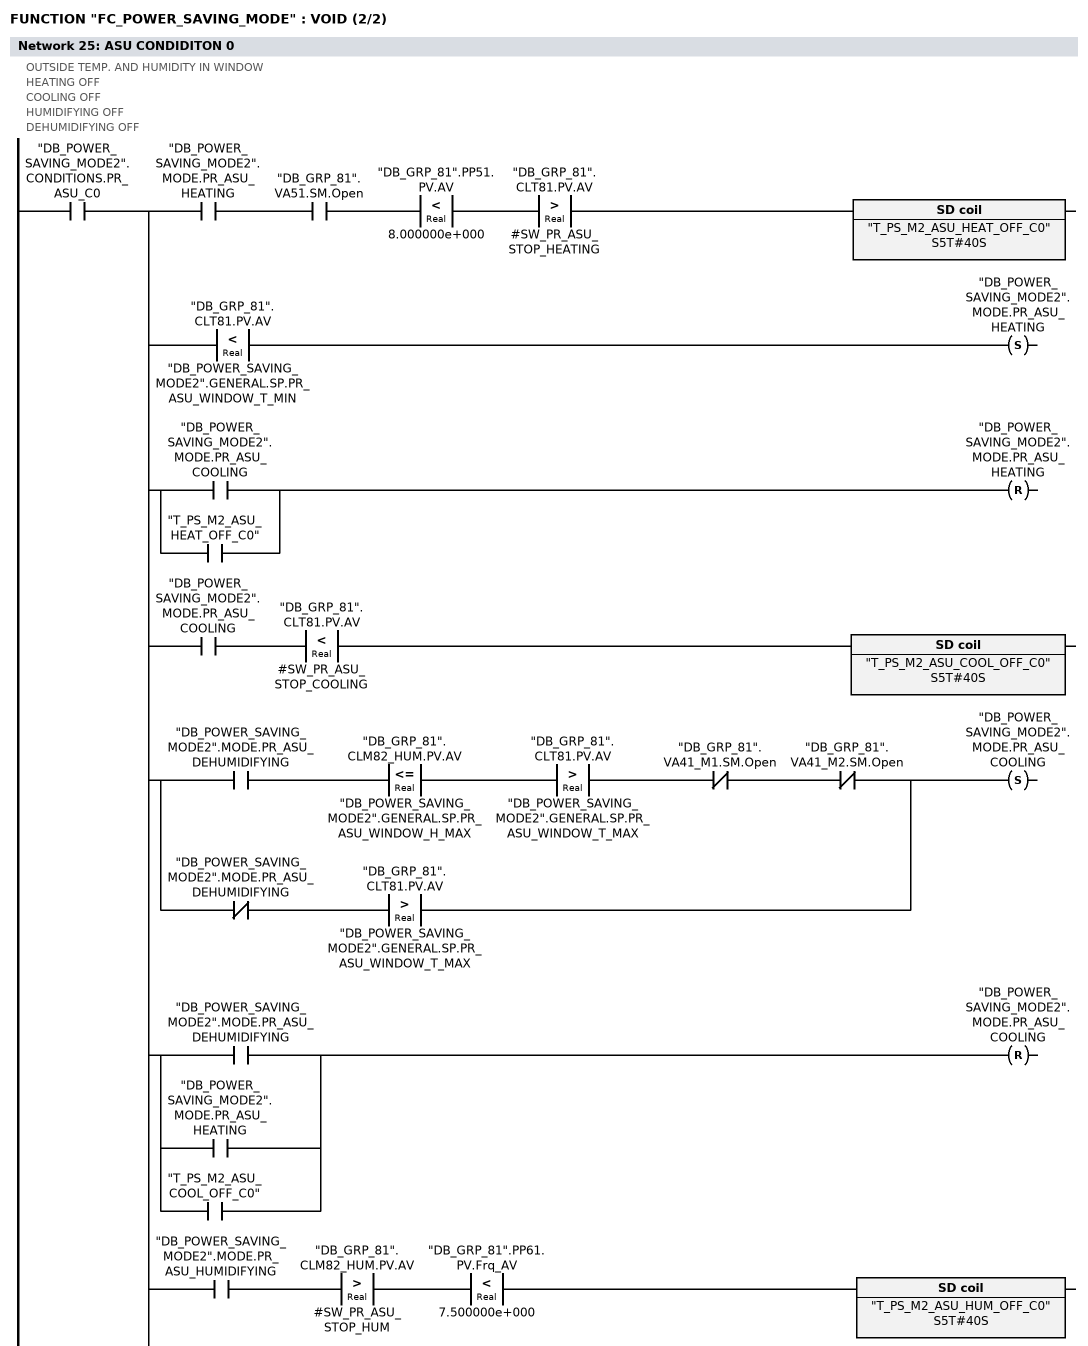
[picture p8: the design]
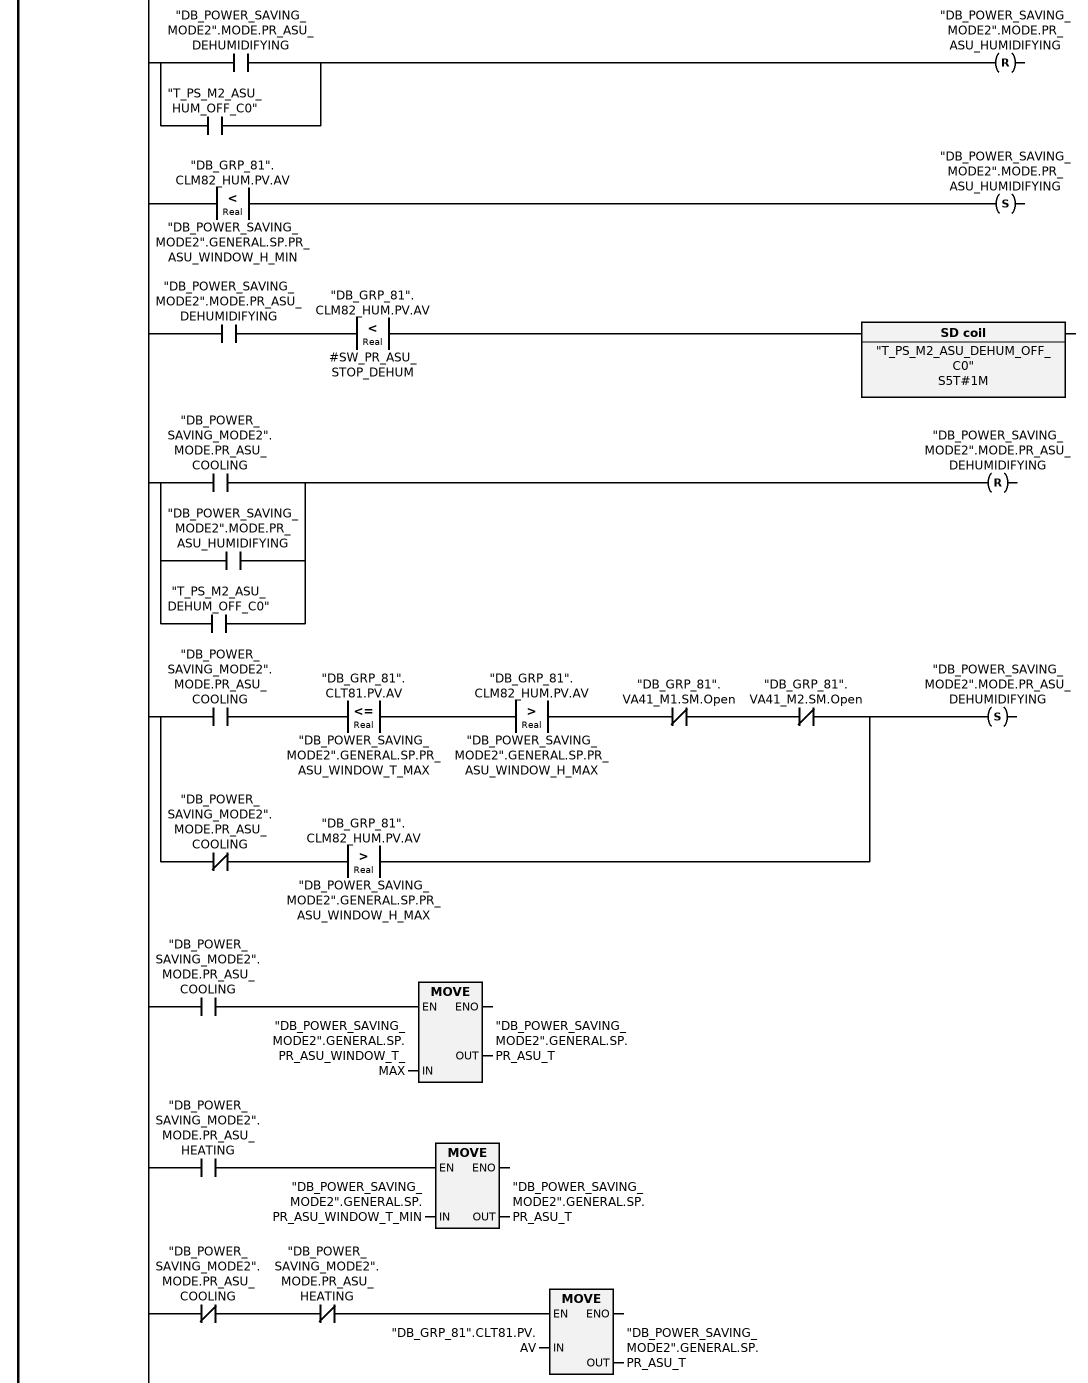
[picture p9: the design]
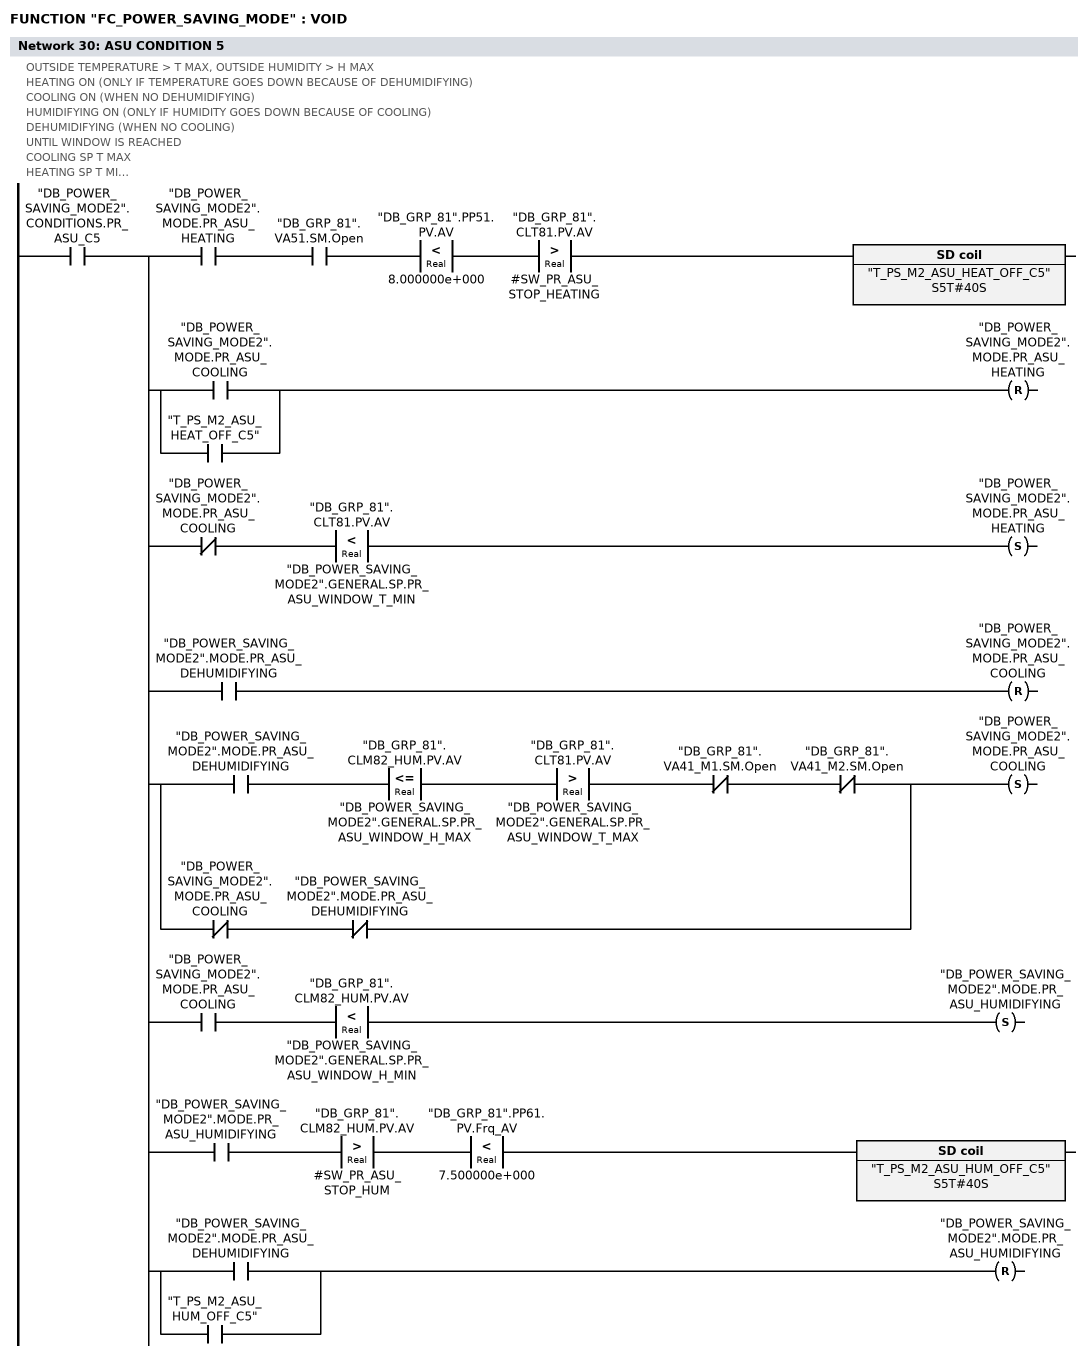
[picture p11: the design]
FUNCTION "FC_POWER_SAVING_MODE" : VOID
TITLE =POWER SAVING MODE
{ S7_language := '9(1) Angielski (Stany Zjednoczone)  11.01.2022  09:45:15' }
VERSION : 0.1


VAR_TEMP
  CDT : DATE_AND_TIME ;
  READ_CLOCK_RET_VAL : INT ;
  ACT_TIME : TIME_OF_DAY ;
  ACT_TIME_H : INT ;
  ACT_TIME_M : INT ;
  ACT_TIME_S : INT ;
  SW_PR_ASU_STOP_HEATING : REAL ;
  SW_PR_ASU_START_HEATING : REAL ;
  SW_PR_ASU_STOP_COOLING : REAL ;
  SW_PR_ASU_STOP_HUM : REAL ;
  SW_PR_ASU_STOP_DEHUM : REAL ;
  SW_PR_ASU_START_COOLING : REAL ;
  SW_PR_ARU_STOP_COOLING : REAL ;
  SW_PR_ARU_STOP_DEHUM : REAL ;
  SW_PR_ARU_START_COOLING : REAL ;
  SW_PR_F_STOP_HEATING : REAL ;
  SW_CR_ASU_STOP_HEATING : REAL ;
  SW_CR_ASU_STOP_COOLING : REAL ;
  SW_CR_ASU_STOP_HUM : REAL ;
  SW_CR_ASU_STOP_DEHUM : REAL ;
  SW_CR_ASU_START_COOLING : REAL ;
  SW_CR_ASU_START_HEATING : REAL ;
END_VAR
BEGIN
NETWORK
TITLE =READING ACTUAL TIME FROM PLC
//********************************************************************************
//
//                         AUTOMATIC SETPOINTS UPDATE
//
//********************************************************************************
//
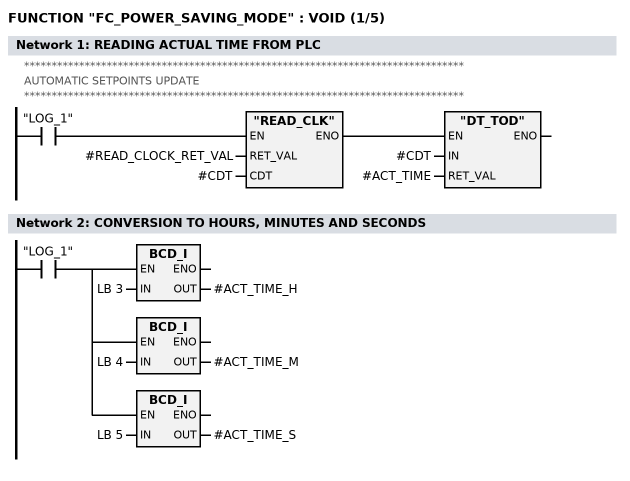
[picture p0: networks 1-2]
      U(    ;
      U     "LOG_1";
      SPBNB _001;
      CALL "READ_CLK" (
           RET_VAL                  := #READ_CLOCK_RET_VAL,
           CDT                      := #CDT);
_001: U     BIE;
      )     ;
      SPBNB _002;
      CALL "DT_TOD" (
           IN                       := #CDT,
           RET_VAL                  := #ACT_TIME);
_002: NOP   0;
NETWORK
TITLE =CONVERSION TO HOURS, MINUTES AND SECONDS

      U     "LOG_1";
      =     L     60.0;
      U     L     60.0;
      SPBNB _J1;
      L     LB     3;
      BTI   ;
      T     #ACT_TIME_H;
_J1:  NOP   0;
      U     L     60.0;
      SPBNB _J2;
      L     LB     4;
      BTI   ;
      T     #ACT_TIME_M;
_J2:  NOP   0;
      U     L     60.0;
      SPBNB _J3;
      L     LB     5;
      BTI   ;
      T     #ACT_TIME_S;
_J3:  NOP   0;
NETWORK
TITLE =LIMIT TIME SET BY OPERATOR

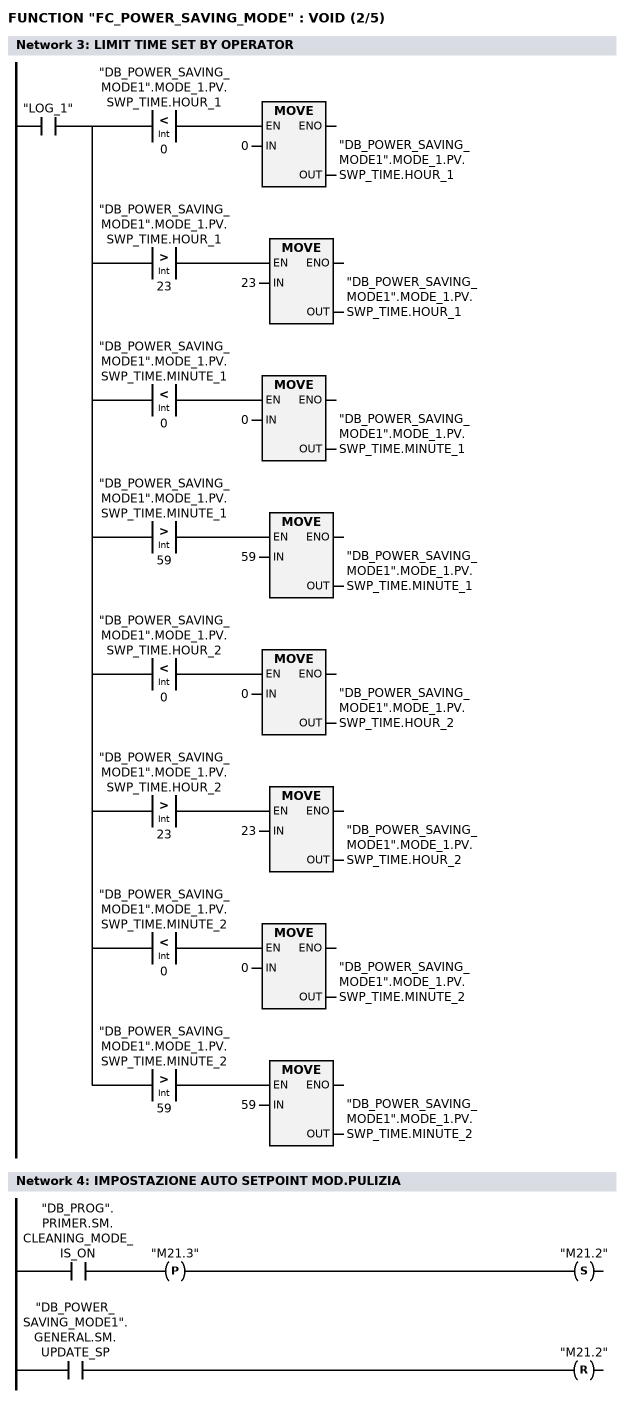
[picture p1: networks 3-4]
      U     "LOG_1";
      =     L     84.0;
      U     L     84.0;
      U(    ;
      L     "DB_POWER_SAVING_MODE1".MODE_1.PV.SWP_TIME.HOUR_1;
      L     0;
      <I    ;
      )     ;
      SPBNB _003;
      L     0;
      T     "DB_POWER_SAVING_MODE1".MODE_1.PV.SWP_TIME.HOUR_1;
_003: NOP   0;
      U     L     84.0;
      U(    ;
      L     "DB_POWER_SAVING_MODE1".MODE_1.PV.SWP_TIME.HOUR_1;
      L     23;
      >I    ;
      )     ;
      SPBNB _004;
      L     23;
      T     "DB_POWER_SAVING_MODE1".MODE_1.PV.SWP_TIME.HOUR_1;
_004: NOP   0;
      U     L     84.0;
      U(    ;
      L     "DB_POWER_SAVING_MODE1".MODE_1.PV.SWP_TIME.MINUTE_1;
      L     0;
      <I    ;
      )     ;
      SPBNB _005;
      L     0;
      T     "DB_POWER_SAVING_MODE1".MODE_1.PV.SWP_TIME.MINUTE_1;
_005: NOP   0;
      U     L     84.0;
      U(    ;
      L     "DB_POWER_SAVING_MODE1".MODE_1.PV.SWP_TIME.MINUTE_1;
      L     59;
      >I    ;
      )     ;
      SPBNB _006;
      L     59;
      T     "DB_POWER_SAVING_MODE1".MODE_1.PV.SWP_TIME.MINUTE_1;
_006: NOP   0;
      U     L     84.0;
      U(    ;
      L     "DB_POWER_SAVING_MODE1".MODE_1.PV.SWP_TIME.HOUR_2;
      L     0;
      <I    ;
      )     ;
      SPBNB _007;
      L     0;
      T     "DB_POWER_SAVING_MODE1".MODE_1.PV.SWP_TIME.HOUR_2;
_007: NOP   0;
      U     L     84.0;
      U(    ;
      L     "DB_POWER_SAVING_MODE1".MODE_1.PV.SWP_TIME.HOUR_2;
      L     23;
      >I    ;
      )     ;
      SPBNB _008;
      L     23;
      T     "DB_POWER_SAVING_MODE1".MODE_1.PV.SWP_TIME.HOUR_2;
_008: NOP   0;
      U     L     84.0;
      U(    ;
      L     "DB_POWER_SAVING_MODE1".MODE_1.PV.SWP_TIME.MINUTE_2;
      L     0;
      <I    ;
      )     ;
      SPBNB _009;
      L     0;
      T     "DB_POWER_SAVING_MODE1".MODE_1.PV.SWP_TIME.MINUTE_2;
_009: NOP   0;
      U     L     84.0;
      U(    ;
      L     "DB_POWER_SAVING_MODE1".MODE_1.PV.SWP_TIME.MINUTE_2;
      L     59;
      >I    ;
      )     ;
      SPBNB _00a;
      L     59;
      T     "DB_POWER_SAVING_MODE1".MODE_1.PV.SWP_TIME.MINUTE_2;
_00a: NOP   0;
NETWORK
TITLE =IMPOSTAZIONE AUTO SETPOINT MOD.PULIZIA

      U     "DB_PROG".PRIMER.SM.CLEANING_MODE_IS_ON;
      FP    "M21.3";
      S     "M21.2";
      U     "DB_POWER_SAVING_MODE1".GENERAL.SM.UPDATE_SP;
      R     "M21.2";
      NOP   0;
NETWORK
TITLE =CHANGE SETPOINTS TWO TIMES PER DAY ACCORDING TO TIME SET

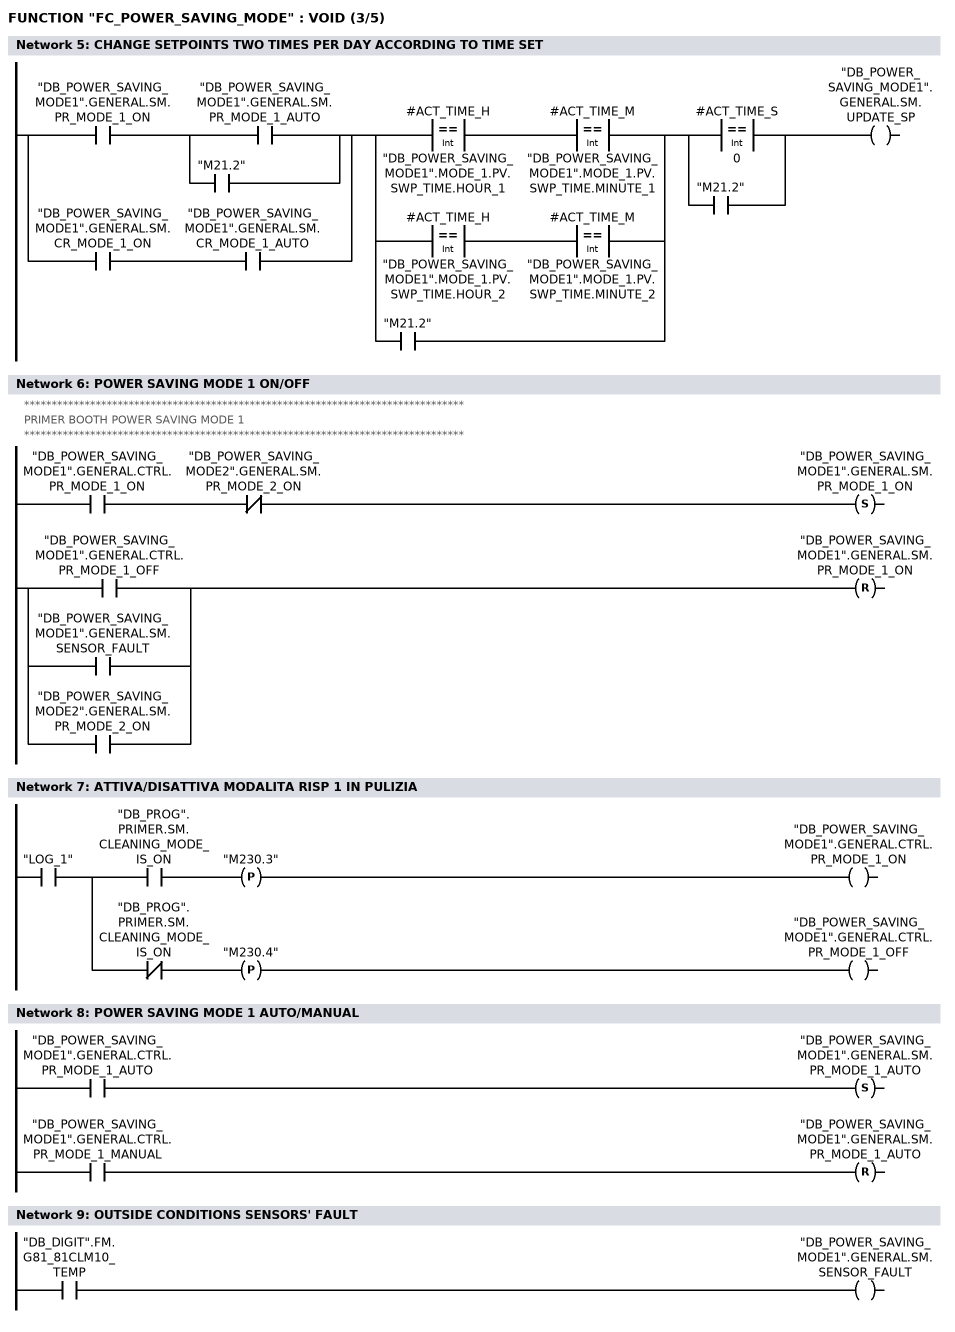
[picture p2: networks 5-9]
      U(    ;
      U     "DB_POWER_SAVING_MODE1".GENERAL.SM.PR_MODE_1_ON;
      U(    ;
      O     "DB_POWER_SAVING_MODE1".GENERAL.SM.PR_MODE_1_AUTO;
      O     "M21.2";
      )     ;
      O     ;
      U     "DB_POWER_SAVING_MODE1".GENERAL.SM.CR_MODE_1_ON;
      U     "DB_POWER_SAVING_MODE1".GENERAL.SM.CR_MODE_1_AUTO;
      )     ;
      U(    ;
      U(    ;
      L     #ACT_TIME_H;
      L     "DB_POWER_SAVING_MODE1".MODE_1.PV.SWP_TIME.HOUR_1;
      ==I   ;
      )     ;
      U(    ;
      L     #ACT_TIME_M;
      L     "DB_POWER_SAVING_MODE1".MODE_1.PV.SWP_TIME.MINUTE_1;
      ==I   ;
      )     ;
      O     ;
      U(    ;
      L     #ACT_TIME_H;
      L     "DB_POWER_SAVING_MODE1".MODE_1.PV.SWP_TIME.HOUR_2;
      ==I   ;
      )     ;
      U(    ;
      L     #ACT_TIME_M;
      L     "DB_POWER_SAVING_MODE1".MODE_1.PV.SWP_TIME.MINUTE_2;
      ==I   ;
      )     ;
      O     "M21.2";
      )     ;
      U(    ;
      O(    ;
      L     #ACT_TIME_S;
      L     0;
      ==I   ;
      )     ;
      O     "M21.2";
      )     ;
      =     "DB_POWER_SAVING_MODE1".GENERAL.SM.UPDATE_SP;
NETWORK
TITLE =POWER SAVING MODE 1 ON/OFF
//********************************************************************************
//
//                     PRIMER BOOTH POWER SAVING MODE 1
//
//********************************************************************************
//
      U     "DB_POWER_SAVING_MODE1".GENERAL.CTRL.PR_MODE_1_ON;
      UN    "DB_POWER_SAVING_MODE2".GENERAL.SM.PR_MODE_2_ON;
      S     "DB_POWER_SAVING_MODE1".GENERAL.SM.PR_MODE_1_ON;
      U(    ;
      O     "DB_POWER_SAVING_MODE1".GENERAL.CTRL.PR_MODE_1_OFF;
      O     "DB_POWER_SAVING_MODE1".GENERAL.SM.SENSOR_FAULT;
      O     "DB_POWER_SAVING_MODE2".GENERAL.SM.PR_MODE_2_ON;
      )     ;
      R     "DB_POWER_SAVING_MODE1".GENERAL.SM.PR_MODE_1_ON;
      NOP   0;
NETWORK
TITLE =ATTIVA/DISATTIVA MODALITA RISP 1 IN PULIZIA

      U     "LOG_1";
      =     L     84.0;
      U     L     84.0;
      U     "DB_PROG".PRIMER.SM.CLEANING_MODE_IS_ON;
      FP    "M230.3";
      =     "DB_POWER_SAVING_MODE1".GENERAL.CTRL.PR_MODE_1_ON;
      U     L     84.0;
      UN    "DB_PROG".PRIMER.SM.CLEANING_MODE_IS_ON;
      FP    "M230.4";
      =     "DB_POWER_SAVING_MODE1".GENERAL.CTRL.PR_MODE_1_OFF;
NETWORK
TITLE =POWER SAVING MODE 1 AUTO/MANUAL

      U     "DB_POWER_SAVING_MODE1".GENERAL.CTRL.PR_MODE_1_AUTO;
      S     "DB_POWER_SAVING_MODE1".GENERAL.SM.PR_MODE_1_AUTO;
      U     "DB_POWER_SAVING_MODE1".GENERAL.CTRL.PR_MODE_1_MANUAL;
      R     "DB_POWER_SAVING_MODE1".GENERAL.SM.PR_MODE_1_AUTO;
      NOP   0;
NETWORK
TITLE =OUTSIDE CONDITIONS SENSORS' FAULT

      U     "DB_DIGIT".FM.G81_81CLM10_TEMP;
      =     "DB_POWER_SAVING_MODE1".GENERAL.SM.SENSOR_FAULT;
NETWORK
TITLE =EXTREME SUMMER MODE

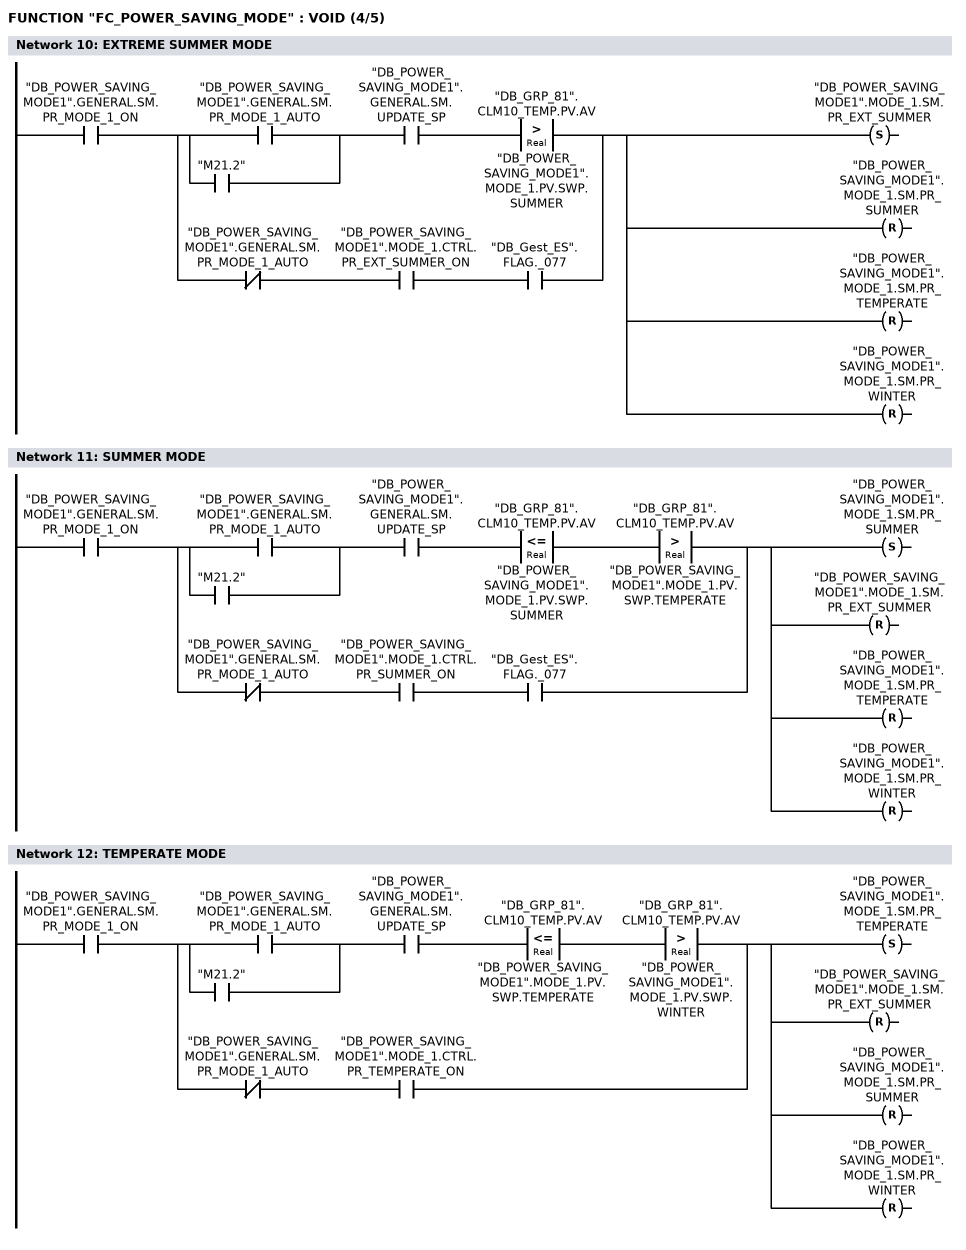
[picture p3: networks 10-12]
      U     "DB_POWER_SAVING_MODE1".GENERAL.SM.PR_MODE_1_ON;
      U(    ;
      U(    ;
      O     "DB_POWER_SAVING_MODE1".GENERAL.SM.PR_MODE_1_AUTO;
      O     "M21.2";
      )     ;
      U     "DB_POWER_SAVING_MODE1".GENERAL.SM.UPDATE_SP;
      U(    ;
      L     "DB_GRP_81".CLM10_TEMP.PV.AV;
      L     "DB_POWER_SAVING_MODE1".MODE_1.PV.SWP.SUMMER;
      >R    ;
      )     ;
      O     ;
      UN    "DB_POWER_SAVING_MODE1".GENERAL.SM.PR_MODE_1_AUTO;
      U     "DB_POWER_SAVING_MODE1".MODE_1.CTRL.PR_EXT_SUMMER_ON;
      U     "DB_Gest_ES".FLAG._077;
      )     ;
      S     "DB_POWER_SAVING_MODE1".MODE_1.SM.PR_EXT_SUMMER;
      R     "DB_POWER_SAVING_MODE1".MODE_1.SM.PR_SUMMER;
      R     "DB_POWER_SAVING_MODE1".MODE_1.SM.PR_TEMPERATE;
      R     "DB_POWER_SAVING_MODE1".MODE_1.SM.PR_WINTER;
NETWORK
TITLE =SUMMER MODE

      U     "DB_POWER_SAVING_MODE1".GENERAL.SM.PR_MODE_1_ON;
      U(    ;
      U(    ;
      O     "DB_POWER_SAVING_MODE1".GENERAL.SM.PR_MODE_1_AUTO;
      O     "M21.2";
      )     ;
      U     "DB_POWER_SAVING_MODE1".GENERAL.SM.UPDATE_SP;
      U(    ;
      L     "DB_GRP_81".CLM10_TEMP.PV.AV;
      L     "DB_POWER_SAVING_MODE1".MODE_1.PV.SWP.SUMMER;
      <=R   ;
      )     ;
      U(    ;
      L     "DB_GRP_81".CLM10_TEMP.PV.AV;
      L     "DB_POWER_SAVING_MODE1".MODE_1.PV.SWP.TEMPERATE;
      >R    ;
      )     ;
      O     ;
      UN    "DB_POWER_SAVING_MODE1".GENERAL.SM.PR_MODE_1_AUTO;
      U     "DB_POWER_SAVING_MODE1".MODE_1.CTRL.PR_SUMMER_ON;
      U     "DB_Gest_ES".FLAG._077;
      )     ;
      S     "DB_POWER_SAVING_MODE1".MODE_1.SM.PR_SUMMER;
      R     "DB_POWER_SAVING_MODE1".MODE_1.SM.PR_EXT_SUMMER;
      R     "DB_POWER_SAVING_MODE1".MODE_1.SM.PR_TEMPERATE;
      R     "DB_POWER_SAVING_MODE1".MODE_1.SM.PR_WINTER;
NETWORK
TITLE =TEMPERATE MODE

      U     "DB_POWER_SAVING_MODE1".GENERAL.SM.PR_MODE_1_ON;
      U(    ;
      U(    ;
      O     "DB_POWER_SAVING_MODE1".GENERAL.SM.PR_MODE_1_AUTO;
      O     "M21.2";
      )     ;
      U     "DB_POWER_SAVING_MODE1".GENERAL.SM.UPDATE_SP;
      U(    ;
      L     "DB_GRP_81".CLM10_TEMP.PV.AV;
      L     "DB_POWER_SAVING_MODE1".MODE_1.PV.SWP.TEMPERATE;
      <=R   ;
      )     ;
      U(    ;
      L     "DB_GRP_81".CLM10_TEMP.PV.AV;
      L     "DB_POWER_SAVING_MODE1".MODE_1.PV.SWP.WINTER;
      >R    ;
      )     ;
      O     ;
      UN    "DB_POWER_SAVING_MODE1".GENERAL.SM.PR_MODE_1_AUTO;
      U     "DB_POWER_SAVING_MODE1".MODE_1.CTRL.PR_TEMPERATE_ON;
      )     ;
      S     "DB_POWER_SAVING_MODE1".MODE_1.SM.PR_TEMPERATE;
      R     "DB_POWER_SAVING_MODE1".MODE_1.SM.PR_EXT_SUMMER;
      R     "DB_POWER_SAVING_MODE1".MODE_1.SM.PR_SUMMER;
      R     "DB_POWER_SAVING_MODE1".MODE_1.SM.PR_WINTER;
NETWORK
TITLE =WINTER MODE

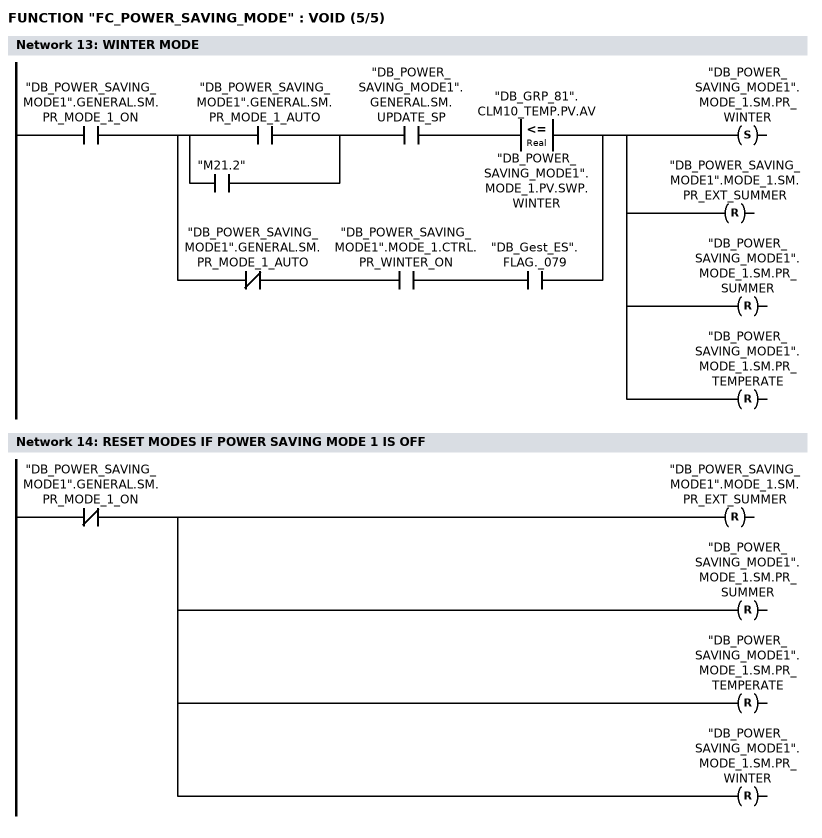
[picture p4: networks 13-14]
      U     "DB_POWER_SAVING_MODE1".GENERAL.SM.PR_MODE_1_ON;
      U(    ;
      U(    ;
      O     "DB_POWER_SAVING_MODE1".GENERAL.SM.PR_MODE_1_AUTO;
      O     "M21.2";
      )     ;
      U     "DB_POWER_SAVING_MODE1".GENERAL.SM.UPDATE_SP;
      U(    ;
      L     "DB_GRP_81".CLM10_TEMP.PV.AV;
      L     "DB_POWER_SAVING_MODE1".MODE_1.PV.SWP.WINTER;
      <=R   ;
      )     ;
      O     ;
      UN    "DB_POWER_SAVING_MODE1".GENERAL.SM.PR_MODE_1_AUTO;
      U     "DB_POWER_SAVING_MODE1".MODE_1.CTRL.PR_WINTER_ON;
      U     "DB_Gest_ES".FLAG._079;
      )     ;
      S     "DB_POWER_SAVING_MODE1".MODE_1.SM.PR_WINTER;
      R     "DB_POWER_SAVING_MODE1".MODE_1.SM.PR_EXT_SUMMER;
      R     "DB_POWER_SAVING_MODE1".MODE_1.SM.PR_SUMMER;
      R     "DB_POWER_SAVING_MODE1".MODE_1.SM.PR_TEMPERATE;
NETWORK
TITLE =RESET MODES IF POWER SAVING MODE 1 IS OFF

      UN    "DB_POWER_SAVING_MODE1".GENERAL.SM.PR_MODE_1_ON;
      R     "DB_POWER_SAVING_MODE1".MODE_1.SM.PR_EXT_SUMMER;
      R     "DB_POWER_SAVING_MODE1".MODE_1.SM.PR_SUMMER;
      R     "DB_POWER_SAVING_MODE1".MODE_1.SM.PR_TEMPERATE;
      R     "DB_POWER_SAVING_MODE1".MODE_1.SM.PR_WINTER;
NETWORK
TITLE =SETPOINT SELECTION

      U     "LOG_1";
      =     L     84.0;
      U     L     84.0;
      U     "DB_POWER_SAVING_MODE1".MODE_1.SM.PR_EXT_SUMMER;
      =     L     84.1;
      U     L     84.1;
      SPBNB _00b;
      L     "DB_POWER_SAVING_MODE1".MODE_1.PV.SP.PR_ASU_EXT_SUMMER_T;
      T     "DB_POWER_SAVING_MODE1".MODE_1.PV.SP.PR_ASU_T;
_00b: NOP   0;
      U     L     84.1;
      SPBNB _00c;
      L     "DB_POWER_SAVING_MODE1".MODE_1.PV.SP.PR_ASU_EXT_SUMMER_H;
      T     "DB_POWER_SAVING_MODE1".MODE_1.PV.SP.PR_ASU_H;
_00c: NOP   0;
      U     L     84.1;
      SPBNB _00d;
      L     "DB_POWER_SAVING_MODE1".MODE_1.PV.SP.PR_ARU_EXT_SUMMER_T;
      T     "DB_POWER_SAVING_MODE1".MODE_1.PV.SP.PR_ARU_T;
_00d: NOP   0;
      U     L     84.1;
      SPBNB _00e;
      L     "DB_POWER_SAVING_MODE1".MODE_1.PV.SP.PR_ARU_EXT_SUMMER_H;
      T     "DB_POWER_SAVING_MODE1".MODE_1.PV.SP.PR_ARU_H;
_00e: NOP   0;
      U     L     84.1;
      SPBNB _00f;
      L     "DB_POWER_SAVING_MODE1".MODE_1.PV.SP.PR_FLASHOFF_EXT_SUMMER_T;
      T     "DB_POWER_SAVING_MODE1".MODE_1.PV.SP.PR_FLASHOFF_T;
_00f: NOP   0;
      U     L     84.0;
      U     "DB_POWER_SAVING_MODE1".MODE_1.SM.PR_SUMMER;
      =     L     84.1;
      U     L     84.1;
      SPBNB _010;
      L     "DB_POWER_SAVING_MODE1".MODE_1.PV.SP.PR_ASU_SUMMER_T;
      T     "DB_POWER_SAVING_MODE1".MODE_1.PV.SP.PR_ASU_T;
_010: NOP   0;
      U     L     84.1;
      SPBNB _011;
      L     "DB_POWER_SAVING_MODE1".MODE_1.PV.SP.PR_ASU_SUMMER_H;
      T     "DB_POWER_SAVING_MODE1".MODE_1.PV.SP.PR_ASU_H;
_011: NOP   0;
      U     L     84.1;
      SPBNB _012;
      L     "DB_POWER_SAVING_MODE1".MODE_1.PV.SP.PR_ARU_SUMMER_T;
      T     "DB_POWER_SAVING_MODE1".MODE_1.PV.SP.PR_ARU_T;
_012: NOP   0;
      U     L     84.1;
      SPBNB _013;
      L     "DB_POWER_SAVING_MODE1".MODE_1.PV.SP.PR_ARU_SUMMER_H;
      T     "DB_POWER_SAVING_MODE1".MODE_1.PV.SP.PR_ARU_H;
_013: NOP   0;
      U     L     84.1;
      SPBNB _014;
      L     "DB_POWER_SAVING_MODE1".MODE_1.PV.SP.PR_FLASHOFF_SUMMER_T;
      T     "DB_POWER_SAVING_MODE1".MODE_1.PV.SP.PR_FLASHOFF_T;
_014: NOP   0;
      U     L     84.0;
      U     "DB_POWER_SAVING_MODE1".MODE_1.SM.PR_TEMPERATE;
      =     L     84.1;
      U     L     84.1;
      SPBNB _015;
      L     "DB_POWER_SAVING_MODE1".MODE_1.PV.SP.PR_ASU_TEMPERATE_T;
      T     "DB_POWER_SAVING_MODE1".MODE_1.PV.SP.PR_ASU_T;
_015: NOP   0;
      U     L     84.1;
      SPBNB _016;
      L     "DB_POWER_SAVING_MODE1".MODE_1.PV.SP.PR_ASU_TEMPERATE_H;
      T     "DB_POWER_SAVING_MODE1".MODE_1.PV.SP.PR_ASU_H;
_016: NOP   0;
      U     L     84.1;
      SPBNB _017;
      L     "DB_POWER_SAVING_MODE1".MODE_1.PV.SP.PR_ARU_TEMPERATE_T;
      T     "DB_POWER_SAVING_MODE1".MODE_1.PV.SP.PR_ARU_T;
_017: NOP   0;
      U     L     84.1;
      SPBNB _018;
      L     "DB_POWER_SAVING_MODE1".MODE_1.PV.SP.PR_ARU_TEMPERATE_H;
      T     "DB_POWER_SAVING_MODE1".MODE_1.PV.SP.PR_ARU_H;
_018: NOP   0;
      U     L     84.1;
      SPBNB _019;
      L     "DB_POWER_SAVING_MODE1".MODE_1.PV.SP.PR_FLASHOFF_TEMPERATE_T;
      T     "DB_POWER_SAVING_MODE1".MODE_1.PV.SP.PR_FLASHOFF_T;
_019: NOP   0;
      U     L     84.0;
      U     "DB_POWER_SAVING_MODE1".MODE_1.SM.PR_WINTER;
      =     L     84.1;
      U     L     84.1;
      SPBNB _01a;
      L     "DB_POWER_SAVING_MODE1".MODE_1.PV.SP.PR_ASU_WINTER_T;
      T     "DB_POWER_SAVING_MODE1".MODE_1.PV.SP.PR_ASU_T;
_01a: NOP   0;
      U     L     84.1;
      SPBNB _01b;
      L     "DB_POWER_SAVING_MODE1".MODE_1.PV.SP.PR_ASU_WINTER_H;
      T     "DB_POWER_SAVING_MODE1".MODE_1.PV.SP.PR_ASU_H;
_01b: NOP   0;
      U     L     84.1;
      SPBNB _01c;
      L     "DB_POWER_SAVING_MODE1".MODE_1.PV.SP.PR_ARU_WINTER_T;
      T     "DB_POWER_SAVING_MODE1".MODE_1.PV.SP.PR_ARU_T;
_01c: NOP   0;
      U     L     84.1;
      SPBNB _01d;
      L     "DB_POWER_SAVING_MODE1".MODE_1.PV.SP.PR_ARU_WINTER_H;
      T     "DB_POWER_SAVING_MODE1".MODE_1.PV.SP.PR_ARU_H;
_01d: NOP   0;
      U     L     84.1;
      SPBNB _01e;
      L     "DB_POWER_SAVING_MODE1".MODE_1.PV.SP.PR_FLASHOFF_WINTER_T;
      T     "DB_POWER_SAVING_MODE1".MODE_1.PV.SP.PR_FLASHOFF_T;
_01e: NOP   0;
NETWORK
TITLE =DEFAULT MODE

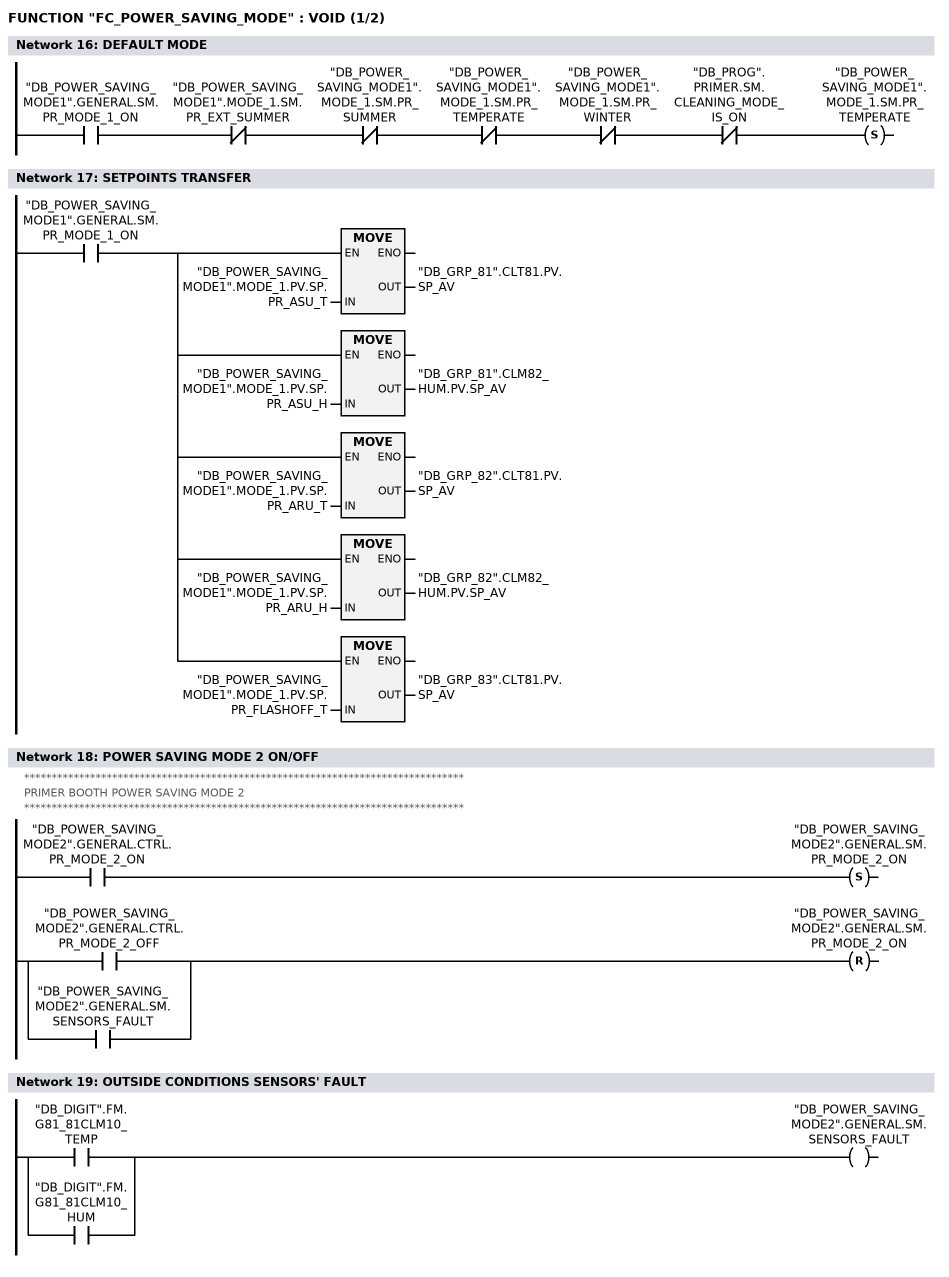
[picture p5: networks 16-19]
      U     "DB_POWER_SAVING_MODE1".GENERAL.SM.PR_MODE_1_ON;
      UN    "DB_POWER_SAVING_MODE1".MODE_1.SM.PR_EXT_SUMMER;
      UN    "DB_POWER_SAVING_MODE1".MODE_1.SM.PR_SUMMER;
      UN    "DB_POWER_SAVING_MODE1".MODE_1.SM.PR_TEMPERATE;
      UN    "DB_POWER_SAVING_MODE1".MODE_1.SM.PR_WINTER;
      UN    "DB_PROG".PRIMER.SM.CLEANING_MODE_IS_ON;
      S     "DB_POWER_SAVING_MODE1".MODE_1.SM.PR_TEMPERATE;
NETWORK
TITLE =SETPOINTS TRANSFER

      U     "DB_POWER_SAVING_MODE1".GENERAL.SM.PR_MODE_1_ON;
      =     L     84.0;
      U     L     84.0;
      SPBNB _01f;
      L     "DB_POWER_SAVING_MODE1".MODE_1.PV.SP.PR_ASU_T;
      T     "DB_GRP_81".CLT81.PV.SP_AV;
_01f: NOP   0;
      U     L     84.0;
      SPBNB _020;
      L     "DB_POWER_SAVING_MODE1".MODE_1.PV.SP.PR_ASU_H;
      T     "DB_GRP_81".CLM82_HUM.PV.SP_AV;
_020: NOP   0;
      U     L     84.0;
      SPBNB _021;
      L     "DB_POWER_SAVING_MODE1".MODE_1.PV.SP.PR_ARU_T;
      T     "DB_GRP_82".CLT81.PV.SP_AV;
_021: NOP   0;
      U     L     84.0;
      SPBNB _022;
      L     "DB_POWER_SAVING_MODE1".MODE_1.PV.SP.PR_ARU_H;
      T     "DB_GRP_82".CLM82_HUM.PV.SP_AV;
_022: NOP   0;
      U     L     84.0;
      SPBNB _023;
      L     "DB_POWER_SAVING_MODE1".MODE_1.PV.SP.PR_FLASHOFF_T;
      T     "DB_GRP_83".CLT81.PV.SP_AV;
_023: NOP   0;
NETWORK
TITLE =POWER SAVING MODE 2 ON/OFF
//********************************************************************************
//
//                     PRIMER BOOTH POWER SAVING MODE 2
//
//********************************************************************************
//
      U     "DB_POWER_SAVING_MODE2".GENERAL.CTRL.PR_MODE_2_ON;
      S     "DB_POWER_SAVING_MODE2".GENERAL.SM.PR_MODE_2_ON;
      U(    ;
      O     "DB_POWER_SAVING_MODE2".GENERAL.CTRL.PR_MODE_2_OFF;
      O     "DB_POWER_SAVING_MODE2".GENERAL.SM.SENSORS_FAULT;
      )     ;
      R     "DB_POWER_SAVING_MODE2".GENERAL.SM.PR_MODE_2_ON;
      NOP   0;
NETWORK
TITLE =OUTSIDE CONDITIONS SENSORS' FAULT

      O     "DB_DIGIT".FM.G81_81CLM10_TEMP;
      O     "DB_DIGIT".FM.G81_81CLM10_HUM;
      =     "DB_POWER_SAVING_MODE2".GENERAL.SM.SENSORS_FAULT;
NETWORK
TITLE =TIME BASE FOR AVERANGING (PULSE EVERY 30 S)

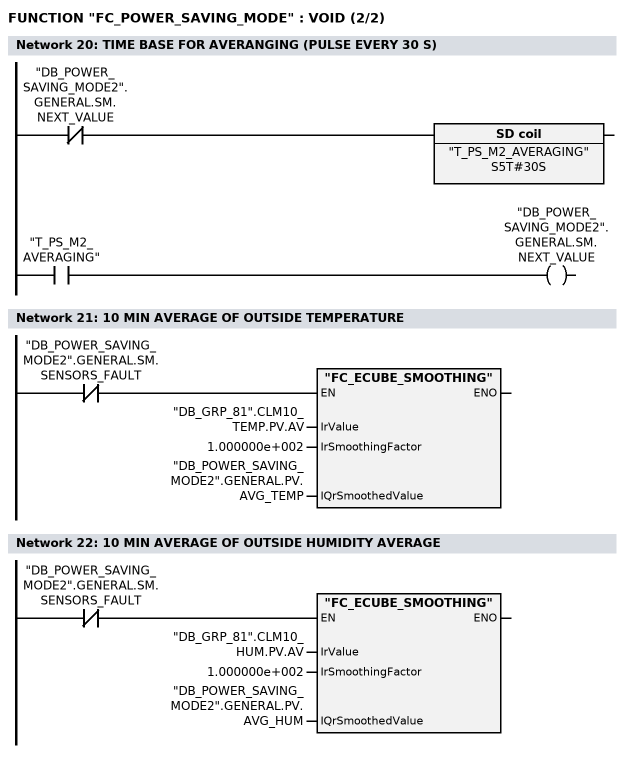
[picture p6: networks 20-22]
      UN    "DB_POWER_SAVING_MODE2".GENERAL.SM.NEXT_VALUE;
      L     S5T#30S;
      SE    "T_PS_M2_AVERAGING";

      U     "T_PS_M2_AVERAGING";
      =     "DB_POWER_SAVING_MODE2".GENERAL.SM.NEXT_VALUE;

NETWORK
TITLE =10 MIN AVERAGE OF OUTSIDE TEMPERATURE

      UN    "DB_POWER_SAVING_MODE2".GENERAL.SM.SENSORS_FAULT;
      SPBNB _024;
      CALL "FC_ECUBE_SMOOTHING" (
           IrValue                  := "DB_GRP_81".CLM10_TEMP.PV.AV,
           IrSmoothingFactor        := 1.000000e+002,
           IQrSmoothedValue         := "DB_POWER_SAVING_MODE2".GENERAL.PV.AVG_TEMP);
_024: NOP   0;
NETWORK
TITLE =10 MIN AVERAGE OF OUTSIDE HUMIDITY AVERAGE

      UN    "DB_POWER_SAVING_MODE2".GENERAL.SM.SENSORS_FAULT;
      SPBNB _025;
      CALL "FC_ECUBE_SMOOTHING" (
           IrValue                  := "DB_GRP_81".CLM10_HUM.PV.AV,
           IrSmoothingFactor        := 1.000000e+002,
           IQrSmoothedValue         := "DB_POWER_SAVING_MODE2".GENERAL.PV.AVG_HUM);
_025: NOP   0;
NETWORK
TITLE =ASU OUTSIDE CONDITIONS

      U     "DB_POWER_SAVING_MODE2".GENERAL.SM.PR_MODE_2_ON;
      U(    ;
      U     "DB_PROG".PRIMER.SM.ON;
      UN    "DB_PROG".PRIMER.SM.START;
      O     ;
      UN    "DB_PROG".PRIMER.SM.ON;
      U     "DB_PROG".PRIMER.SM.STOP;
      UN    "PR_STOP_PROD_FANS";
      )     ;
      =     L     84.0;
      U     L     84.0;
      U(    ;
      L     "DB_POWER_SAVING_MODE2".GENERAL.PV.AVG_TEMP;
      L     "DB_POWER_SAVING_MODE2".GENERAL.SP.PR_ASU_WINDOW_T_MIN;
      >=R   ;
      )     ;
      U(    ;
      L     "DB_POWER_SAVING_MODE2".GENERAL.PV.AVG_TEMP;
      L     "DB_POWER_SAVING_MODE2".GENERAL.SP.PR_ASU_WINDOW_T_MAX;
      <=R   ;
      )     ;
      =     L     84.1;
      U     L     84.1;
      U(    ;
      L     "DB_POWER_SAVING_MODE2".GENERAL.PV.AVG_HUM;
      L     "DB_POWER_SAVING_MODE2".GENERAL.SP.PR_ASU_WINDOW_H_MIN;
      >=R   ;
      )     ;
      U(    ;
      L     "DB_POWER_SAVING_MODE2".GENERAL.PV.AVG_HUM;
      L     "DB_POWER_SAVING_MODE2".GENERAL.SP.PR_ASU_WINDOW_H_MAX;
      <=R   ;
      )     ;
      =     "DB_POWER_SAVING_MODE2".CONDITIONS.PR_ASU_C0;
      U     L     84.1;
      U(    ;
      L     "DB_POWER_SAVING_MODE2".GENERAL.PV.AVG_HUM;
      L     "DB_POWER_SAVING_MODE2".GENERAL.SP.PR_ASU_WINDOW_H_MIN;
      <R    ;
      )     ;
      =     "DB_POWER_SAVING_MODE2".CONDITIONS.PR_ASU_C2;
      U     L     84.1;
      U(    ;
      L     "DB_POWER_SAVING_MODE2".GENERAL.PV.AVG_HUM;
      L     "DB_POWER_SAVING_MODE2".GENERAL.SP.PR_ASU_WINDOW_H_MAX;
      >R    ;
      )     ;
      =     "DB_POWER_SAVING_MODE2".CONDITIONS.PR_ASU_C6;
      U     L     84.0;
      U(    ;
      L     "DB_POWER_SAVING_MODE2".GENERAL.PV.AVG_HUM;
      L     "DB_POWER_SAVING_MODE2".GENERAL.SP.PR_ASU_WINDOW_H_MIN;
      >=R   ;
      )     ;
      U(    ;
      L     "DB_POWER_SAVING_MODE2".GENERAL.PV.AVG_HUM;
      L     "DB_POWER_SAVING_MODE2".GENERAL.SP.PR_ASU_WINDOW_H_MAX;
      <=R   ;
      )     ;
      =     L     84.1;
      U     L     84.1;
      U(    ;
      L     "DB_POWER_SAVING_MODE2".GENERAL.PV.AVG_TEMP;
      L     "DB_POWER_SAVING_MODE2".GENERAL.SP.PR_ASU_WINDOW_T_MIN;
      <R    ;
      )     ;
      =     "DB_POWER_SAVING_MODE2".CONDITIONS.PR_ASU_C8;
      U     L     84.1;
      U(    ;
      L     "DB_POWER_SAVING_MODE2".GENERAL.PV.AVG_TEMP;
      L     "DB_POWER_SAVING_MODE2".GENERAL.SP.PR_ASU_WINDOW_T_MAX;
      >R    ;
      )     ;
      =     "DB_POWER_SAVING_MODE2".CONDITIONS.PR_ASU_C4;
      U     L     84.0;
      U(    ;
      L     "DB_POWER_SAVING_MODE2".GENERAL.PV.AVG_TEMP;
      L     "DB_POWER_SAVING_MODE2".GENERAL.SP.PR_ASU_WINDOW_T_MIN;
      <R    ;
      )     ;
      =     L     84.1;
      U     L     84.1;
      U(    ;
      L     "DB_POWER_SAVING_MODE2".GENERAL.PV.AVG_HUM;
      L     "DB_POWER_SAVING_MODE2".GENERAL.SP.PR_ASU_WINDOW_H_MIN;
      <R    ;
      )     ;
      =     "DB_POWER_SAVING_MODE2".CONDITIONS.PR_ASU_C1;
      U     L     84.1;
      U(    ;
      L     "DB_POWER_SAVING_MODE2".GENERAL.PV.AVG_HUM;
      L     "DB_POWER_SAVING_MODE2".GENERAL.SP.PR_ASU_WINDOW_H_MAX;
      >R    ;
      )     ;
      =     "DB_POWER_SAVING_MODE2".CONDITIONS.PR_ASU_C7;
      U     L     84.0;
      U(    ;
      L     "DB_POWER_SAVING_MODE2".GENERAL.PV.AVG_TEMP;
      L     "DB_POWER_SAVING_MODE2".GENERAL.SP.PR_ASU_WINDOW_T_MAX;
      >R    ;
      )     ;
      =     L     84.1;
      U     L     84.1;
      U(    ;
      L     "DB_POWER_SAVING_MODE2".GENERAL.PV.AVG_HUM;
      L     "DB_POWER_SAVING_MODE2".GENERAL.SP.PR_ASU_WINDOW_H_MIN;
      <R    ;
      )     ;
      =     "DB_POWER_SAVING_MODE2".CONDITIONS.PR_ASU_C3;
      U     L     84.1;
      U(    ;
      L     "DB_POWER_SAVING_MODE2".GENERAL.PV.AVG_HUM;
      L     "DB_POWER_SAVING_MODE2".GENERAL.SP.PR_ASU_WINDOW_H_MAX;
      >R    ;
      )     ;
      =     "DB_POWER_SAVING_MODE2".CONDITIONS.PR_ASU_C5;
      U     L     84.0;
      NOT   ;
      R     "DB_POWER_SAVING_MODE2".MODE.PR_ASU_HEATING;
      R     "DB_POWER_SAVING_MODE2".MODE.PR_ASU_COOLING;
      R     "DB_POWER_SAVING_MODE2".MODE.PR_ASU_HUMIDIFYING;
      R     "DB_POWER_SAVING_MODE2".MODE.PR_ASU_DEHUMIDIFYING;
NETWORK
TITLE =ASU SWITCHING POINTS

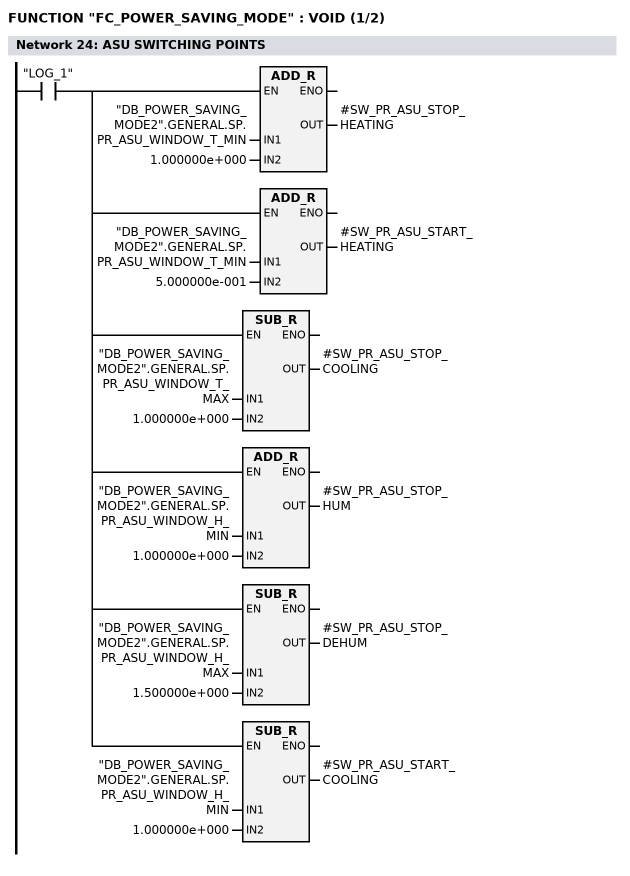
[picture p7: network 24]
      U     "LOG_1";
      =     L     84.0;
      U     L     84.0;
      SPBNB _026;
      L     "DB_POWER_SAVING_MODE2".GENERAL.SP.PR_ASU_WINDOW_T_MIN;
      L     1.000000e+000;
      +R    ;
      T     #SW_PR_ASU_STOP_HEATING;
_026: NOP   0;
      U     L     84.0;
      SPBNB _027;
      L     "DB_POWER_SAVING_MODE2".GENERAL.SP.PR_ASU_WINDOW_T_MIN;
      L     5.000000e-001;
      +R    ;
      T     #SW_PR_ASU_START_HEATING;
_027: NOP   0;
      U     L     84.0;
      SPBNB _028;
      L     "DB_POWER_SAVING_MODE2".GENERAL.SP.PR_ASU_WINDOW_T_MAX;
      L     1.000000e+000;
      -R    ;
      T     #SW_PR_ASU_STOP_COOLING;
_028: NOP   0;
      U     L     84.0;
      SPBNB _029;
      L     "DB_POWER_SAVING_MODE2".GENERAL.SP.PR_ASU_WINDOW_H_MIN;
      L     1.000000e+000;
      +R    ;
      T     #SW_PR_ASU_STOP_HUM;
_029: NOP   0;
      U     L     84.0;
      SPBNB _02a;
      L     "DB_POWER_SAVING_MODE2".GENERAL.SP.PR_ASU_WINDOW_H_MAX;
      L     1.500000e+000;
      -R    ;
      T     #SW_PR_ASU_STOP_DEHUM;
_02a: NOP   0;
      U     L     84.0;
      SPBNB _02b;
      L     "DB_POWER_SAVING_MODE2".GENERAL.SP.PR_ASU_WINDOW_H_MIN;
      L     1.000000e+000;
      -R    ;
      T     #SW_PR_ASU_START_COOLING;
_02b: NOP   0;
NETWORK
TITLE =ASU CONDIDITON 0
//OUTSIDE TEMP. AND HUMIDITY IN WINDOW
//
//HEATING OFF
//COOLING OFF
//HUMIDIFYING OFF
//DEHUMIDIFYING OFF
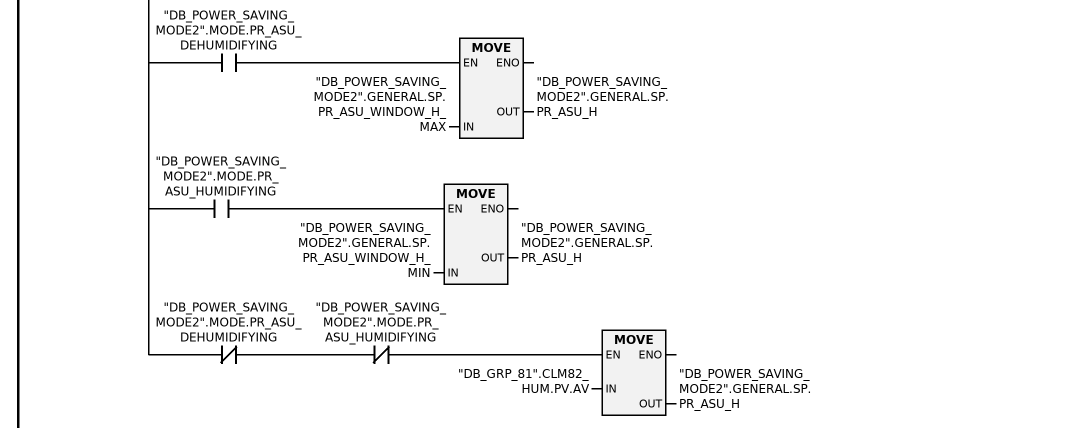
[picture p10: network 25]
      U     "DB_POWER_SAVING_MODE2".CONDITIONS.PR_ASU_C0;
      =     L     84.0;
      U     L     84.0;
      U     "DB_POWER_SAVING_MODE2".MODE.PR_ASU_HEATING;
      U     "DB_GRP_81".VA51.SM.Open;
      U(    ;
      L     "DB_GRP_81".PP51.PV.AV;
      L     8.000000e+000;
      <R    ;
      )     ;
      U(    ;
      L     "DB_GRP_81".CLT81.PV.AV;
      L     #SW_PR_ASU_STOP_HEATING;
      >R    ;
      )     ;
      L     S5T#40S;
      SE    "T_PS_M2_ASU_HEAT_OFF_C0";
      NOP   0;
      NOP   0;
      NOP   0;
      NOP   0;
      U     L     84.0;
      U(    ;
      L     "DB_GRP_81".CLT81.PV.AV;
      L     "DB_POWER_SAVING_MODE2".GENERAL.SP.PR_ASU_WINDOW_T_MIN;
      <R    ;
      )     ;
      S     "DB_POWER_SAVING_MODE2".MODE.PR_ASU_HEATING;
      U     L     84.0;
      U(    ;
      O     "DB_POWER_SAVING_MODE2".MODE.PR_ASU_COOLING;
      O     "T_PS_M2_ASU_HEAT_OFF_C0";
      )     ;
      R     "DB_POWER_SAVING_MODE2".MODE.PR_ASU_HEATING;
      U     L     84.0;
      U     "DB_POWER_SAVING_MODE2".MODE.PR_ASU_COOLING;
      U(    ;
      L     "DB_GRP_81".CLT81.PV.AV;
      L     #SW_PR_ASU_STOP_COOLING;
      <R    ;
      )     ;
      L     S5T#40S;
      SE    "T_PS_M2_ASU_COOL_OFF_C0";
      NOP   0;
      NOP   0;
      NOP   0;
      NOP   0;
      U     L     84.0;
      U(    ;
      U     "DB_POWER_SAVING_MODE2".MODE.PR_ASU_DEHUMIDIFYING;
      U(    ;
      L     "DB_GRP_81".CLM82_HUM.PV.AV;
      L     "DB_POWER_SAVING_MODE2".GENERAL.SP.PR_ASU_WINDOW_H_MAX;
      <=R   ;
      )     ;
      U(    ;
      L     "DB_GRP_81".CLT81.PV.AV;
      L     "DB_POWER_SAVING_MODE2".GENERAL.SP.PR_ASU_WINDOW_T_MAX;
      >R    ;
      )     ;
      UN    "DB_GRP_81".VA41_M1.SM.Open;
      UN    "DB_GRP_81".VA41_M2.SM.Open;
      O     ;
      UN    "DB_POWER_SAVING_MODE2".MODE.PR_ASU_DEHUMIDIFYING;
      U(    ;
      L     "DB_GRP_81".CLT81.PV.AV;
      L     "DB_POWER_SAVING_MODE2".GENERAL.SP.PR_ASU_WINDOW_T_MAX;
      >R    ;
      )     ;
      )     ;
      S     "DB_POWER_SAVING_MODE2".MODE.PR_ASU_COOLING;
      U     L     84.0;
      U(    ;
      O     "DB_POWER_SAVING_MODE2".MODE.PR_ASU_DEHUMIDIFYING;
      O     "DB_POWER_SAVING_MODE2".MODE.PR_ASU_HEATING;
      O     "T_PS_M2_ASU_COOL_OFF_C0";
      )     ;
      R     "DB_POWER_SAVING_MODE2".MODE.PR_ASU_COOLING;
      U     L     84.0;
      U     "DB_POWER_SAVING_MODE2".MODE.PR_ASU_HUMIDIFYING;
      U(    ;
      L     "DB_GRP_81".CLM82_HUM.PV.AV;
      L     #SW_PR_ASU_STOP_HUM;
      >R    ;
      )     ;
      U(    ;
      L     "DB_GRP_81".PP61.PV.Frq_AV;
      L     7.500000e+000;
      <R    ;
      )     ;
      L     S5T#40S;
      SE    "T_PS_M2_ASU_HUM_OFF_C0";
      NOP   0;
      NOP   0;
      NOP   0;
      NOP   0;
      U     L     84.0;
      U(    ;
      O     "DB_POWER_SAVING_MODE2".MODE.PR_ASU_DEHUMIDIFYING;
      O     "T_PS_M2_ASU_HUM_OFF_C0";
      )     ;
      R     "DB_POWER_SAVING_MODE2".MODE.PR_ASU_HUMIDIFYING;
      U     L     84.0;
      U(    ;
      L     "DB_GRP_81".CLM82_HUM.PV.AV;
      L     "DB_POWER_SAVING_MODE2".GENERAL.SP.PR_ASU_WINDOW_H_MIN;
      <R    ;
      )     ;
      S     "DB_POWER_SAVING_MODE2".MODE.PR_ASU_HUMIDIFYING;
      U     L     84.0;
      U     "DB_POWER_SAVING_MODE2".MODE.PR_ASU_DEHUMIDIFYING;
      U(    ;
      L     "DB_GRP_81".CLM82_HUM.PV.AV;
      L     #SW_PR_ASU_STOP_DEHUM;
      <R    ;
      )     ;
      L     S5T#1M;
      SE    "T_PS_M2_ASU_DEHUM_OFF_C0";
      NOP   0;
      NOP   0;
      NOP   0;
      NOP   0;
      U     L     84.0;
      U(    ;
      O     "DB_POWER_SAVING_MODE2".MODE.PR_ASU_COOLING;
      O     "DB_POWER_SAVING_MODE2".MODE.PR_ASU_HUMIDIFYING;
      O     "T_PS_M2_ASU_DEHUM_OFF_C0";
      )     ;
      R     "DB_POWER_SAVING_MODE2".MODE.PR_ASU_DEHUMIDIFYING;
      U     L     84.0;
      U(    ;
      U     "DB_POWER_SAVING_MODE2".MODE.PR_ASU_COOLING;
      U(    ;
      L     "DB_GRP_81".CLT81.PV.AV;
      L     "DB_POWER_SAVING_MODE2".GENERAL.SP.PR_ASU_WINDOW_T_MAX;
      <=R   ;
      )     ;
      U(    ;
      L     "DB_GRP_81".CLM82_HUM.PV.AV;
      L     "DB_POWER_SAVING_MODE2".GENERAL.SP.PR_ASU_WINDOW_H_MAX;
      >R    ;
      )     ;
      UN    "DB_GRP_81".VA41_M1.SM.Open;
      UN    "DB_GRP_81".VA41_M2.SM.Open;
      O     ;
      UN    "DB_POWER_SAVING_MODE2".MODE.PR_ASU_COOLING;
      U(    ;
      L     "DB_GRP_81".CLM82_HUM.PV.AV;
      L     "DB_POWER_SAVING_MODE2".GENERAL.SP.PR_ASU_WINDOW_H_MAX;
      >R    ;
      )     ;
      )     ;
      S     "DB_POWER_SAVING_MODE2".MODE.PR_ASU_DEHUMIDIFYING;
      U     L     84.0;
      U     "DB_POWER_SAVING_MODE2".MODE.PR_ASU_COOLING;
      SPBNB _02c;
      L     "DB_POWER_SAVING_MODE2".GENERAL.SP.PR_ASU_WINDOW_T_MAX;
      T     "DB_POWER_SAVING_MODE2".GENERAL.SP.PR_ASU_T;
_02c: NOP   0;
      U     L     84.0;
      U     "DB_POWER_SAVING_MODE2".MODE.PR_ASU_HEATING;
      SPBNB _02d;
      L     "DB_POWER_SAVING_MODE2".GENERAL.SP.PR_ASU_WINDOW_T_MIN;
      T     "DB_POWER_SAVING_MODE2".GENERAL.SP.PR_ASU_T;
_02d: NOP   0;
      U     L     84.0;
      UN    "DB_POWER_SAVING_MODE2".MODE.PR_ASU_COOLING;
      UN    "DB_POWER_SAVING_MODE2".MODE.PR_ASU_HEATING;
      SPBNB _02e;
      L     "DB_GRP_81".CLT81.PV.AV;
      T     "DB_POWER_SAVING_MODE2".GENERAL.SP.PR_ASU_T;
_02e: NOP   0;
      U     L     84.0;
      U     "DB_POWER_SAVING_MODE2".MODE.PR_ASU_DEHUMIDIFYING;
      SPBNB _02f;
      L     "DB_POWER_SAVING_MODE2".GENERAL.SP.PR_ASU_WINDOW_H_MAX;
      T     "DB_POWER_SAVING_MODE2".GENERAL.SP.PR_ASU_H;
_02f: NOP   0;
      U     L     84.0;
      U     "DB_POWER_SAVING_MODE2".MODE.PR_ASU_HUMIDIFYING;
      SPBNB _030;
      L     "DB_POWER_SAVING_MODE2".GENERAL.SP.PR_ASU_WINDOW_H_MIN;
      T     "DB_POWER_SAVING_MODE2".GENERAL.SP.PR_ASU_H;
_030: NOP   0;
      U     L     84.0;
      UN    "DB_POWER_SAVING_MODE2".MODE.PR_ASU_DEHUMIDIFYING;
      UN    "DB_POWER_SAVING_MODE2".MODE.PR_ASU_HUMIDIFYING;
      SPBNB _031;
      L     "DB_GRP_81".CLM82_HUM.PV.AV;
      T     "DB_POWER_SAVING_MODE2".GENERAL.SP.PR_ASU_H;
_031: NOP   0;
NETWORK
TITLE =ASU CONDIDITON 1
//OUTSIDE TEMPERATURE < T MIN, OUTSIDE HUMIDITY < H MIN
//
//HEATING ON
//COOLING OFF
//HUMIDIFYING ON
//DEHUMIDIFYING OFF
//UNTIL WINDOW IS REACHED
//
//HEATING SP T MIN
//HUMIDIFYING SP H MIN
      U     "DB_POWER_SAVING_MODE2".CONDITIONS.PR_ASU_C1;
      =     L     84.0;
      U     L     84.0;
      U(    ;
      L     "DB_GRP_81".CLT81.PV.AV;
      L     "DB_POWER_SAVING_MODE2".GENERAL.SP.PR_ASU_WINDOW_T_MIN;
      <R    ;
      )     ;
      S     "DB_POWER_SAVING_MODE2".MODE.PR_ASU_HEATING;
      U     L     84.0;
      U     "DB_POWER_SAVING_MODE2".MODE.PR_ASU_HEATING;
      U     "DB_GRP_81".VA51.SM.Open;
      U(    ;
      L     "DB_GRP_81".PP51.PV.AV;
      L     7.500000e+000;
      <=R   ;
      )     ;
      U(    ;
      L     "DB_GRP_81".CLT81.PV.AV;
      L     #SW_PR_ASU_STOP_HEATING;
      >R    ;
      )     ;
      L     S5T#2M;
      SE    "T_PS_M2_ASU_HEAT_OFF_C1";
      NOP   0;
      NOP   0;
      NOP   0;
      U     "T_PS_M2_ASU_HEAT_OFF_C1";
      R     "DB_POWER_SAVING_MODE2".MODE.PR_ASU_HEATING;
      U     L     84.0;
      BLD   102;
      R     "DB_POWER_SAVING_MODE2".MODE.PR_ASU_COOLING;
      U     L     84.0;
      BLD   102;
      S     "DB_POWER_SAVING_MODE2".MODE.PR_ASU_HUMIDIFYING;
      U     L     84.0;
      BLD   102;
      R     "DB_POWER_SAVING_MODE2".MODE.PR_ASU_DEHUMIDIFYING;
      U     L     84.0;
      U     "DB_POWER_SAVING_MODE2".MODE.PR_ASU_HEATING;
      SPBNB _032;
      L     "DB_POWER_SAVING_MODE2".GENERAL.SP.PR_ASU_WINDOW_T_MIN;
      T     "DB_POWER_SAVING_MODE2".GENERAL.SP.PR_ASU_T;
_032: NOP   0;
      U     L     84.0;
      UN    "DB_POWER_SAVING_MODE2".MODE.PR_ASU_HEATING;
      SPBNB _033;
      L     "DB_GRP_81".CLT81.PV.AV;
      T     "DB_POWER_SAVING_MODE2".GENERAL.SP.PR_ASU_T;
_033: NOP   0;
      U     L     84.0;
      SPBNB _034;
      L     "DB_POWER_SAVING_MODE2".GENERAL.SP.PR_ASU_WINDOW_H_MIN;
      T     "DB_POWER_SAVING_MODE2".GENERAL.SP.PR_ASU_H;
_034: NOP   0;
NETWORK
TITLE =ASU CONDITION 2
//OUTSIDE TEMPERATURE IN WINDOW, OUTSIDE HUMIDITY < H MIN
//
//HEATING ON (ONLY IF TEMPERATURE GOES DOWN BECAUSE OF HUMIDIFYING)
//COOLING OFF
//HUMIDIFYING ON
//DEHUMIDIFIYNG OFF
//UNTIL WINDOW IS REACHED
//
//HEATING SP T MIN
//HUMIDIFYING SP H MIN
      U     "DB_POWER_SAVING_MODE2".CONDITIONS.PR_ASU_C2;
      =     L     84.0;
      U     L     84.0;
      U(    ;
      L     "DB_GRP_81".CLT81.PV.AV;
      L     "DB_POWER_SAVING_MODE2".GENERAL.SP.CR_ASU_WINDOW_T_MIN;
      <R    ;
      )     ;
      S     "DB_POWER_SAVING_MODE2".MODE.PR_ASU_HEATING;
      U     L     84.0;
      U     "DB_POWER_SAVING_MODE2".MODE.PR_ASU_HEATING;
      U     "DB_GRP_81".VA51.SM.Open;
      U(    ;
      L     "DB_GRP_81".PP51.PV.AV;
      L     8.000000e+000;
      <R    ;
      )     ;
      U(    ;
      L     "DB_GRP_81".CLT81.PV.AV;
      L     #SW_PR_ASU_STOP_HEATING;
      >R    ;
      )     ;
      L     S5T#40S;
      SE    "T_PS_M2_ASU_HEAT_OFF_C2";
      NOP   0;
      NOP   0;
      NOP   0;
      U     "T_PS_M2_ASU_HEAT_OFF_C2";
      R     "DB_POWER_SAVING_MODE2".MODE.PR_ASU_HEATING;
      U     L     84.0;
      U(    ;
      L     "DB_GRP_81".CLM82_HUM.PV.AV;
      L     "DB_POWER_SAVING_MODE2".GENERAL.SP.PR_ASU_WINDOW_H_MIN;
      <R    ;
      )     ;
      S     "DB_POWER_SAVING_MODE2".MODE.PR_ASU_HUMIDIFYING;
      U     L     84.0;
      U     "DB_POWER_SAVING_MODE2".MODE.PR_ASU_HUMIDIFYING;
      U(    ;
      L     "DB_GRP_81".CLM82_HUM.PV.AV;
      L     #SW_PR_ASU_STOP_HUM;
      >R    ;
      )     ;
      U(    ;
      L     "DB_GRP_81".PP61.PV.Frq_AV;
      L     7.500000e+000;
      <R    ;
      )     ;
      L     S5T#1M;
      SE    "T_PS_M2_ASU_HUM_OFF_C2";
      NOP   0;
      NOP   0;
      NOP   0;
      U     "T_PS_M2_ASU_HUM_OFF_C2";
      R     "DB_POWER_SAVING_MODE2".MODE.PR_ASU_HUMIDIFYING;
      U     L     84.0;
      BLD   102;
      R     "DB_POWER_SAVING_MODE2".MODE.PR_ASU_DEHUMIDIFYING;
      U     L     84.0;
      BLD   102;
      R     "DB_POWER_SAVING_MODE2".MODE.PR_ASU_COOLING;
      U     L     84.0;
      U     "DB_POWER_SAVING_MODE2".MODE.PR_ASU_HEATING;
      SPBNB _035;
      L     "DB_POWER_SAVING_MODE2".GENERAL.SP.PR_ASU_WINDOW_T_MIN;
      T     "DB_POWER_SAVING_MODE2".GENERAL.SP.PR_ASU_T;
_035: NOP   0;
      U     L     84.0;
      UN    "DB_POWER_SAVING_MODE2".MODE.PR_ASU_HEATING;
      SPBNB _036;
      L     "DB_GRP_81".CLT81.PV.AV;
      T     "DB_POWER_SAVING_MODE2".GENERAL.SP.PR_ASU_T;
_036: NOP   0;
      U     L     84.0;
      U     "DB_POWER_SAVING_MODE2".MODE.PR_ASU_HUMIDIFYING;
      SPBNB _037;
      L     "DB_POWER_SAVING_MODE2".GENERAL.SP.PR_ASU_WINDOW_H_MIN;
      T     "DB_POWER_SAVING_MODE2".GENERAL.SP.PR_ASU_H;
_037: NOP   0;
      U     L     84.0;
      UN    "DB_POWER_SAVING_MODE2".MODE.PR_ASU_HUMIDIFYING;
      SPBNB _038;
      L     "DB_GRP_81".CLM82_HUM.PV.AV;
      T     "DB_POWER_SAVING_MODE2".GENERAL.SP.PR_ASU_H;
_038: NOP   0;
NETWORK
TITLE =ASU CONDITION 3
//OUTSIDE TEMPERATURE > T MAX, OUTSIDE HUMIDITY < H MIN
//
//HEATING ON (ONLY IF TEMPERATURE GOES DOWN BECAUSE OF HUMIDIFYING)
//COOLING ON (IF CONDITIONS ARE NOT REACHED USING ONLY HUMIDIFYING)
//HUMIDIFYING ON
//DEHUMIDIFYING OFF
//UNTIL WINDOW IS REACHED
//
//HEATING SP T MIN (HEATING), T MAX (COOLING),
//HUMIDIFYING SP H MIN
      U     "DB_POWER_SAVING_MODE2".CONDITIONS.PR_ASU_C3;
      =     L     84.0;
      U     L     84.0;
      U     "DB_POWER_SAVING_MODE2".MODE.PR_ASU_HEATING;
      U     "DB_GRP_81".VA51.SM.Open;
      U(    ;
      L     "DB_GRP_81".PP51.PV.AV;
      L     8.000000e+000;
      <R    ;
      )     ;
      U(    ;
      L     "DB_GRP_81".CLT81.PV.AV;
      L     #SW_PR_ASU_STOP_HEATING;
      >R    ;
      )     ;
      L     S5T#40S;
      SE    "T_PS_M2_ASU_HEAT_OFF_C3";
      NOP   0;
      NOP   0;
      NOP   0;
      NOP   0;
      U     L     84.0;
      U(    ;
      O     "DB_POWER_SAVING_MODE2".MODE.PR_ASU_COOLING;
      O     "T_PS_M2_ASU_HEAT_OFF_C3";
      )     ;
      R     "DB_POWER_SAVING_MODE2".MODE.PR_ASU_HEATING;
      U     L     84.0;
      U(    ;
      L     "DB_GRP_81".CLT81.PV.AV;
      L     "DB_POWER_SAVING_MODE2".GENERAL.SP.PR_ASU_WINDOW_T_MIN;
      <R    ;
      )     ;
      S     "DB_POWER_SAVING_MODE2".MODE.PR_ASU_HEATING;
      U     L     84.0;
      U(    ;
      L     "DB_GRP_81".CLM82_HUM.PV.AV;
      L     "DB_POWER_SAVING_MODE2".GENERAL.SP.PR_ASU_WINDOW_H_MIN;
      <R    ;
      )     ;
      S     "DB_POWER_SAVING_MODE2".MODE.PR_ASU_HUMIDIFYING;
      U     L     84.0;
      U     "DB_POWER_SAVING_MODE2".MODE.PR_ASU_HUMIDIFYING;
      U(    ;
      L     "DB_GRP_81".CLM82_HUM.PV.AV;
      L     #SW_PR_ASU_STOP_HUM;
      >R    ;
      )     ;
      U(    ;
      L     "DB_GRP_81".PP61.PV.Frq_AV;
      L     7.500000e+000;
      <R    ;
      )     ;
      L     S5T#1M;
      SE    "T_PS_M2_ASU_HUM_OFF_C3";
      NOP   0;
      NOP   0;
      NOP   0;
      U     "T_PS_M2_ASU_HUM_OFF_C3";
      R     "DB_POWER_SAVING_MODE2".MODE.PR_ASU_HUMIDIFYING;
      U     L     84.0;
      BLD   102;
      R     "DB_POWER_SAVING_MODE2".MODE.PR_ASU_DEHUMIDIFYING;
      U     L     84.0;
      U     "DB_POWER_SAVING_MODE2".MODE.PR_ASU_COOLING;
      U(    ;
      L     "DB_GRP_81".CLT81.PV.AV;
      L     #SW_PR_ASU_STOP_COOLING;
      <R    ;
      )     ;
      L     S5T#2M;
      SE    "T_PS_M2_ASU_COOL_OFF_C3";
      NOP   0;
      NOP   0;
      NOP   0;
      NOP   0;
      U     L     84.0;
      U(    ;
      O     "DB_POWER_SAVING_MODE2".MODE.PR_ASU_HEATING;
      O     "T_PS_M2_ASU_COOL_OFF_C3";
      )     ;
      R     "DB_POWER_SAVING_MODE2".MODE.PR_ASU_COOLING;
      U     L     84.0;
      U(    ;
      U(    ;
      L     "DB_GRP_81".CLM82_HUM.PV.AV;
      L     #SW_PR_ASU_START_COOLING;
      >=R   ;
      )     ;
      U(    ;
      L     "DB_GRP_81".CLT81.PV.AV;
      L     "DB_POWER_SAVING_MODE2".GENERAL.SP.PR_ASU_WINDOW_T_MAX;
      >R    ;
      )     ;
      O     "DB_GRP_81".PP61.SM.GeneralError;
      O     "DB_GRP_81".PP61.SM.ManualMode;
      O     "DB_DIGIT".FM.G81_FIL63_B22_1;
      )     ;
      S     "DB_POWER_SAVING_MODE2".MODE.PR_ASU_COOLING;
      U     L     84.0;
      U     "DB_POWER_SAVING_MODE2".MODE.PR_ASU_HEATING;
      SPBNB _039;
      L     "DB_POWER_SAVING_MODE2".GENERAL.SP.PR_ASU_WINDOW_T_MIN;
      T     "DB_POWER_SAVING_MODE2".GENERAL.SP.PR_ASU_T;
_039: NOP   0;
      U     L     84.0;
      U     "DB_POWER_SAVING_MODE2".MODE.PR_ASU_COOLING;
      SPBNB _03a;
      L     "DB_POWER_SAVING_MODE2".GENERAL.SP.PR_ASU_WINDOW_T_MAX;
      T     "DB_POWER_SAVING_MODE2".GENERAL.SP.PR_ASU_T;
_03a: NOP   0;
      U     L     84.0;
      U     "DB_POWER_SAVING_MODE2".MODE.PR_ASU_HUMIDIFYING;
      SPBNB _03b;
      L     "DB_POWER_SAVING_MODE2".GENERAL.SP.PR_ASU_WINDOW_H_MIN;
      T     "DB_POWER_SAVING_MODE2".GENERAL.SP.PR_ASU_H;
_03b: NOP   0;
      U     L     84.0;
      UN    "DB_POWER_SAVING_MODE2".MODE.PR_ASU_HUMIDIFYING;
      SPBNB _03c;
      L     "DB_GRP_81".CLM82_HUM.PV.AV;
      T     "DB_POWER_SAVING_MODE2".GENERAL.SP.PR_ASU_H;
_03c: NOP   0;
      U     L     84.0;
      UN    "DB_POWER_SAVING_MODE2".MODE.PR_ASU_HEATING;
      UN    "DB_POWER_SAVING_MODE2".MODE.PR_ASU_COOLING;
      SPBNB _03d;
      L     "DB_GRP_81".CLT81.PV.AV;
      T     "DB_POWER_SAVING_MODE2".GENERAL.SP.PR_ASU_T;
_03d: NOP   0;
NETWORK
TITLE =ASU CONDITION 4
//OUTSIDE TEMPERATURE > T MAX, OUTSIDE HUMIDITY IN WINDOW
//
//HEATING OFF
//COOLING ON
//HUMIDIFYING ON (ONLY IF HUMIDITY GOES DOWN BECAUSE OF COOLING)
//DEHUMIDIFYING OFF
//UNTIL WINDOW IS REACHED
//
//COOLING SP T MAX
//HUMIDIFYING SP H MIN
      U     "DB_POWER_SAVING_MODE2".CONDITIONS.PR_ASU_C4;
      =     L     84.0;
      U     L     84.0;
      BLD   102;
      R     "DB_POWER_SAVING_MODE2".MODE.PR_ASU_HEATING;
      U     L     84.0;
      U(    ;
      L     "DB_GRP_81".CLT81.PV.AV;
      L     "DB_POWER_SAVING_MODE2".GENERAL.SP.PR_ASU_WINDOW_T_MAX;
      >R    ;
      )     ;
      S     "DB_POWER_SAVING_MODE2".MODE.PR_ASU_COOLING;
      U     L     84.0;
      U     "DB_POWER_SAVING_MODE2".MODE.PR_ASU_COOLING;
      U     "DB_GRP_81".VA41_M1.SM.Close;
      U     "DB_GRP_81".VA41_M2.SM.Close;
      U(    ;
      L     "DB_GRP_81".CLT81.PV.AV;
      L     #SW_PR_ASU_STOP_COOLING;
      <R    ;
      )     ;
      R     "DB_POWER_SAVING_MODE2".MODE.PR_ASU_COOLING;
      U     L     84.0;
      U(    ;
      L     "DB_GRP_81".CLM82_HUM.PV.AV;
      L     "DB_POWER_SAVING_MODE2".GENERAL.SP.PR_ASU_WINDOW_H_MIN;
      <R    ;
      )     ;
      S     "DB_POWER_SAVING_MODE2".MODE.PR_ASU_HUMIDIFYING;
      U     L     84.0;
      U     "DB_POWER_SAVING_MODE2".MODE.PR_ASU_HUMIDIFYING;
      U(    ;
      L     "DB_GRP_81".CLM82_HUM.PV.AV;
      L     #SW_PR_ASU_STOP_HUM;
      >R    ;
      )     ;
      U(    ;
      L     "DB_GRP_81".PP61.PV.Frq_AV;
      L     7.500000e+000;
      <R    ;
      )     ;
      L     S5T#40S;
      SE    "T_PS_M2_ASU_HUM_OFF_C4";
      NOP   0;
      NOP   0;
      NOP   0;
      U     "T_PS_M2_ASU_HUM_OFF_C4";
      R     "DB_POWER_SAVING_MODE2".MODE.PR_ASU_HUMIDIFYING;
      U     L     84.0;
      BLD   102;
      R     "DB_POWER_SAVING_MODE2".MODE.PR_ASU_DEHUMIDIFYING;
      U     L     84.0;
      U     "DB_POWER_SAVING_MODE2".MODE.PR_ASU_COOLING;
      SPBNB _03e;
      L     "DB_POWER_SAVING_MODE2".GENERAL.SP.PR_ASU_WINDOW_T_MAX;
      T     "DB_POWER_SAVING_MODE2".GENERAL.SP.PR_ASU_T;
_03e: NOP   0;
      U     L     84.0;
      UN    "DB_POWER_SAVING_MODE2".MODE.PR_ASU_COOLING;
      SPBNB _03f;
      L     "DB_GRP_81".CLT81.PV.AV;
      T     "DB_POWER_SAVING_MODE2".GENERAL.SP.PR_ASU_T;
_03f: NOP   0;
      U     L     84.0;
      U     "DB_POWER_SAVING_MODE2".MODE.PR_ASU_HUMIDIFYING;
      SPBNB _040;
      L     "DB_POWER_SAVING_MODE2".GENERAL.SP.PR_ASU_WINDOW_H_MIN;
      T     "DB_POWER_SAVING_MODE2".GENERAL.SP.PR_ASU_H;
_040: NOP   0;
      U     L     84.0;
      UN    "DB_POWER_SAVING_MODE2".MODE.PR_ASU_HUMIDIFYING;
      SPBNB _041;
      L     "DB_GRP_81".CLM82_HUM.PV.AV;
      T     "DB_POWER_SAVING_MODE2".GENERAL.SP.PR_ASU_H;
_041: NOP   0;
NETWORK
TITLE =ASU CONDITION 5
//OUTSIDE TEMPERATURE > T MAX, OUTSIDE HUMIDITY > H MAX
//
//HEATING ON (ONLY IF TEMPERATURE GOES DOWN BECAUSE OF DEHUMIDIFYING)
//COOLING ON (WHEN NO DEHUMIDIFYING)
//HUMIDIFYING ON (ONLY IF HUMIDITY GOES DOWN BECAUSE OF COOLING)
//DEHUMIDIFYING (WHEN NO COOLING)
//UNTIL WINDOW IS REACHED
//
//COOLING SP T MAX
//HEATING SP T MIN
//HUMIDIFYING SP H MIN
//DEHUMIDIFYING SP H MAX
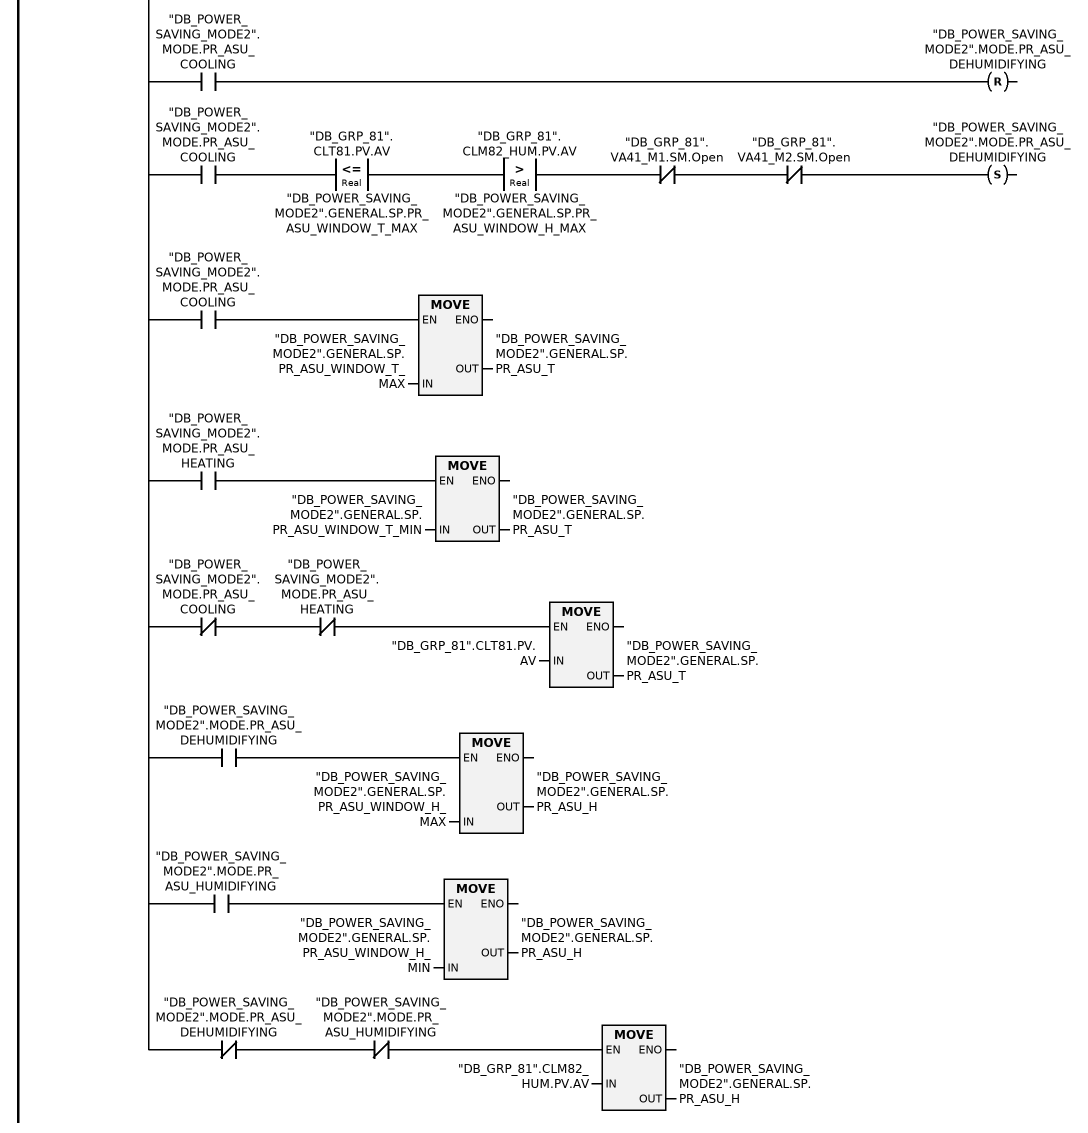
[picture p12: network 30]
      U     "DB_POWER_SAVING_MODE2".CONDITIONS.PR_ASU_C5;
      =     L     84.0;
      U     L     84.0;
      U     "DB_POWER_SAVING_MODE2".MODE.PR_ASU_HEATING;
      U     "DB_GRP_81".VA51.SM.Open;
      U(    ;
      L     "DB_GRP_81".PP51.PV.AV;
      L     8.000000e+000;
      <R    ;
      )     ;
      U(    ;
      L     "DB_GRP_81".CLT81.PV.AV;
      L     #SW_PR_ASU_STOP_HEATING;
      >R    ;
      )     ;
      L     S5T#40S;
      SE    "T_PS_M2_ASU_HEAT_OFF_C5";
      NOP   0;
      NOP   0;
      NOP   0;
      NOP   0;
      U     L     84.0;
      U(    ;
      O     "DB_POWER_SAVING_MODE2".MODE.PR_ASU_COOLING;
      O     "T_PS_M2_ASU_HEAT_OFF_C5";
      )     ;
      R     "DB_POWER_SAVING_MODE2".MODE.PR_ASU_HEATING;
      U     L     84.0;
      UN    "DB_POWER_SAVING_MODE2".MODE.PR_ASU_COOLING;
      U(    ;
      L     "DB_GRP_81".CLT81.PV.AV;
      L     "DB_POWER_SAVING_MODE2".GENERAL.SP.PR_ASU_WINDOW_T_MIN;
      <R    ;
      )     ;
      S     "DB_POWER_SAVING_MODE2".MODE.PR_ASU_HEATING;
      U     L     84.0;
      U     "DB_POWER_SAVING_MODE2".MODE.PR_ASU_DEHUMIDIFYING;
      R     "DB_POWER_SAVING_MODE2".MODE.PR_ASU_COOLING;
      U     L     84.0;
      U(    ;
      U     "DB_POWER_SAVING_MODE2".MODE.PR_ASU_DEHUMIDIFYING;
      U(    ;
      L     "DB_GRP_81".CLM82_HUM.PV.AV;
      L     "DB_POWER_SAVING_MODE2".GENERAL.SP.PR_ASU_WINDOW_H_MAX;
      <=R   ;
      )     ;
      U(    ;
      L     "DB_GRP_81".CLT81.PV.AV;
      L     "DB_POWER_SAVING_MODE2".GENERAL.SP.PR_ASU_WINDOW_T_MAX;
      >R    ;
      )     ;
      UN    "DB_GRP_81".VA41_M1.SM.Open;
      UN    "DB_GRP_81".VA41_M2.SM.Open;
      O     ;
      UN    "DB_POWER_SAVING_MODE2".MODE.PR_ASU_COOLING;
      UN    "DB_POWER_SAVING_MODE2".MODE.PR_ASU_DEHUMIDIFYING;
      )     ;
      S     "DB_POWER_SAVING_MODE2".MODE.PR_ASU_COOLING;
      U     L     84.0;
      U     "DB_POWER_SAVING_MODE2".MODE.PR_ASU_COOLING;
      U(    ;
      L     "DB_GRP_81".CLM82_HUM.PV.AV;
      L     "DB_POWER_SAVING_MODE2".GENERAL.SP.PR_ASU_WINDOW_H_MIN;
      <R    ;
      )     ;
      S     "DB_POWER_SAVING_MODE2".MODE.PR_ASU_HUMIDIFYING;
      U     L     84.0;
      U     "DB_POWER_SAVING_MODE2".MODE.PR_ASU_HUMIDIFYING;
      U(    ;
      L     "DB_GRP_81".CLM82_HUM.PV.AV;
      L     #SW_PR_ASU_STOP_HUM;
      >R    ;
      )     ;
      U(    ;
      L     "DB_GRP_81".PP61.PV.Frq_AV;
      L     7.500000e+000;
      <R    ;
      )     ;
      L     S5T#40S;
      SE    "T_PS_M2_ASU_HUM_OFF_C5";
      NOP   0;
      NOP   0;
      NOP   0;
      NOP   0;
      U     L     84.0;
      U(    ;
      O     "DB_POWER_SAVING_MODE2".MODE.PR_ASU_DEHUMIDIFYING;
      O     "T_PS_M2_ASU_HUM_OFF_C5";
      )     ;
      R     "DB_POWER_SAVING_MODE2".MODE.PR_ASU_HUMIDIFYING;
      U     L     84.0;
      U     "DB_POWER_SAVING_MODE2".MODE.PR_ASU_COOLING;
      R     "DB_POWER_SAVING_MODE2".MODE.PR_ASU_DEHUMIDIFYING;
      U     L     84.0;
      U     "DB_POWER_SAVING_MODE2".MODE.PR_ASU_COOLING;
      U(    ;
      L     "DB_GRP_81".CLT81.PV.AV;
      L     "DB_POWER_SAVING_MODE2".GENERAL.SP.PR_ASU_WINDOW_T_MAX;
      <=R   ;
      )     ;
      U(    ;
      L     "DB_GRP_81".CLM82_HUM.PV.AV;
      L     "DB_POWER_SAVING_MODE2".GENERAL.SP.PR_ASU_WINDOW_H_MAX;
      >R    ;
      )     ;
      UN    "DB_GRP_81".VA41_M1.SM.Open;
      UN    "DB_GRP_81".VA41_M2.SM.Open;
      S     "DB_POWER_SAVING_MODE2".MODE.PR_ASU_DEHUMIDIFYING;
      U     L     84.0;
      U     "DB_POWER_SAVING_MODE2".MODE.PR_ASU_COOLING;
      SPBNB _042;
      L     "DB_POWER_SAVING_MODE2".GENERAL.SP.PR_ASU_WINDOW_T_MAX;
      T     "DB_POWER_SAVING_MODE2".GENERAL.SP.PR_ASU_T;
_042: NOP   0;
      U     L     84.0;
      U     "DB_POWER_SAVING_MODE2".MODE.PR_ASU_HEATING;
      SPBNB _043;
      L     "DB_POWER_SAVING_MODE2".GENERAL.SP.PR_ASU_WINDOW_T_MIN;
      T     "DB_POWER_SAVING_MODE2".GENERAL.SP.PR_ASU_T;
_043: NOP   0;
      U     L     84.0;
      UN    "DB_POWER_SAVING_MODE2".MODE.PR_ASU_COOLING;
      UN    "DB_POWER_SAVING_MODE2".MODE.PR_ASU_HEATING;
      SPBNB _044;
      L     "DB_GRP_81".CLT81.PV.AV;
      T     "DB_POWER_SAVING_MODE2".GENERAL.SP.PR_ASU_T;
_044: NOP   0;
      U     L     84.0;
      U     "DB_POWER_SAVING_MODE2".MODE.PR_ASU_DEHUMIDIFYING;
      SPBNB _045;
      L     "DB_POWER_SAVING_MODE2".GENERAL.SP.PR_ASU_WINDOW_H_MAX;
      T     "DB_POWER_SAVING_MODE2".GENERAL.SP.PR_ASU_H;
_045: NOP   0;
      U     L     84.0;
      U     "DB_POWER_SAVING_MODE2".MODE.PR_ASU_HUMIDIFYING;
      SPBNB _046;
      L     "DB_POWER_SAVING_MODE2".GENERAL.SP.PR_ASU_WINDOW_H_MIN;
      T     "DB_POWER_SAVING_MODE2".GENERAL.SP.PR_ASU_H;
_046: NOP   0;
      U     L     84.0;
      UN    "DB_POWER_SAVING_MODE2".MODE.PR_ASU_DEHUMIDIFYING;
      UN    "DB_POWER_SAVING_MODE2".MODE.PR_ASU_HUMIDIFYING;
      SPBNB _047;
      L     "DB_GRP_81".CLM82_HUM.PV.AV;
      T     "DB_POWER_SAVING_MODE2".GENERAL.SP.PR_ASU_H;
_047: NOP   0;
NETWORK
TITLE =ASU CONDITION 6
//OUTSIDE TEMPERATURE IN WINDOW, OUTSIDE HUMIDITY > H MAX
//
//HEATING ON (ONLY IF TEMPERATURE GOES DOWN WHILE DEHUMIDIFYING)
//COOLING ON (ONLY IF TEMPERATURE GOES OUT OF WINDOW)
//HUMIDIFYING OFF
//DEHUMIDIFYING ON
//UNTIL WINDOW IS REACHED
//
//HEATING SP T MIN
//DEHUMIDIFYING SP H MAX
      U     "DB_POWER_SAVING_MODE2".CONDITIONS.PR_ASU_C6;
      =     L     84.0;
      U     L     84.0;
      U(    ;
      L     "DB_GRP_81".CLT81.PV.AV;
      L     "DB_POWER_SAVING_MODE2".GENERAL.SP.CR_ASU_WINDOW_T_MIN;
      <R    ;
      )     ;
      S     "DB_POWER_SAVING_MODE2".MODE.PR_ASU_HEATING;
      U     L     84.0;
      U     "DB_POWER_SAVING_MODE2".MODE.PR_ASU_HEATING;
      U     "DB_GRP_81".VA51.SM.Open;
      U(    ;
      L     "DB_GRP_81".PP51.PV.AV;
      L     7.500000e+000;
      <=R   ;
      )     ;
      U(    ;
      L     "DB_GRP_81".CLT81.PV.AV;
      L     #SW_PR_ASU_STOP_HEATING;
      >R    ;
      )     ;
      L     S5T#40S;
      SE    "T_PS_M2_ASU_HEAT_OFF_C6";
      NOP   0;
      NOP   0;
      NOP   0;
      U     "T_PS_M2_ASU_HEAT_OFF_C6";
      R     "DB_POWER_SAVING_MODE2".MODE.PR_ASU_HEATING;
      U     L     84.0;
      U(    ;
      L     "DB_GRP_81".CLT81.PV.AV;
      L     "DB_POWER_SAVING_MODE2".GENERAL.SP.PR_ASU_WINDOW_T_MAX;
      >R    ;
      )     ;
      S     "DB_POWER_SAVING_MODE2".MODE.PR_ASU_COOLING;
      U     L     84.0;
      U     "DB_POWER_SAVING_MODE2".MODE.PR_ASU_COOLING;
      U     "DB_GRP_81".VA41_M1.SM.Close;
      U     "DB_GRP_81".VA41_M2.SM.Close;
      U(    ;
      L     "DB_GRP_81".CLT81.PV.AV;
      L     #SW_PR_ASU_STOP_COOLING;
      <R    ;
      )     ;
      R     "DB_POWER_SAVING_MODE2".MODE.PR_ASU_COOLING;
      U     L     84.0;
      BLD   102;
      R     "DB_POWER_SAVING_MODE2".MODE.PR_ASU_HUMIDIFYING;
      U     L     84.0;
      U(    ;
      L     "DB_GRP_81".CLM82_HUM.PV.AV;
      L     "DB_POWER_SAVING_MODE2".GENERAL.SP.PR_ASU_WINDOW_H_MAX;
      >R    ;
      )     ;
      S     "DB_POWER_SAVING_MODE2".MODE.PR_ASU_DEHUMIDIFYING;
      U     L     84.0;
      U     "DB_POWER_SAVING_MODE2".MODE.PR_ASU_DEHUMIDIFYING;
      U(    ;
      L     "DB_GRP_81".CLM82_HUM.PV.AV;
      L     #SW_PR_ASU_STOP_DEHUM;
      <R    ;
      )     ;
      L     S5T#40S;
      SE    "T_PS_M2_ASU_DEHUM_OFF_C6";
      NOP   0;
      NOP   0;
      NOP   0;
      U     "T_PS_M2_ASU_DEHUM_OFF_C6";
      R     "DB_POWER_SAVING_MODE2".MODE.PR_ASU_DEHUMIDIFYING;
      U     L     84.0;
      U     "DB_POWER_SAVING_MODE2".MODE.PR_ASU_HEATING;
      SPBNB _048;
      L     "DB_POWER_SAVING_MODE2".GENERAL.SP.PR_ASU_WINDOW_T_MIN;
      T     "DB_POWER_SAVING_MODE2".GENERAL.SP.PR_ASU_T;
_048: NOP   0;
      U     L     84.0;
      U     "DB_POWER_SAVING_MODE2".MODE.PR_ASU_COOLING;
      SPBNB _049;
      L     "DB_POWER_SAVING_MODE2".GENERAL.SP.PR_ASU_WINDOW_T_MAX;
      T     "DB_POWER_SAVING_MODE2".GENERAL.SP.PR_ASU_T;
_049: NOP   0;
      U     L     84.0;
      UN    "DB_POWER_SAVING_MODE2".MODE.PR_ASU_HEATING;
      UN    "DB_POWER_SAVING_MODE2".MODE.PR_ASU_COOLING;
      SPBNB _04a;
      L     "DB_GRP_81".CLT81.PV.AV;
      T     "DB_POWER_SAVING_MODE2".GENERAL.SP.PR_ASU_T;
_04a: NOP   0;
      U     L     84.0;
      U     "DB_POWER_SAVING_MODE2".MODE.PR_ASU_DEHUMIDIFYING;
      SPBNB _04b;
      L     "DB_POWER_SAVING_MODE2".GENERAL.SP.PR_ASU_WINDOW_H_MAX;
      T     "DB_POWER_SAVING_MODE2".GENERAL.SP.PR_ASU_H;
_04b: NOP   0;
      U     L     84.0;
      UN    "DB_POWER_SAVING_MODE2".MODE.PR_ASU_DEHUMIDIFYING;
      SPBNB _04c;
      L     "DB_GRP_81".CLM82_HUM.PV.AV;
      T     "DB_POWER_SAVING_MODE2".GENERAL.SP.PR_ASU_H;
_04c: NOP   0;
NETWORK
TITLE =ASU CONDITION 7
//OUTSIDE TEMPERATURE < T MIN, OUTSIDE HUMIDITY > H MAX
//
//HEATING ON
//COOLING OFF
//HUMIDIFYING ON (ONLY IF HUMIDITY GOES DOWN BECAUSE OF DEHUMIDIFYING)
//DEHUMIDIFYING ON
//UNTIL WINDOW IS REACHED
//
//HEATING SP T MIN
//DEHUMIDIFYING SP H MAX
      U     "DB_POWER_SAVING_MODE2".CONDITIONS.PR_ASU_C7;
      =     L     84.0;
      U     L     84.0;
      U(    ;
      L     "DB_GRP_81".CLT81.PV.AV;
      L     "DB_POWER_SAVING_MODE2".GENERAL.SP.PR_ASU_WINDOW_T_MIN;
      <R    ;
      )     ;
      S     "DB_POWER_SAVING_MODE2".MODE.PR_ASU_HEATING;
      U     L     84.0;
      U     "DB_POWER_SAVING_MODE2".MODE.PR_ASU_HEATING;
      U     "DB_GRP_81".VA51.SM.Open;
      U(    ;
      L     "DB_GRP_81".PP51.PV.AV;
      L     7.500000e+000;
      <=R   ;
      )     ;
      U(    ;
      L     "DB_GRP_81".CLT81.PV.AV;
      L     #SW_PR_ASU_STOP_HEATING;
      >R    ;
      )     ;
      L     S5T#2M;
      SE    "T_PS_M2_ASU_HEAT_OFF_C7";
      NOP   0;
      NOP   0;
      NOP   0;
      U     "T_PS_M2_ASU_HEAT_OFF_C7";
      R     "DB_POWER_SAVING_MODE2".MODE.PR_ASU_HEATING;
      U     L     84.0;
      BLD   102;
      R     "DB_POWER_SAVING_MODE2".MODE.PR_ASU_COOLING;
      U     L     84.0;
      U(    ;
      L     "DB_GRP_81".CLM82_HUM.PV.AV;
      L     #SW_PR_ASU_STOP_HUM;
      >R    ;
      )     ;
      U(    ;
      L     "DB_GRP_81".PP61.PV.Frq_AV;
      L     7.500000e+000;
      <R    ;
      )     ;
      L     S5T#40S;
      SE    "T_PS_M2_ASU_HUM_OFF_C7";
      NOP   0;
      NOP   0;
      NOP   0;
      NOP   0;
      U     L     84.0;
      U(    ;
      O     "DB_POWER_SAVING_MODE2".MODE.PR_ASU_DEHUMIDIFYING;
      O     "T_PS_M2_ASU_HUM_OFF_C7";
      )     ;
      R     "DB_POWER_SAVING_MODE2".MODE.PR_ASU_HUMIDIFYING;
      U     L     84.0;
      U(    ;
      L     "DB_GRP_81".CLM82_HUM.PV.AV;
      L     "DB_POWER_SAVING_MODE2".GENERAL.SP.PR_ASU_WINDOW_H_MAX;
      >R    ;
      )     ;
      S     "DB_POWER_SAVING_MODE2".MODE.PR_ASU_HUMIDIFYING;
      U     L     84.0;
      U     "DB_POWER_SAVING_MODE2".MODE.PR_ASU_DEHUMIDIFYING;
      U(    ;
      L     "DB_GRP_81".CLM82_HUM.PV.AV;
      L     #SW_PR_ASU_STOP_DEHUM;
      <R    ;
      )     ;
      L     S5T#1M;
      SE    "T_PS_M2_ASU_DEHUM_OFF_C7";
      NOP   0;
      NOP   0;
      NOP   0;
      NOP   0;
      U     L     84.0;
      U(    ;
      O     "DB_POWER_SAVING_MODE2".MODE.PR_ASU_HUMIDIFYING;
      O     "T_PS_M2_ASU_DEHUM_OFF_C7";
      )     ;
      R     "DB_POWER_SAVING_MODE2".MODE.PR_ASU_DEHUMIDIFYING;
      U     L     84.0;
      U(    ;
      L     "DB_GRP_81".CLM82_HUM.PV.AV;
      L     "DB_POWER_SAVING_MODE2".GENERAL.SP.PR_ASU_WINDOW_H_MAX;
      >R    ;
      )     ;
      S     "DB_POWER_SAVING_MODE2".MODE.PR_ASU_DEHUMIDIFYING;
      U     L     84.0;
      U     "DB_POWER_SAVING_MODE2".MODE.PR_ASU_HEATING;
      SPBNB _04d;
      L     "DB_POWER_SAVING_MODE2".GENERAL.SP.PR_ASU_WINDOW_T_MIN;
      T     "DB_POWER_SAVING_MODE2".GENERAL.SP.PR_ASU_T;
_04d: NOP   0;
      U     L     84.0;
      UN    "DB_POWER_SAVING_MODE2".MODE.PR_ASU_HEATING;
      SPBNB _04e;
      L     "DB_GRP_81".CLT81.PV.AV;
      T     "DB_POWER_SAVING_MODE2".GENERAL.SP.PR_ASU_T;
_04e: NOP   0;
      U     L     84.0;
      U     "DB_POWER_SAVING_MODE2".MODE.PR_ASU_DEHUMIDIFYING;
      SPBNB _04f;
      L     "DB_POWER_SAVING_MODE2".GENERAL.SP.PR_ASU_WINDOW_H_MAX;
      T     "DB_POWER_SAVING_MODE2".GENERAL.SP.PR_ASU_H;
_04f: NOP   0;
      U     L     84.0;
      U     "DB_POWER_SAVING_MODE2".MODE.PR_ASU_HUMIDIFYING;
      SPBNB _050;
      L     "DB_POWER_SAVING_MODE2".GENERAL.SP.PR_ASU_WINDOW_H_MIN;
      T     "DB_POWER_SAVING_MODE2".GENERAL.SP.PR_ASU_H;
_050: NOP   0;
      U     L     84.0;
      UN    "DB_POWER_SAVING_MODE2".MODE.PR_ASU_DEHUMIDIFYING;
      UN    "DB_POWER_SAVING_MODE2".MODE.PR_ASU_HUMIDIFYING;
      SPBNB _051;
      L     "DB_GRP_81".CLM82_HUM.PV.AV;
      T     "DB_POWER_SAVING_MODE2".GENERAL.SP.PR_ASU_H;
_051: NOP   0;
NETWORK
TITLE =ASU CONDITION 8
//OUTSIDE TEMPERATURE < T MIN, OUTSIDE HUMIDITY IN WINDOW
//
//HEATING ON
//COOLING OFF
//HUMIDIFYING (ONLY IF HUMIDITY GOES DOWN BECAUSE OF HEATING)
//DEHUMIDIFYING OFF
//UNTIL WINDOW IS REACHED
//
//HEATING SP T MIN
//HUMIDIFYING SP H MIN
//DEHUMIDIFYING SP H MAX
      U     "DB_POWER_SAVING_MODE2".CONDITIONS.PR_ASU_C8;
      =     L     84.0;
      U     L     84.0;
      U(    ;
      L     "DB_GRP_81".CLT81.PV.AV;
      L     "DB_POWER_SAVING_MODE2".GENERAL.SP.PR_ASU_WINDOW_T_MIN;
      <R    ;
      )     ;
      S     "DB_POWER_SAVING_MODE2".MODE.PR_ASU_HEATING;
      U     L     84.0;
      U     "DB_POWER_SAVING_MODE2".MODE.PR_ASU_HEATING;
      U     "DB_GRP_81".VA51.SM.Open;
      U(    ;
      L     "DB_GRP_81".PP51.PV.AV;
      L     7.500000e+000;
      <=R   ;
      )     ;
      U(    ;
      L     "DB_GRP_81".CLT81.PV.AV;
      L     #SW_PR_ASU_STOP_HEATING;
      >R    ;
      )     ;
      L     S5T#2M;
      SE    "T_PS_M2_ASU_HEAT_OFF_C8";
      NOP   0;
      NOP   0;
      NOP   0;
      U     "T_PS_M2_ASU_HEAT_OFF_C8";
      R     "DB_POWER_SAVING_MODE2".MODE.PR_ASU_HEATING;
      U     L     84.0;
      BLD   102;
      R     "DB_POWER_SAVING_MODE2".MODE.PR_ASU_COOLING;
      U     L     84.0;
      U(    ;
      L     "DB_GRP_81".CLM82_HUM.PV.AV;
      L     "DB_POWER_SAVING_MODE2".GENERAL.SP.PR_ASU_WINDOW_H_MIN;
      <R    ;
      )     ;
      S     "DB_POWER_SAVING_MODE2".MODE.PR_ASU_HUMIDIFYING;
      U     L     84.0;
      U     "DB_POWER_SAVING_MODE2".MODE.PR_ASU_HUMIDIFYING;
      U(    ;
      L     "DB_GRP_81".CLM82_HUM.PV.AV;
      L     #SW_PR_ASU_STOP_HUM;
      >R    ;
      )     ;
      U(    ;
      L     "DB_GRP_81".PP61.PV.Frq_AV;
      L     7.500000e+000;
      <R    ;
      )     ;
      L     S5T#40S;
      SE    "T_PS_M2_ASU_HUM_OFF_C8";
      NOP   0;
      NOP   0;
      NOP   0;
      U     "T_PS_M2_ASU_HUM_OFF_C8";
      R     "DB_POWER_SAVING_MODE2".MODE.PR_ASU_HUMIDIFYING;
      U     L     84.0;
      BLD   102;
      R     "DB_POWER_SAVING_MODE2".MODE.PR_ASU_DEHUMIDIFYING;
      U     L     84.0;
      U     "DB_POWER_SAVING_MODE2".MODE.PR_ASU_HEATING;
      SPBNB _052;
      L     "DB_POWER_SAVING_MODE2".GENERAL.SP.PR_ASU_WINDOW_T_MIN;
      T     "DB_POWER_SAVING_MODE2".GENERAL.SP.PR_ASU_T;
_052: NOP   0;
      U     L     84.0;
      UN    "DB_POWER_SAVING_MODE2".MODE.PR_ASU_HEATING;
      SPBNB _053;
      L     "DB_GRP_81".CLT81.PV.AV;
      T     "DB_POWER_SAVING_MODE2".GENERAL.SP.PR_ASU_T;
_053: NOP   0;
      U     L     84.0;
      U     "DB_POWER_SAVING_MODE2".MODE.PR_ASU_HUMIDIFYING;
      SPBNB _054;
      L     "DB_POWER_SAVING_MODE2".GENERAL.SP.PR_ASU_WINDOW_H_MIN;
      T     "DB_POWER_SAVING_MODE2".GENERAL.SP.PR_ASU_H;
_054: NOP   0;
      U     L     84.0;
      UN    "DB_POWER_SAVING_MODE2".MODE.PR_ASU_HUMIDIFYING;
      SPBNB _055;
      L     "DB_GRP_81".CLM82_HUM.PV.AV;
      T     "DB_POWER_SAVING_MODE2".GENERAL.SP.PR_ASU_H;
_055: NOP   0;
NETWORK
TITLE =ARU OUTSIDE CONDITIONS

      U     "DB_POWER_SAVING_MODE2".GENERAL.SM.PR_MODE_2_ON;
      U(    ;
      U     "DB_PROG".PRIMER.SM.ON;
      UN    "DB_PROG".PRIMER.SM.START;
      O     ;
      UN    "DB_PROG".PRIMER.SM.ON;
      U     "DB_PROG".PRIMER.SM.STOP;
      UN    "PR_STOP_PROD_FANS";
      )     ;
      =     L     84.0;
      U     L     84.0;
      U(    ;
      L     "DB_POWER_SAVING_MODE2".GENERAL.PV.AVG_TEMP;
      L     "DB_POWER_SAVING_MODE2".GENERAL.SP.PR_ARU_WINDOW_T_MIN;
      >=R   ;
      )     ;
      U(    ;
      L     "DB_POWER_SAVING_MODE2".GENERAL.PV.AVG_TEMP;
      L     "DB_POWER_SAVING_MODE2".GENERAL.SP.PR_ARU_WINDOW_T_MAX;
      <=R   ;
      )     ;
      =     L     84.1;
      U     L     84.1;
      U(    ;
      L     "DB_POWER_SAVING_MODE2".GENERAL.PV.AVG_HUM;
      L     "DB_POWER_SAVING_MODE2".GENERAL.SP.PR_ARU_WINDOW_H_MIN;
      >=R   ;
      )     ;
      U(    ;
      L     "DB_POWER_SAVING_MODE2".GENERAL.PV.AVG_HUM;
      L     "DB_POWER_SAVING_MODE2".GENERAL.SP.PR_ARU_WINDOW_H_MAX;
      <=R   ;
      )     ;
      =     "DB_POWER_SAVING_MODE2".CONDITIONS.PR_ARU_C0;
      U     L     84.1;
      U(    ;
      L     "DB_POWER_SAVING_MODE2".GENERAL.PV.AVG_HUM;
      L     "DB_POWER_SAVING_MODE2".GENERAL.SP.PR_ARU_WINDOW_H_MIN;
      <R    ;
      )     ;
      =     "DB_POWER_SAVING_MODE2".CONDITIONS.PR_ARU_C2;
      U     L     84.1;
      U(    ;
      L     "DB_POWER_SAVING_MODE2".GENERAL.PV.AVG_HUM;
      L     "DB_POWER_SAVING_MODE2".GENERAL.SP.PR_ARU_WINDOW_H_MAX;
      >R    ;
      )     ;
      =     "DB_POWER_SAVING_MODE2".CONDITIONS.PR_ARU_C6;
      U     L     84.0;
      U(    ;
      L     "DB_POWER_SAVING_MODE2".GENERAL.PV.AVG_HUM;
      L     "DB_POWER_SAVING_MODE2".GENERAL.SP.PR_ARU_WINDOW_H_MIN;
      >=R   ;
      )     ;
      U(    ;
      L     "DB_POWER_SAVING_MODE2".GENERAL.PV.AVG_HUM;
      L     "DB_POWER_SAVING_MODE2".GENERAL.SP.PR_ARU_WINDOW_H_MAX;
      <=R   ;
      )     ;
      =     L     84.1;
      U     L     84.1;
      U(    ;
      L     "DB_POWER_SAVING_MODE2".GENERAL.PV.AVG_TEMP;
      L     "DB_POWER_SAVING_MODE2".GENERAL.SP.PR_ARU_WINDOW_T_MIN;
      <R    ;
      )     ;
      =     "DB_POWER_SAVING_MODE2".CONDITIONS.PR_ARU_C8;
      U     L     84.1;
      U(    ;
      L     "DB_POWER_SAVING_MODE2".GENERAL.PV.AVG_TEMP;
      L     "DB_POWER_SAVING_MODE2".GENERAL.SP.PR_ARU_WINDOW_T_MAX;
      >R    ;
      )     ;
      =     "DB_POWER_SAVING_MODE2".CONDITIONS.PR_ARU_C4;
      U     L     84.0;
      U(    ;
      L     "DB_POWER_SAVING_MODE2".GENERAL.PV.AVG_TEMP;
      L     "DB_POWER_SAVING_MODE2".GENERAL.SP.PR_ARU_WINDOW_T_MIN;
      <R    ;
      )     ;
      =     L     84.1;
      U     L     84.1;
      U(    ;
      L     "DB_POWER_SAVING_MODE2".GENERAL.PV.AVG_HUM;
      L     "DB_POWER_SAVING_MODE2".GENERAL.SP.PR_ARU_WINDOW_H_MIN;
      <R    ;
      )     ;
      =     "DB_POWER_SAVING_MODE2".CONDITIONS.PR_ARU_C1;
      U     L     84.1;
      U(    ;
      L     "DB_POWER_SAVING_MODE2".GENERAL.PV.AVG_HUM;
      L     "DB_POWER_SAVING_MODE2".GENERAL.SP.PR_ARU_WINDOW_H_MAX;
      >R    ;
      )     ;
      =     "DB_POWER_SAVING_MODE2".CONDITIONS.PR_ARU_C7;
      U     L     84.0;
      U(    ;
      L     "DB_POWER_SAVING_MODE2".GENERAL.PV.AVG_TEMP;
      L     "DB_POWER_SAVING_MODE2".GENERAL.SP.PR_ARU_WINDOW_T_MAX;
      >R    ;
      )     ;
      =     L     84.1;
      U     L     84.1;
      U(    ;
      L     "DB_POWER_SAVING_MODE2".GENERAL.PV.AVG_HUM;
      L     "DB_POWER_SAVING_MODE2".GENERAL.SP.PR_ARU_WINDOW_H_MIN;
      <R    ;
      )     ;
      =     "DB_POWER_SAVING_MODE2".CONDITIONS.PR_ARU_C3;
      U     L     84.1;
      U(    ;
      L     "DB_POWER_SAVING_MODE2".GENERAL.PV.AVG_HUM;
      L     "DB_POWER_SAVING_MODE2".GENERAL.SP.PR_ARU_WINDOW_H_MAX;
      >R    ;
      )     ;
      =     "DB_POWER_SAVING_MODE2".CONDITIONS.PR_ARU_C5;
      U     L     84.0;
      NOT   ;
      R     "DB_POWER_SAVING_MODE2".MODE.PR_ARU_COOLING;
      R     "DB_POWER_SAVING_MODE2".MODE.PR_ARU_DEHUMIDIFYING;
NETWORK
TITLE =ARU SWITCHING POINTS

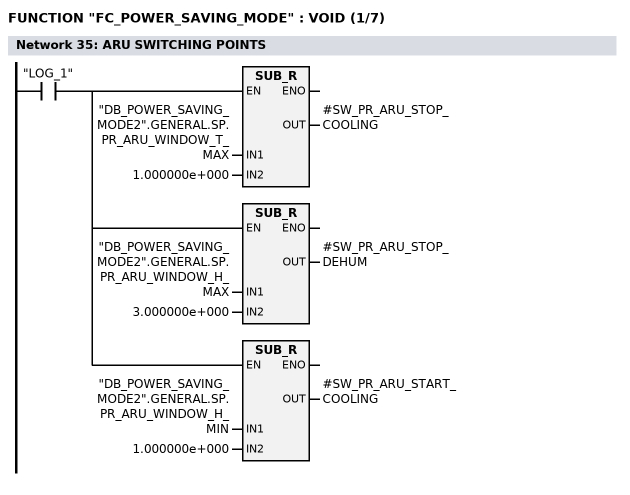
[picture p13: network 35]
      U     "LOG_1";
      =     L     84.0;
      U     L     84.0;
      SPBNB _056;
      L     "DB_POWER_SAVING_MODE2".GENERAL.SP.PR_ARU_WINDOW_T_MAX;
      L     1.000000e+000;
      -R    ;
      T     #SW_PR_ARU_STOP_COOLING;
_056: NOP   0;
      U     L     84.0;
      SPBNB _057;
      L     "DB_POWER_SAVING_MODE2".GENERAL.SP.PR_ARU_WINDOW_H_MAX;
      L     3.000000e+000;
      -R    ;
      T     #SW_PR_ARU_STOP_DEHUM;
_057: NOP   0;
      U     L     84.0;
      SPBNB _058;
      L     "DB_POWER_SAVING_MODE2".GENERAL.SP.PR_ARU_WINDOW_H_MIN;
      L     1.000000e+000;
      -R    ;
      T     #SW_PR_ARU_START_COOLING;
_058: NOP   0;
NETWORK
TITLE =ARU CONDITION 0
//OUTSIDE TEMP. AND HUMIDITY IN WINDOW
//
//COOLING OFF
//DEHUMIDIFYING OFF
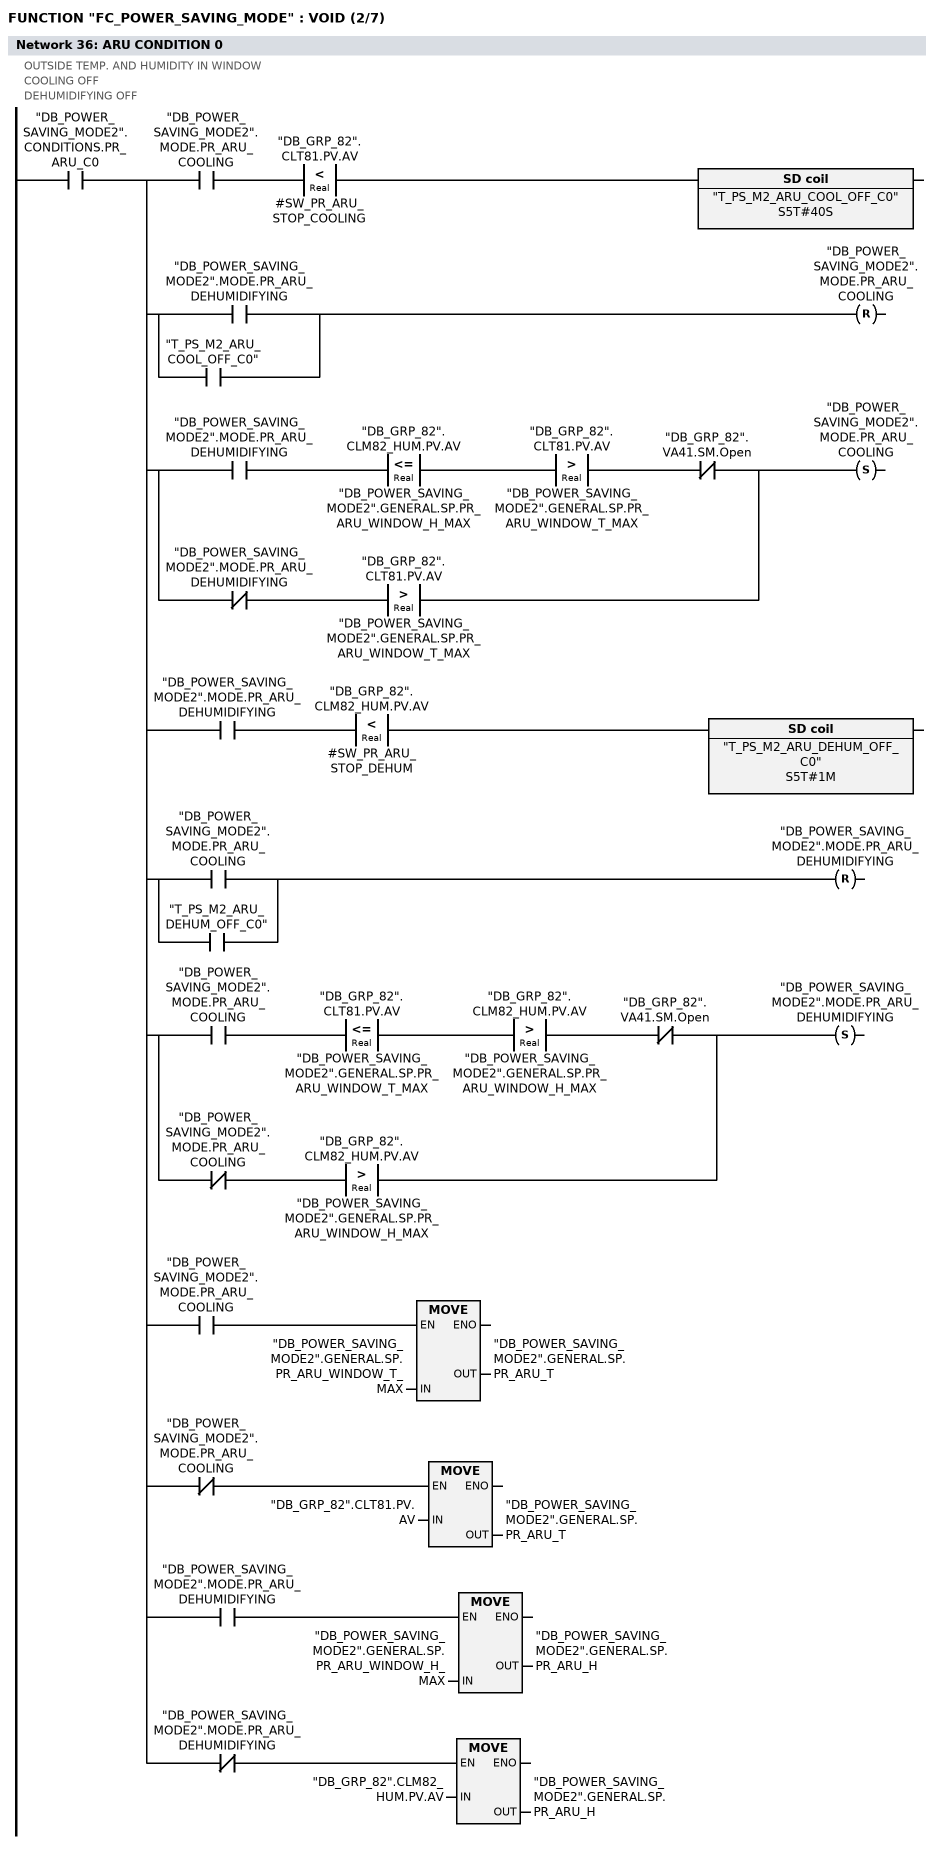
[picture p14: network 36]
      U     "DB_POWER_SAVING_MODE2".CONDITIONS.PR_ARU_C0;
      =     L     84.0;
      U     L     84.0;
      U     "DB_POWER_SAVING_MODE2".MODE.PR_ARU_COOLING;
      U(    ;
      L     "DB_GRP_82".CLT81.PV.AV;
      L     #SW_PR_ARU_STOP_COOLING;
      <R    ;
      )     ;
      L     S5T#40S;
      SE    "T_PS_M2_ARU_COOL_OFF_C0";
      NOP   0;
      NOP   0;
      NOP   0;
      NOP   0;
      U     L     84.0;
      U(    ;
      O     "DB_POWER_SAVING_MODE2".MODE.PR_ARU_DEHUMIDIFYING;
      O     "T_PS_M2_ARU_COOL_OFF_C0";
      )     ;
      R     "DB_POWER_SAVING_MODE2".MODE.PR_ARU_COOLING;
      U     L     84.0;
      U(    ;
      U     "DB_POWER_SAVING_MODE2".MODE.PR_ARU_DEHUMIDIFYING;
      U(    ;
      L     "DB_GRP_82".CLM82_HUM.PV.AV;
      L     "DB_POWER_SAVING_MODE2".GENERAL.SP.PR_ARU_WINDOW_H_MAX;
      <=R   ;
      )     ;
      U(    ;
      L     "DB_GRP_82".CLT81.PV.AV;
      L     "DB_POWER_SAVING_MODE2".GENERAL.SP.PR_ARU_WINDOW_T_MAX;
      >R    ;
      )     ;
      UN    "DB_GRP_82".VA41.SM.Open;
      O     ;
      UN    "DB_POWER_SAVING_MODE2".MODE.PR_ARU_DEHUMIDIFYING;
      U(    ;
      L     "DB_GRP_82".CLT81.PV.AV;
      L     "DB_POWER_SAVING_MODE2".GENERAL.SP.PR_ARU_WINDOW_T_MAX;
      >R    ;
      )     ;
      )     ;
      S     "DB_POWER_SAVING_MODE2".MODE.PR_ARU_COOLING;
      U     L     84.0;
      U     "DB_POWER_SAVING_MODE2".MODE.PR_ARU_DEHUMIDIFYING;
      U(    ;
      L     "DB_GRP_82".CLM82_HUM.PV.AV;
      L     #SW_PR_ARU_STOP_DEHUM;
      <R    ;
      )     ;
      L     S5T#1M;
      SE    "T_PS_M2_ARU_DEHUM_OFF_C0";
      NOP   0;
      NOP   0;
      NOP   0;
      NOP   0;
      U     L     84.0;
      U(    ;
      O     "DB_POWER_SAVING_MODE2".MODE.PR_ARU_COOLING;
      O     "T_PS_M2_ARU_DEHUM_OFF_C0";
      )     ;
      R     "DB_POWER_SAVING_MODE2".MODE.PR_ARU_DEHUMIDIFYING;
      U     L     84.0;
      U(    ;
      U     "DB_POWER_SAVING_MODE2".MODE.PR_ARU_COOLING;
      U(    ;
      L     "DB_GRP_82".CLT81.PV.AV;
      L     "DB_POWER_SAVING_MODE2".GENERAL.SP.PR_ARU_WINDOW_T_MAX;
      <=R   ;
      )     ;
      U(    ;
      L     "DB_GRP_82".CLM82_HUM.PV.AV;
      L     "DB_POWER_SAVING_MODE2".GENERAL.SP.PR_ARU_WINDOW_H_MAX;
      >R    ;
      )     ;
      UN    "DB_GRP_82".VA41.SM.Open;
      O     ;
      UN    "DB_POWER_SAVING_MODE2".MODE.PR_ARU_COOLING;
      U(    ;
      L     "DB_GRP_82".CLM82_HUM.PV.AV;
      L     "DB_POWER_SAVING_MODE2".GENERAL.SP.PR_ARU_WINDOW_H_MAX;
      >R    ;
      )     ;
      )     ;
      S     "DB_POWER_SAVING_MODE2".MODE.PR_ARU_DEHUMIDIFYING;
      U     L     84.0;
      U     "DB_POWER_SAVING_MODE2".MODE.PR_ARU_COOLING;
      SPBNB _059;
      L     "DB_POWER_SAVING_MODE2".GENERAL.SP.PR_ARU_WINDOW_T_MAX;
      T     "DB_POWER_SAVING_MODE2".GENERAL.SP.PR_ARU_T;
_059: NOP   0;
      U     L     84.0;
      UN    "DB_POWER_SAVING_MODE2".MODE.PR_ARU_COOLING;
      SPBNB _05a;
      L     "DB_GRP_82".CLT81.PV.AV;
      T     "DB_POWER_SAVING_MODE2".GENERAL.SP.PR_ARU_T;
_05a: NOP   0;
      U     L     84.0;
      U     "DB_POWER_SAVING_MODE2".MODE.PR_ARU_DEHUMIDIFYING;
      SPBNB _05b;
      L     "DB_POWER_SAVING_MODE2".GENERAL.SP.PR_ARU_WINDOW_H_MAX;
      T     "DB_POWER_SAVING_MODE2".GENERAL.SP.PR_ARU_H;
_05b: NOP   0;
      U     L     84.0;
      UN    "DB_POWER_SAVING_MODE2".MODE.PR_ARU_DEHUMIDIFYING;
      SPBNB _05c;
      L     "DB_GRP_82".CLM82_HUM.PV.AV;
      T     "DB_POWER_SAVING_MODE2".GENERAL.SP.PR_ARU_H;
_05c: NOP   0;
NETWORK
TITLE =ARU CONDIDITON 1
//OUTSIDE TEMPERATURE < T MIN, OUTSIDE HUMIDITY < H MIN
//
//COOLING OFF
//DEHUMIDIFYING OFF
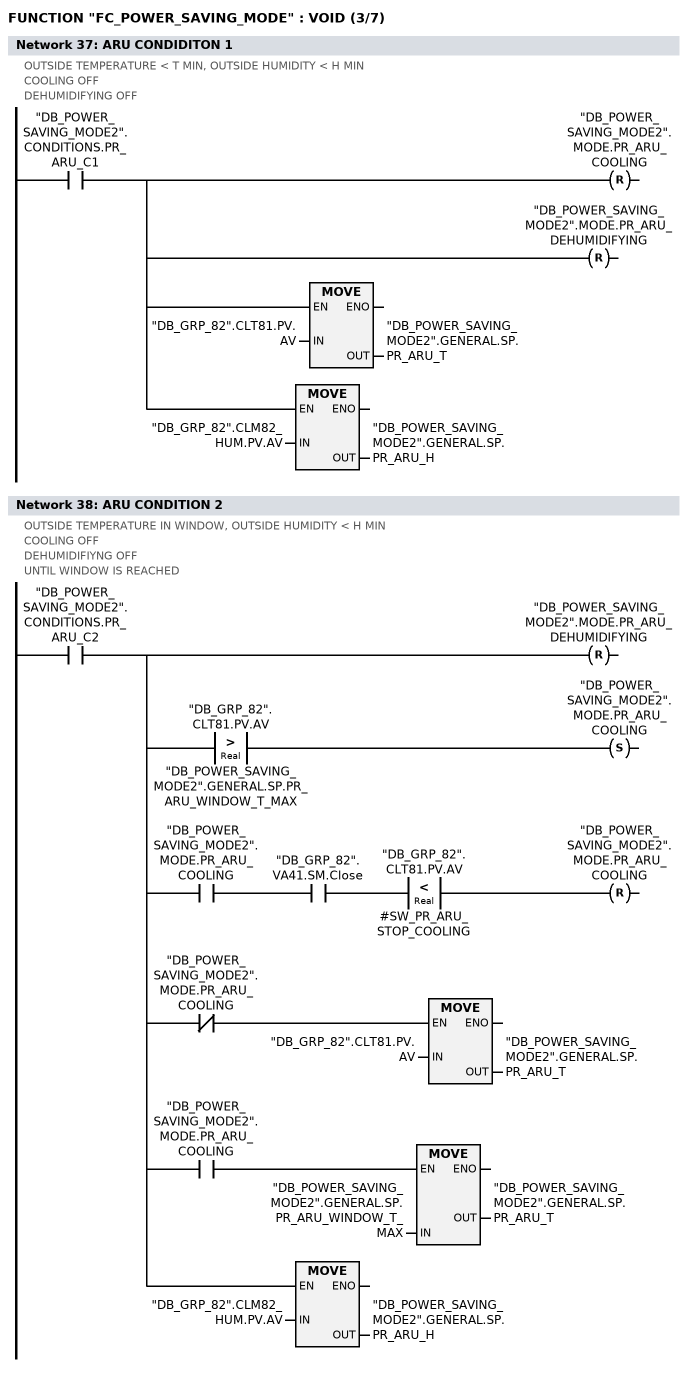
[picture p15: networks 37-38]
      U     "DB_POWER_SAVING_MODE2".CONDITIONS.PR_ARU_C1;
      =     L     84.0;
      U     L     84.0;
      BLD   102;
      R     "DB_POWER_SAVING_MODE2".MODE.PR_ARU_COOLING;
      U     L     84.0;
      BLD   102;
      R     "DB_POWER_SAVING_MODE2".MODE.PR_ARU_DEHUMIDIFYING;
      U     L     84.0;
      SPBNB _05d;
      L     "DB_GRP_82".CLT81.PV.AV;
      T     "DB_POWER_SAVING_MODE2".GENERAL.SP.PR_ARU_T;
_05d: NOP   0;
      U     L     84.0;
      SPBNB _05e;
      L     "DB_GRP_82".CLM82_HUM.PV.AV;
      T     "DB_POWER_SAVING_MODE2".GENERAL.SP.PR_ARU_H;
_05e: NOP   0;
NETWORK
TITLE =ARU CONDITION 2
//OUTSIDE TEMPERATURE IN WINDOW, OUTSIDE HUMIDITY < H MIN
//
//COOLING OFF
//DEHUMIDIFIYNG OFF
//UNTIL WINDOW IS REACHED
      U     "DB_POWER_SAVING_MODE2".CONDITIONS.PR_ARU_C2;
      =     L     84.0;
      U     L     84.0;
      BLD   102;
      R     "DB_POWER_SAVING_MODE2".MODE.PR_ARU_DEHUMIDIFYING;
      U     L     84.0;
      U(    ;
      L     "DB_GRP_82".CLT81.PV.AV;
      L     "DB_POWER_SAVING_MODE2".GENERAL.SP.PR_ARU_WINDOW_T_MAX;
      >R    ;
      )     ;
      S     "DB_POWER_SAVING_MODE2".MODE.PR_ARU_COOLING;
      U     L     84.0;
      U     "DB_POWER_SAVING_MODE2".MODE.PR_ARU_COOLING;
      U     "DB_GRP_82".VA41.SM.Close;
      U(    ;
      L     "DB_GRP_82".CLT81.PV.AV;
      L     #SW_PR_ARU_STOP_COOLING;
      <R    ;
      )     ;
      R     "DB_POWER_SAVING_MODE2".MODE.PR_ARU_COOLING;
      U     L     84.0;
      UN    "DB_POWER_SAVING_MODE2".MODE.PR_ARU_COOLING;
      SPBNB _05f;
      L     "DB_GRP_82".CLT81.PV.AV;
      T     "DB_POWER_SAVING_MODE2".GENERAL.SP.PR_ARU_T;
_05f: NOP   0;
      U     L     84.0;
      U     "DB_POWER_SAVING_MODE2".MODE.PR_ARU_COOLING;
      SPBNB _060;
      L     "DB_POWER_SAVING_MODE2".GENERAL.SP.PR_ARU_WINDOW_T_MAX;
      T     "DB_POWER_SAVING_MODE2".GENERAL.SP.PR_ARU_T;
_060: NOP   0;
      U     L     84.0;
      SPBNB _061;
      L     "DB_GRP_82".CLM82_HUM.PV.AV;
      T     "DB_POWER_SAVING_MODE2".GENERAL.SP.PR_ARU_H;
_061: NOP   0;
NETWORK
TITLE =ARU CONDITION 3
//OUTSIDE TEMPERATURE > T MAX, OUTSIDE HUMIDITY < H MIN
//
//COOLING ON
//DEHUMIDIFYING OFF
//UNTIL WINDOW IS REACHED
//
//COOLING SP T MAX
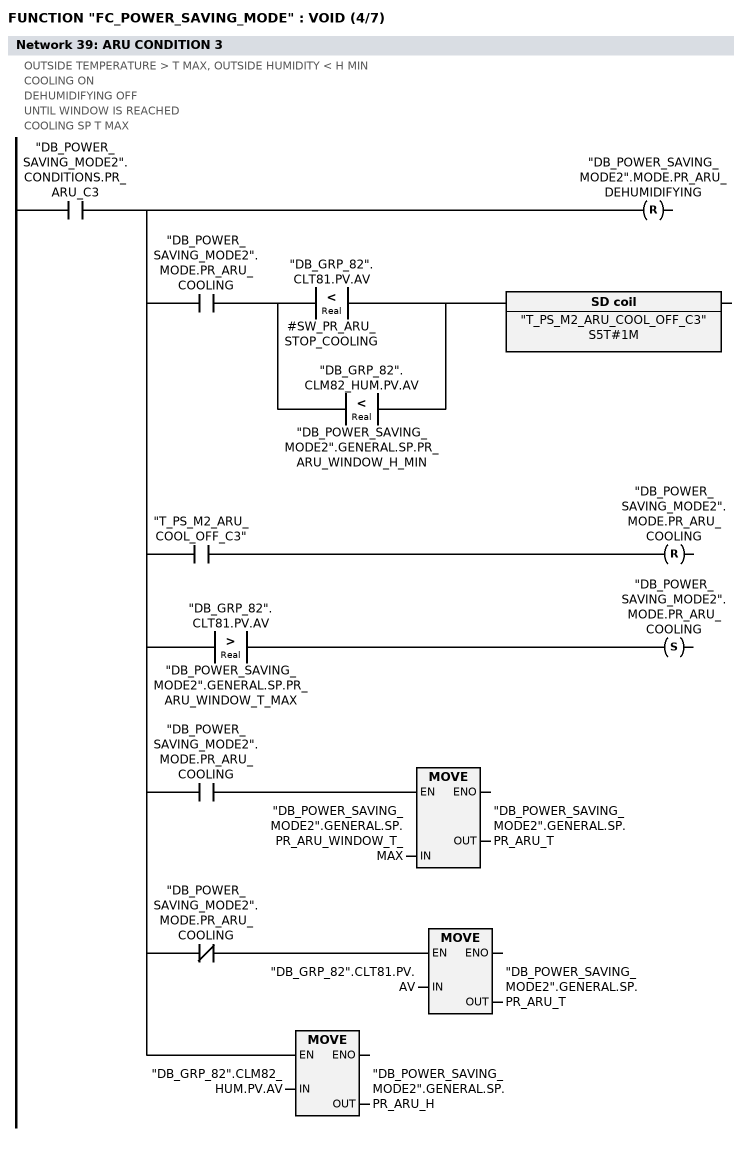
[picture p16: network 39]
      U     "DB_POWER_SAVING_MODE2".CONDITIONS.PR_ARU_C3;
      =     L     84.0;
      U     L     84.0;
      BLD   102;
      R     "DB_POWER_SAVING_MODE2".MODE.PR_ARU_DEHUMIDIFYING;
      U     L     84.0;
      U     "DB_POWER_SAVING_MODE2".MODE.PR_ARU_COOLING;
      U(    ;
      O(    ;
      L     "DB_GRP_82".CLT81.PV.AV;
      L     #SW_PR_ARU_STOP_COOLING;
      <R    ;
      )     ;
      O(    ;
      L     "DB_GRP_82".CLM82_HUM.PV.AV;
      L     "DB_POWER_SAVING_MODE2".GENERAL.SP.PR_ARU_WINDOW_H_MIN;
      <R    ;
      )     ;
      )     ;
      L     S5T#1M;
      SE    "T_PS_M2_ARU_COOL_OFF_C3";
      NOP   0;
      NOP   0;
      NOP   0;
      NOP   0;
      U     L     84.0;
      U     "T_PS_M2_ARU_COOL_OFF_C3";
      R     "DB_POWER_SAVING_MODE2".MODE.PR_ARU_COOLING;
      U     L     84.0;
      U(    ;
      L     "DB_GRP_82".CLT81.PV.AV;
      L     "DB_POWER_SAVING_MODE2".GENERAL.SP.PR_ARU_WINDOW_T_MAX;
      >R    ;
      )     ;
      S     "DB_POWER_SAVING_MODE2".MODE.PR_ARU_COOLING;
      U     L     84.0;
      U     "DB_POWER_SAVING_MODE2".MODE.PR_ARU_COOLING;
      SPBNB _062;
      L     "DB_POWER_SAVING_MODE2".GENERAL.SP.PR_ARU_WINDOW_T_MAX;
      T     "DB_POWER_SAVING_MODE2".GENERAL.SP.PR_ARU_T;
_062: NOP   0;
      U     L     84.0;
      UN    "DB_POWER_SAVING_MODE2".MODE.PR_ARU_COOLING;
      SPBNB _063;
      L     "DB_GRP_82".CLT81.PV.AV;
      T     "DB_POWER_SAVING_MODE2".GENERAL.SP.PR_ARU_T;
_063: NOP   0;
      U     L     84.0;
      SPBNB _064;
      L     "DB_GRP_82".CLM82_HUM.PV.AV;
      T     "DB_POWER_SAVING_MODE2".GENERAL.SP.PR_ARU_H;
_064: NOP   0;
NETWORK
TITLE =ARU CONDITION 4
//OUTSIDE TEMPERATURE > T MAX, OUTSIDE HUMIDITY IN WINDOW
//
//COOLING ON
//DEHUMIDIFYING OFF
//UNTIL WINDOW IS REACHED
//
//COOLING SP T MAX
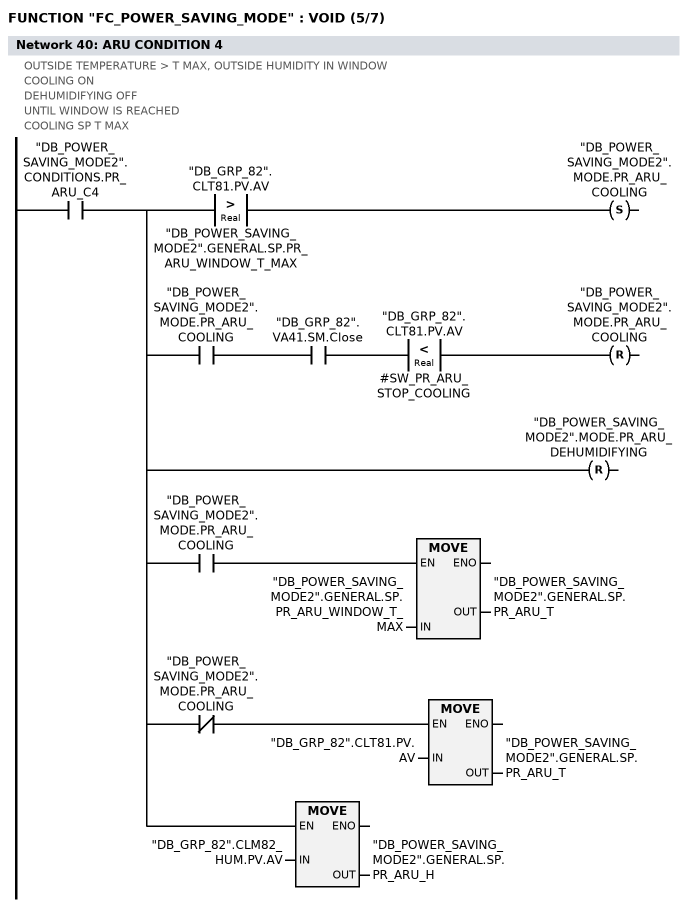
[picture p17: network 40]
      U     "DB_POWER_SAVING_MODE2".CONDITIONS.PR_ARU_C4;
      =     L     84.0;
      U     L     84.0;
      U(    ;
      L     "DB_GRP_82".CLT81.PV.AV;
      L     "DB_POWER_SAVING_MODE2".GENERAL.SP.PR_ARU_WINDOW_T_MAX;
      >R    ;
      )     ;
      S     "DB_POWER_SAVING_MODE2".MODE.PR_ARU_COOLING;
      U     L     84.0;
      U     "DB_POWER_SAVING_MODE2".MODE.PR_ARU_COOLING;
      U     "DB_GRP_82".VA41.SM.Close;
      U(    ;
      L     "DB_GRP_82".CLT81.PV.AV;
      L     #SW_PR_ARU_STOP_COOLING;
      <R    ;
      )     ;
      R     "DB_POWER_SAVING_MODE2".MODE.PR_ARU_COOLING;
      U     L     84.0;
      BLD   102;
      R     "DB_POWER_SAVING_MODE2".MODE.PR_ARU_DEHUMIDIFYING;
      U     L     84.0;
      U     "DB_POWER_SAVING_MODE2".MODE.PR_ARU_COOLING;
      SPBNB _065;
      L     "DB_POWER_SAVING_MODE2".GENERAL.SP.PR_ARU_WINDOW_T_MAX;
      T     "DB_POWER_SAVING_MODE2".GENERAL.SP.PR_ARU_T;
_065: NOP   0;
      U     L     84.0;
      UN    "DB_POWER_SAVING_MODE2".MODE.PR_ARU_COOLING;
      SPBNB _066;
      L     "DB_GRP_82".CLT81.PV.AV;
      T     "DB_POWER_SAVING_MODE2".GENERAL.SP.PR_ARU_T;
_066: NOP   0;
      U     L     84.0;
      SPBNB _067;
      L     "DB_GRP_82".CLM82_HUM.PV.AV;
      T     "DB_POWER_SAVING_MODE2".GENERAL.SP.PR_ARU_H;
_067: NOP   0;
NETWORK
TITLE =ARU CONDITION 5
//OUTSIDE TEMPERATURE > T MAX, OUTSIDE HUMIDITY > H MAX
//
//COOLING ON
//DEHUMIDIFYING (WHEN NO COOLING)
//UNTIL WINDOW IS REACHED
//
//COOLING SP T MAX
//DEHUMIDIFYING SP H MAX
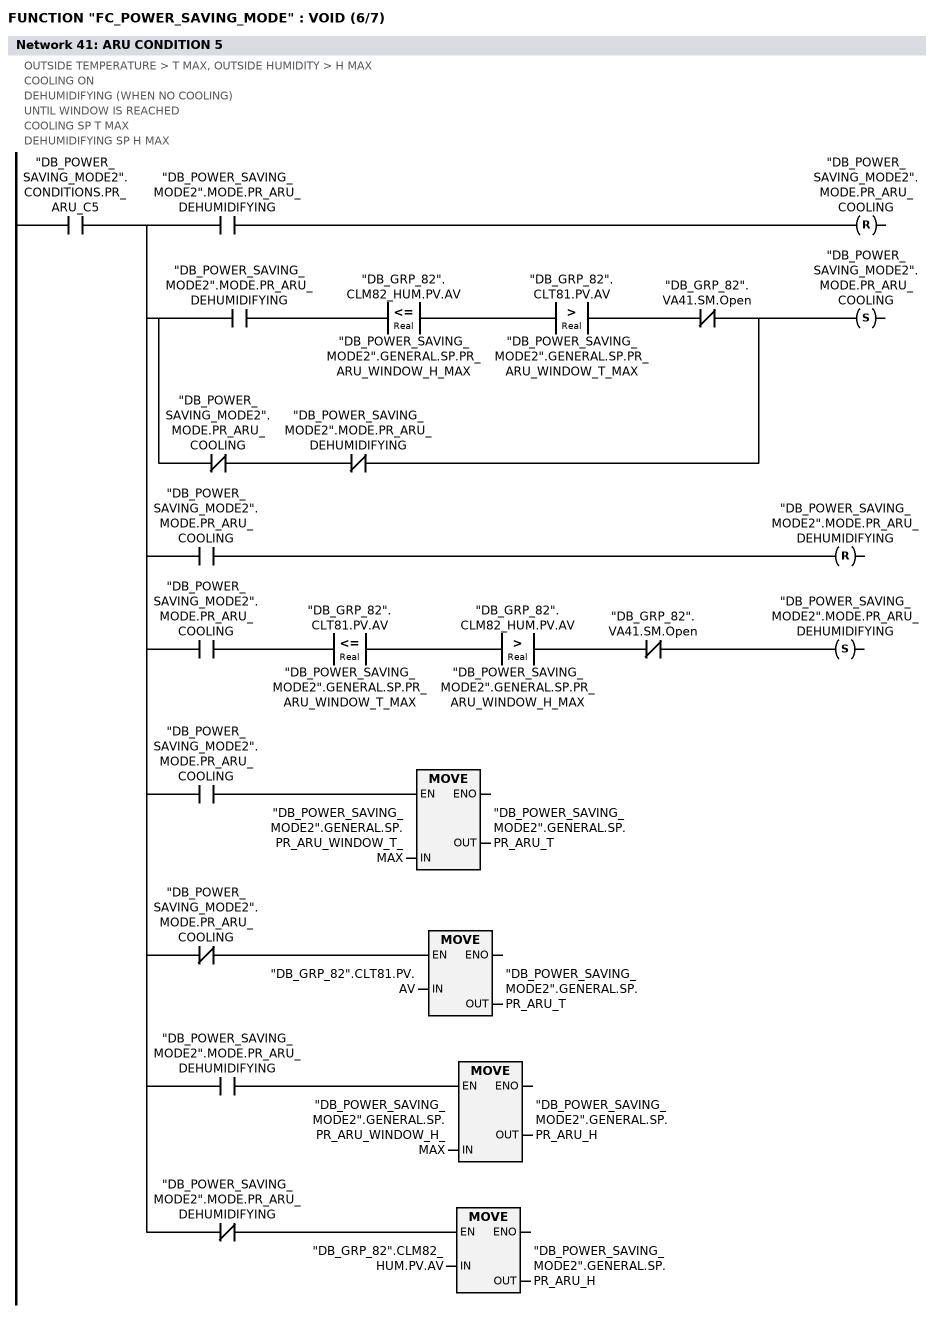
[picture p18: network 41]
      U     "DB_POWER_SAVING_MODE2".CONDITIONS.PR_ARU_C5;
      =     L     84.0;
      U     L     84.0;
      U     "DB_POWER_SAVING_MODE2".MODE.PR_ARU_DEHUMIDIFYING;
      R     "DB_POWER_SAVING_MODE2".MODE.PR_ARU_COOLING;
      U     L     84.0;
      U(    ;
      U     "DB_POWER_SAVING_MODE2".MODE.PR_ARU_DEHUMIDIFYING;
      U(    ;
      L     "DB_GRP_82".CLM82_HUM.PV.AV;
      L     "DB_POWER_SAVING_MODE2".GENERAL.SP.PR_ARU_WINDOW_H_MAX;
      <=R   ;
      )     ;
      U(    ;
      L     "DB_GRP_82".CLT81.PV.AV;
      L     "DB_POWER_SAVING_MODE2".GENERAL.SP.PR_ARU_WINDOW_T_MAX;
      >R    ;
      )     ;
      UN    "DB_GRP_82".VA41.SM.Open;
      O     ;
      UN    "DB_POWER_SAVING_MODE2".MODE.PR_ARU_COOLING;
      UN    "DB_POWER_SAVING_MODE2".MODE.PR_ARU_DEHUMIDIFYING;
      )     ;
      S     "DB_POWER_SAVING_MODE2".MODE.PR_ARU_COOLING;
      U     L     84.0;
      U     "DB_POWER_SAVING_MODE2".MODE.PR_ARU_COOLING;
      R     "DB_POWER_SAVING_MODE2".MODE.PR_ARU_DEHUMIDIFYING;
      U     L     84.0;
      U     "DB_POWER_SAVING_MODE2".MODE.PR_ARU_COOLING;
      U(    ;
      L     "DB_GRP_82".CLT81.PV.AV;
      L     "DB_POWER_SAVING_MODE2".GENERAL.SP.PR_ARU_WINDOW_T_MAX;
      <=R   ;
      )     ;
      U(    ;
      L     "DB_GRP_82".CLM82_HUM.PV.AV;
      L     "DB_POWER_SAVING_MODE2".GENERAL.SP.PR_ARU_WINDOW_H_MAX;
      >R    ;
      )     ;
      UN    "DB_GRP_82".VA41.SM.Open;
      S     "DB_POWER_SAVING_MODE2".MODE.PR_ARU_DEHUMIDIFYING;
      U     L     84.0;
      U     "DB_POWER_SAVING_MODE2".MODE.PR_ARU_COOLING;
      SPBNB _068;
      L     "DB_POWER_SAVING_MODE2".GENERAL.SP.PR_ARU_WINDOW_T_MAX;
      T     "DB_POWER_SAVING_MODE2".GENERAL.SP.PR_ARU_T;
_068: NOP   0;
      U     L     84.0;
      UN    "DB_POWER_SAVING_MODE2".MODE.PR_ARU_COOLING;
      SPBNB _069;
      L     "DB_GRP_82".CLT81.PV.AV;
      T     "DB_POWER_SAVING_MODE2".GENERAL.SP.PR_ARU_T;
_069: NOP   0;
      U     L     84.0;
      U     "DB_POWER_SAVING_MODE2".MODE.PR_ARU_DEHUMIDIFYING;
      SPBNB _06a;
      L     "DB_POWER_SAVING_MODE2".GENERAL.SP.PR_ARU_WINDOW_H_MAX;
      T     "DB_POWER_SAVING_MODE2".GENERAL.SP.PR_ARU_H;
_06a: NOP   0;
      U     L     84.0;
      UN    "DB_POWER_SAVING_MODE2".MODE.PR_ARU_DEHUMIDIFYING;
      SPBNB _06b;
      L     "DB_GRP_82".CLM82_HUM.PV.AV;
      T     "DB_POWER_SAVING_MODE2".GENERAL.SP.PR_ARU_H;
_06b: NOP   0;
NETWORK
TITLE =ARU CONDITION 6
//OUTSIDE TEMPERATURE IN WINDOW, OUTSIDE HUMIDITY > H MAX
//
//COOLING OFF
//DEHUMIDIFYING ON
//UNTIL WINDOW IS REACHED
//
//DEHUMIDIFYING SP H MAX
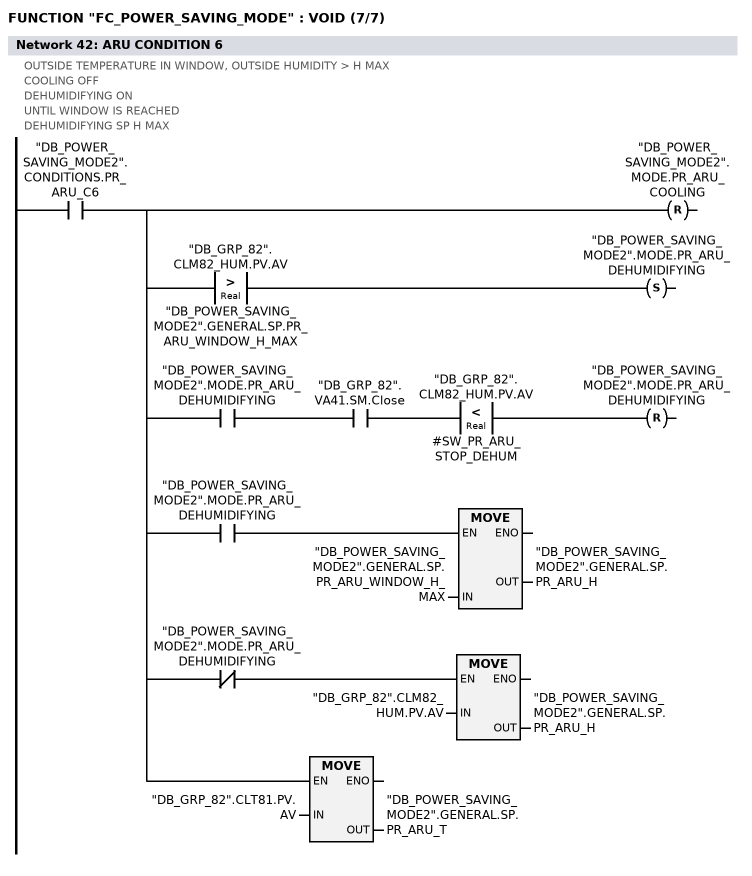
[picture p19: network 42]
      U     "DB_POWER_SAVING_MODE2".CONDITIONS.PR_ARU_C6;
      =     L     84.0;
      U     L     84.0;
      BLD   102;
      R     "DB_POWER_SAVING_MODE2".MODE.PR_ARU_COOLING;
      U     L     84.0;
      U(    ;
      L     "DB_GRP_82".CLM82_HUM.PV.AV;
      L     "DB_POWER_SAVING_MODE2".GENERAL.SP.PR_ARU_WINDOW_H_MAX;
      >R    ;
      )     ;
      S     "DB_POWER_SAVING_MODE2".MODE.PR_ARU_DEHUMIDIFYING;
      U     L     84.0;
      U     "DB_POWER_SAVING_MODE2".MODE.PR_ARU_DEHUMIDIFYING;
      U     "DB_GRP_82".VA41.SM.Close;
      U(    ;
      L     "DB_GRP_82".CLM82_HUM.PV.AV;
      L     #SW_PR_ARU_STOP_DEHUM;
      <R    ;
      )     ;
      R     "DB_POWER_SAVING_MODE2".MODE.PR_ARU_DEHUMIDIFYING;
      U     L     84.0;
      U     "DB_POWER_SAVING_MODE2".MODE.PR_ARU_DEHUMIDIFYING;
      SPBNB _06c;
      L     "DB_POWER_SAVING_MODE2".GENERAL.SP.PR_ARU_WINDOW_H_MAX;
      T     "DB_POWER_SAVING_MODE2".GENERAL.SP.PR_ARU_H;
_06c: NOP   0;
      U     L     84.0;
      UN    "DB_POWER_SAVING_MODE2".MODE.PR_ARU_DEHUMIDIFYING;
      SPBNB _06d;
      L     "DB_GRP_82".CLM82_HUM.PV.AV;
      T     "DB_POWER_SAVING_MODE2".GENERAL.SP.PR_ARU_H;
_06d: NOP   0;
      U     L     84.0;
      SPBNB _06e;
      L     "DB_GRP_82".CLT81.PV.AV;
      T     "DB_POWER_SAVING_MODE2".GENERAL.SP.PR_ARU_T;
_06e: NOP   0;
NETWORK
TITLE =ARU CONDITION 7
//OUTSIDE TEMPERATURE < T MIN, OUTSIDE HUMIDITY > H MAX
//
//COOLING OFF
//DEHUMIDIFYING ON
//UNTIL WINDOW IS REACHED
//
//DEHUMIDIFYING SP H MAX
      U     "DB_POWER_SAVING_MODE2".CONDITIONS.PR_ARU_C7;
      =     L     84.0;
      U     L     84.0;
      BLD   102;
      R     "DB_POWER_SAVING_MODE2".MODE.PR_ARU_COOLING;
      U     L     84.0;
      U     "DB_POWER_SAVING_MODE2".MODE.PR_ARU_DEHUMIDIFYING;
      U(    ;
      L     "DB_GRP_82".CLM82_HUM.PV.AV;
      L     #SW_PR_ARU_STOP_DEHUM;
      <R    ;
      )     ;
      L     S5T#1M;
      SE    "T_PS_M2_ARU_DEHUM_OFF_C7";
      NOP   0;
      NOP   0;
      NOP   0;
      U     "T_PS_M2_ARU_DEHUM_OFF_C7";
      R     "DB_POWER_SAVING_MODE2".MODE.PR_ARU_DEHUMIDIFYING;
      U     L     84.0;
      U(    ;
      L     "DB_GRP_82".CLM82_HUM.PV.AV;
      L     "DB_POWER_SAVING_MODE2".GENERAL.SP.PR_ARU_WINDOW_H_MAX;
      >R    ;
      )     ;
      S     "DB_POWER_SAVING_MODE2".MODE.PR_ARU_DEHUMIDIFYING;
      U     L     84.0;
      U     "DB_POWER_SAVING_MODE2".MODE.PR_ARU_DEHUMIDIFYING;
      SPBNB _06f;
      L     "DB_POWER_SAVING_MODE2".GENERAL.SP.PR_ARU_WINDOW_H_MAX;
      T     "DB_POWER_SAVING_MODE2".GENERAL.SP.PR_ARU_H;
_06f: NOP   0;
      U     L     84.0;
      UN    "DB_POWER_SAVING_MODE2".MODE.PR_ARU_DEHUMIDIFYING;
      SPBNB _070;
      L     "DB_GRP_82".CLM82_HUM.PV.AV;
      T     "DB_POWER_SAVING_MODE2".GENERAL.SP.PR_ARU_H;
_070: NOP   0;
NETWORK
TITLE =ARU CONDITION 8
//OUTSIDE TEMPERATURE < T MIN, OUTSIDE HUMIDITY IN WINDOW
//
//COOLING OFF
//DEHUMIDIFYING OFF
//UNTIL WINDOW IS REACHED
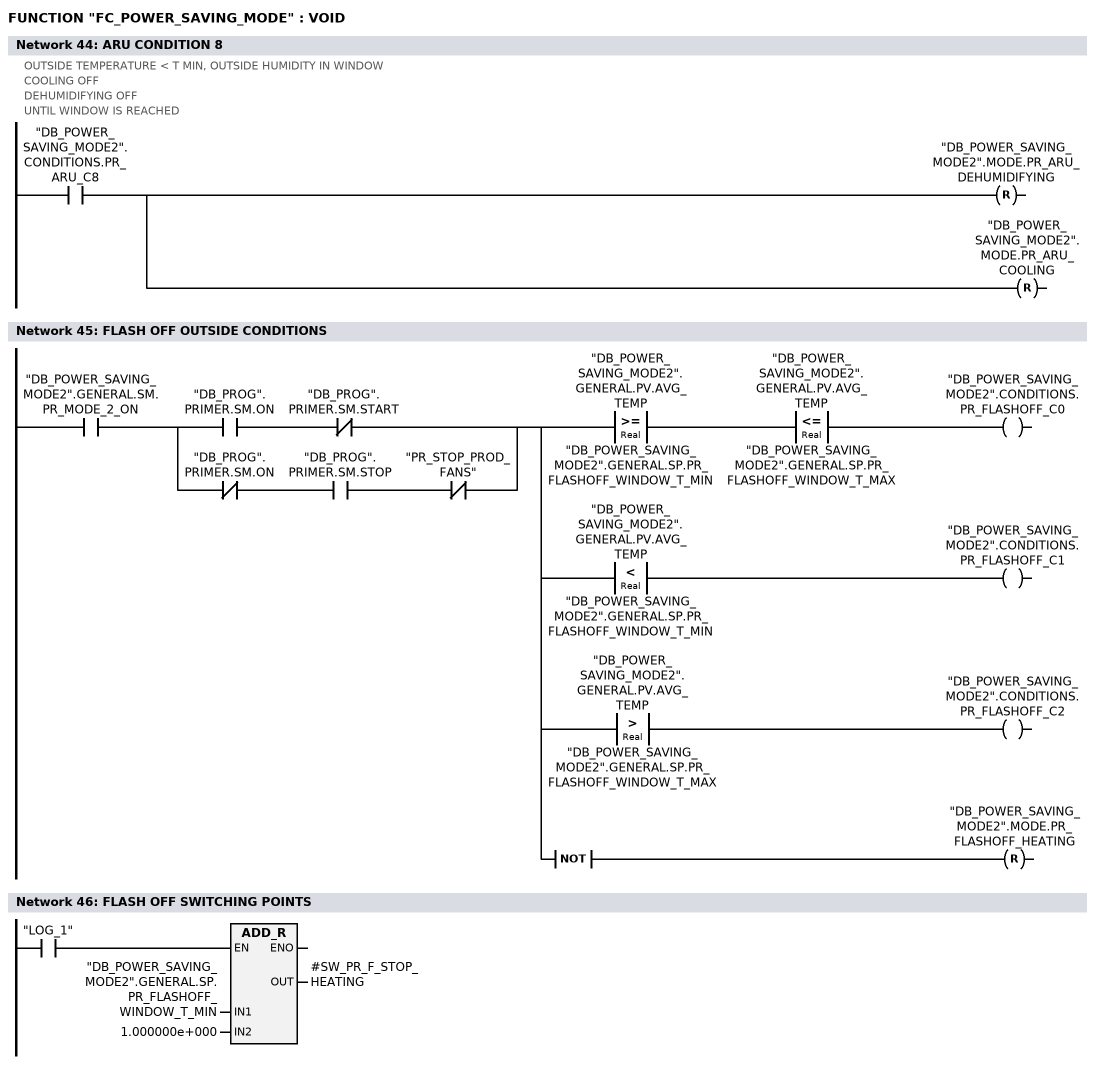
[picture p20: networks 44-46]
      U     "DB_POWER_SAVING_MODE2".CONDITIONS.PR_ARU_C8;
      R     "DB_POWER_SAVING_MODE2".MODE.PR_ARU_DEHUMIDIFYING;
      R     "DB_POWER_SAVING_MODE2".MODE.PR_ARU_COOLING;
NETWORK
TITLE =FLASH OFF OUTSIDE CONDITIONS

      U     "DB_POWER_SAVING_MODE2".GENERAL.SM.PR_MODE_2_ON;
      U(    ;
      U     "DB_PROG".PRIMER.SM.ON;
      UN    "DB_PROG".PRIMER.SM.START;
      O     ;
      UN    "DB_PROG".PRIMER.SM.ON;
      U     "DB_PROG".PRIMER.SM.STOP;
      UN    "PR_STOP_PROD_FANS";
      )     ;
      =     L     84.0;
      U     L     84.0;
      U(    ;
      L     "DB_POWER_SAVING_MODE2".GENERAL.PV.AVG_TEMP;
      L     "DB_POWER_SAVING_MODE2".GENERAL.SP.PR_FLASHOFF_WINDOW_T_MIN;
      >=R   ;
      )     ;
      U(    ;
      L     "DB_POWER_SAVING_MODE2".GENERAL.PV.AVG_TEMP;
      L     "DB_POWER_SAVING_MODE2".GENERAL.SP.PR_FLASHOFF_WINDOW_T_MAX;
      <=R   ;
      )     ;
      =     "DB_POWER_SAVING_MODE2".CONDITIONS.PR_FLASHOFF_C0;
      U     L     84.0;
      U(    ;
      L     "DB_POWER_SAVING_MODE2".GENERAL.PV.AVG_TEMP;
      L     "DB_POWER_SAVING_MODE2".GENERAL.SP.PR_FLASHOFF_WINDOW_T_MIN;
      <R    ;
      )     ;
      =     "DB_POWER_SAVING_MODE2".CONDITIONS.PR_FLASHOFF_C1;
      U     L     84.0;
      U(    ;
      L     "DB_POWER_SAVING_MODE2".GENERAL.PV.AVG_TEMP;
      L     "DB_POWER_SAVING_MODE2".GENERAL.SP.PR_FLASHOFF_WINDOW_T_MAX;
      >R    ;
      )     ;
      =     "DB_POWER_SAVING_MODE2".CONDITIONS.PR_FLASHOFF_C2;
      U     L     84.0;
      NOT   ;
      R     "DB_POWER_SAVING_MODE2".MODE.PR_FLASHOFF_HEATING;
NETWORK
TITLE =FLASH OFF SWITCHING POINTS

      U     "LOG_1";
      SPBNB _071;
      L     "DB_POWER_SAVING_MODE2".GENERAL.SP.PR_FLASHOFF_WINDOW_T_MIN;
      L     1.000000e+000;
      +R    ;
      T     #SW_PR_F_STOP_HEATING;
_071: NOP   0;
NETWORK
TITLE =FLASH OFF CONDIDITON 0
//OUTSIDE TEMP. IN WINDOW
//
//HEATING OFF
      U     "DB_POWER_SAVING_MODE2".CONDITIONS.PR_FLASHOFF_C0;
      =     L     84.0;
      U     L     84.0;
      U     "DB_POWER_SAVING_MODE2".MODE.PR_FLASHOFF_HEATING;
      U(    ;
      L     "DB_GRP_83".CLT81.PV.AV;
      L     #SW_PR_F_STOP_HEATING;
      >R    ;
      )     ;
      L     S5T#2M;
      SE    "T_PS_M2_F_HEAT_OFF_C0";
      NOP   0;
      NOP   0;
      NOP   0;
      U     "T_PS_M2_F_HEAT_OFF_C0";
      R     "DB_POWER_SAVING_MODE2".MODE.PR_FLASHOFF_HEATING;
      U     L     84.0;
      U(    ;
      L     "DB_GRP_83".CLT81.PV.AV;
      L     "DB_POWER_SAVING_MODE2".GENERAL.SP.PR_FLASHOFF_WINDOW_T_MIN;
      <R    ;
      )     ;
      S     "DB_POWER_SAVING_MODE2".MODE.PR_FLASHOFF_HEATING;
      U     L     84.0;
      U     "DB_POWER_SAVING_MODE2".MODE.PR_FLASHOFF_HEATING;
      SPBNB _072;
      L     "DB_POWER_SAVING_MODE2".GENERAL.SP.PR_FLASHOFF_WINDOW_T_MIN;
      T     "DB_POWER_SAVING_MODE2".GENERAL.SP.PR_FLASHOFF_T;
_072: NOP   0;
      U     L     84.0;
      UN    "DB_POWER_SAVING_MODE2".MODE.PR_FLASHOFF_HEATING;
      SPBNB _073;
      L     "DB_GRP_83".CLT81.PV.AV;
      T     "DB_POWER_SAVING_MODE2".GENERAL.SP.PR_FLASHOFF_T;
_073: NOP   0;
NETWORK
TITLE =FLASH OFF CONDIDITON 1
//OUTSIDE TEMPERATURE < T MIN
//
//HEATING ON
//UNTIL WINDOW IS REACHED
//
//HEATING SP T MIN
      U     "DB_POWER_SAVING_MODE2".CONDITIONS.PR_FLASHOFF_C1;
      =     L     84.0;
      U     L     84.0;
      U(    ;
      L     "DB_GRP_83".CLT81.PV.AV;
      L     "DB_POWER_SAVING_MODE2".GENERAL.SP.PR_FLASHOFF_WINDOW_T_MIN;
      <R    ;
      )     ;
      S     "DB_POWER_SAVING_MODE2".MODE.PR_FLASHOFF_HEATING;
      U     L     84.0;
      U     "DB_POWER_SAVING_MODE2".MODE.PR_FLASHOFF_HEATING;
      U(    ;
      L     "DB_GRP_83".CLT81.PV.AV;
      L     #SW_PR_F_STOP_HEATING;
      >R    ;
      )     ;
      L     S5T#2M;
      SE    "T_PS_M2_F_HEAT_OFF_C1";
      NOP   0;
      NOP   0;
      NOP   0;
      U     "T_PS_M2_F_HEAT_OFF_C1";
      R     "DB_POWER_SAVING_MODE2".MODE.PR_FLASHOFF_HEATING;
      U     L     84.0;
      U     "DB_POWER_SAVING_MODE2".MODE.PR_FLASHOFF_HEATING;
      SPBNB _074;
      L     "DB_POWER_SAVING_MODE2".GENERAL.SP.PR_FLASHOFF_WINDOW_T_MIN;
      T     "DB_POWER_SAVING_MODE2".GENERAL.SP.PR_FLASHOFF_T;
_074: NOP   0;
      U     L     84.0;
      UN    "DB_POWER_SAVING_MODE2".MODE.PR_FLASHOFF_HEATING;
      SPBNB _075;
      L     "DB_GRP_83".CLT81.PV.AV;
      T     "DB_POWER_SAVING_MODE2".GENERAL.SP.PR_FLASHOFF_T;
_075: NOP   0;
NETWORK
TITLE =FLASH OFF CONDITION 2
//OUTSIDE TEMPERATURE > T MAX
//
//HEATING ON (ONLY IF TEMPERATURE GOES DOWN OUT THE WINDOW)
//UNTIL WINDOW IS REACHED
//
//HEATING SP T MIN
      U     "DB_POWER_SAVING_MODE2".CONDITIONS.PR_FLASHOFF_C2;
      =     L     84.0;
      U     L     84.0;
      U     "DB_POWER_SAVING_MODE2".MODE.PR_FLASHOFF_HEATING;
      U     "DB_GRP_83".VA51.SM.Open;
      U(    ;
      L     "DB_GRP_83".PP51.PV.AV;
      L     8.000000e+000;
      <=R   ;
      )     ;
      U(    ;
      L     "DB_GRP_83".CLT81.PV.AV;
      L     "DB_POWER_SAVING_MODE2".GENERAL.SP.PR_FLASHOFF_WINDOW_T_MIN;
      >R    ;
      )     ;
      L     S5T#30S;
      SE    "T_PS_M2_F_HEAT_OFF_C2";
      NOP   0;
      NOP   0;
      NOP   0;
      U     "T_PS_M2_F_HEAT_OFF_C2";
      R     "DB_POWER_SAVING_MODE2".MODE.PR_FLASHOFF_HEATING;
      U     L     84.0;
      U(    ;
      L     "DB_GRP_83".CLT81.PV.AV;
      L     "DB_POWER_SAVING_MODE2".GENERAL.SP.PR_FLASHOFF_WINDOW_T_MIN;
      <R    ;
      )     ;
      S     "DB_POWER_SAVING_MODE2".MODE.PR_FLASHOFF_HEATING;
      U     L     84.0;
      U     "DB_POWER_SAVING_MODE2".MODE.PR_FLASHOFF_HEATING;
      SPBNB _076;
      L     "DB_POWER_SAVING_MODE2".GENERAL.SP.PR_FLASHOFF_WINDOW_T_MIN;
      T     "DB_POWER_SAVING_MODE2".GENERAL.SP.PR_FLASHOFF_T;
_076: NOP   0;
      U     L     84.0;
      UN    "DB_POWER_SAVING_MODE2".MODE.PR_FLASHOFF_HEATING;
      SPBNB _077;
      L     "DB_GRP_83".CLT81.PV.AV;
      T     "DB_POWER_SAVING_MODE2".GENERAL.SP.PR_FLASHOFF_T;
_077: NOP   0;
NETWORK
TITLE =TRANSFER SETPOINTS

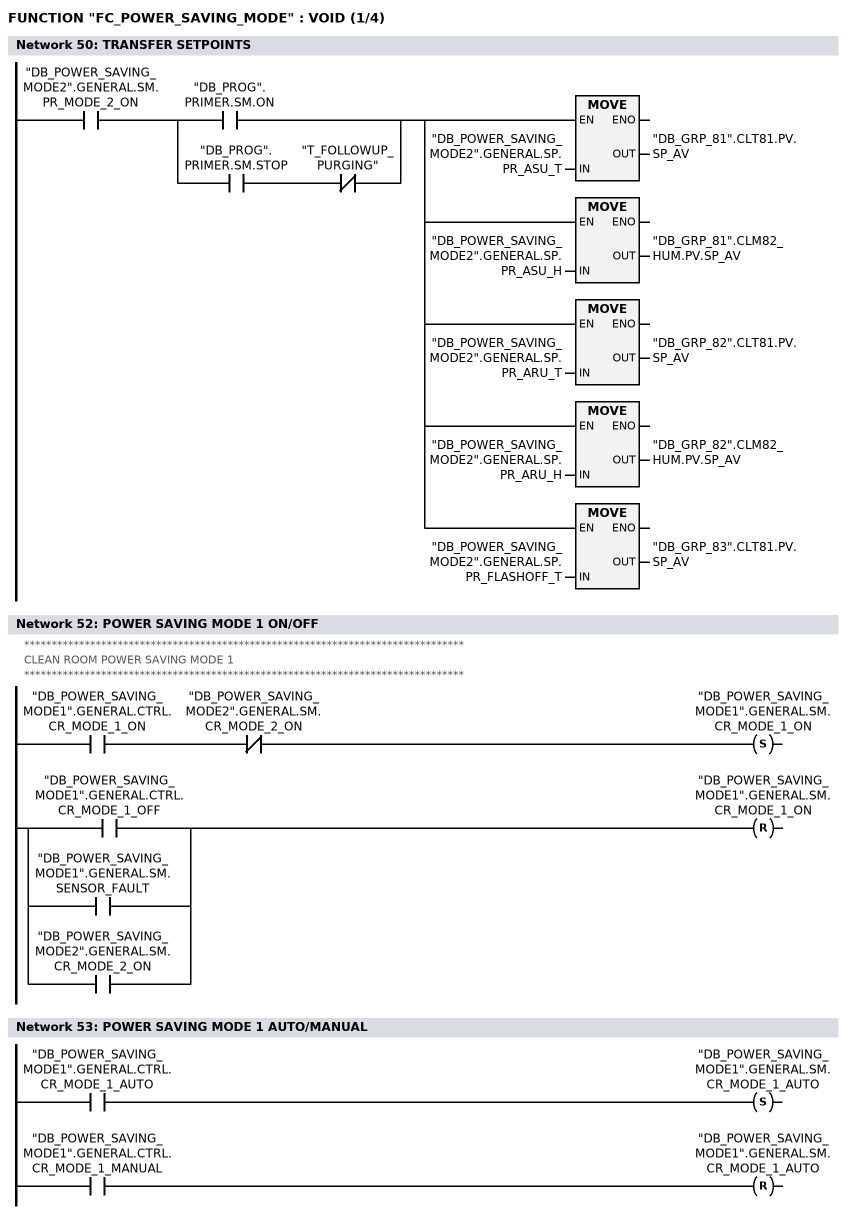
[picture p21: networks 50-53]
      U     "DB_POWER_SAVING_MODE2".GENERAL.SM.PR_MODE_2_ON;
      U(    ;
      O     "DB_PROG".PRIMER.SM.ON;
      O     ;
      U     "DB_PROG".PRIMER.SM.STOP;
      UN    "T_FOLLOWUP_PURGING";
      )     ;
      =     L     84.0;
      U     L     84.0;
      SPBNB _078;
      L     "DB_POWER_SAVING_MODE2".GENERAL.SP.PR_ASU_T;
      T     "DB_GRP_81".CLT81.PV.SP_AV;
_078: NOP   0;
      U     L     84.0;
      SPBNB _079;
      L     "DB_POWER_SAVING_MODE2".GENERAL.SP.PR_ASU_H;
      T     "DB_GRP_81".CLM82_HUM.PV.SP_AV;
_079: NOP   0;
      U     L     84.0;
      SPBNB _07a;
      L     "DB_POWER_SAVING_MODE2".GENERAL.SP.PR_ARU_T;
      T     "DB_GRP_82".CLT81.PV.SP_AV;
_07a: NOP   0;
      U     L     84.0;
      SPBNB _07b;
      L     "DB_POWER_SAVING_MODE2".GENERAL.SP.PR_ARU_H;
      T     "DB_GRP_82".CLM82_HUM.PV.SP_AV;
_07b: NOP   0;
      U     L     84.0;
      SPBNB _07c;
      L     "DB_POWER_SAVING_MODE2".GENERAL.SP.PR_FLASHOFF_T;
      T     "DB_GRP_83".CLT81.PV.SP_AV;
_07c: NOP   0;
NETWORK
TITLE = ********** POWER SAFE MODE CLEAN ROOM **********

NETWORK
TITLE =POWER SAVING MODE 1 ON/OFF
//********************************************************************************
//
//                           CLEAN ROOM POWER SAVING MODE 1
//
//********************************************************************************
//
      U     "DB_POWER_SAVING_MODE1".GENERAL.CTRL.CR_MODE_1_ON;
      UN    "DB_POWER_SAVING_MODE2".GENERAL.SM.CR_MODE_2_ON;
      S     "DB_POWER_SAVING_MODE1".GENERAL.SM.CR_MODE_1_ON;
      U(    ;
      O     "DB_POWER_SAVING_MODE1".GENERAL.CTRL.CR_MODE_1_OFF;
      O     "DB_POWER_SAVING_MODE1".GENERAL.SM.SENSOR_FAULT;
      O     "DB_POWER_SAVING_MODE2".GENERAL.SM.CR_MODE_2_ON;
      )     ;
      R     "DB_POWER_SAVING_MODE1".GENERAL.SM.CR_MODE_1_ON;
      NOP   0;
NETWORK
TITLE =POWER SAVING MODE 1 AUTO/MANUAL

      U     "DB_POWER_SAVING_MODE1".GENERAL.CTRL.CR_MODE_1_AUTO;
      S     "DB_POWER_SAVING_MODE1".GENERAL.SM.CR_MODE_1_AUTO;
      U     "DB_POWER_SAVING_MODE1".GENERAL.CTRL.CR_MODE_1_MANUAL;
      R     "DB_POWER_SAVING_MODE1".GENERAL.SM.CR_MODE_1_AUTO;
      NOP   0;
NETWORK
TITLE =EXTREME SUMMER MODE

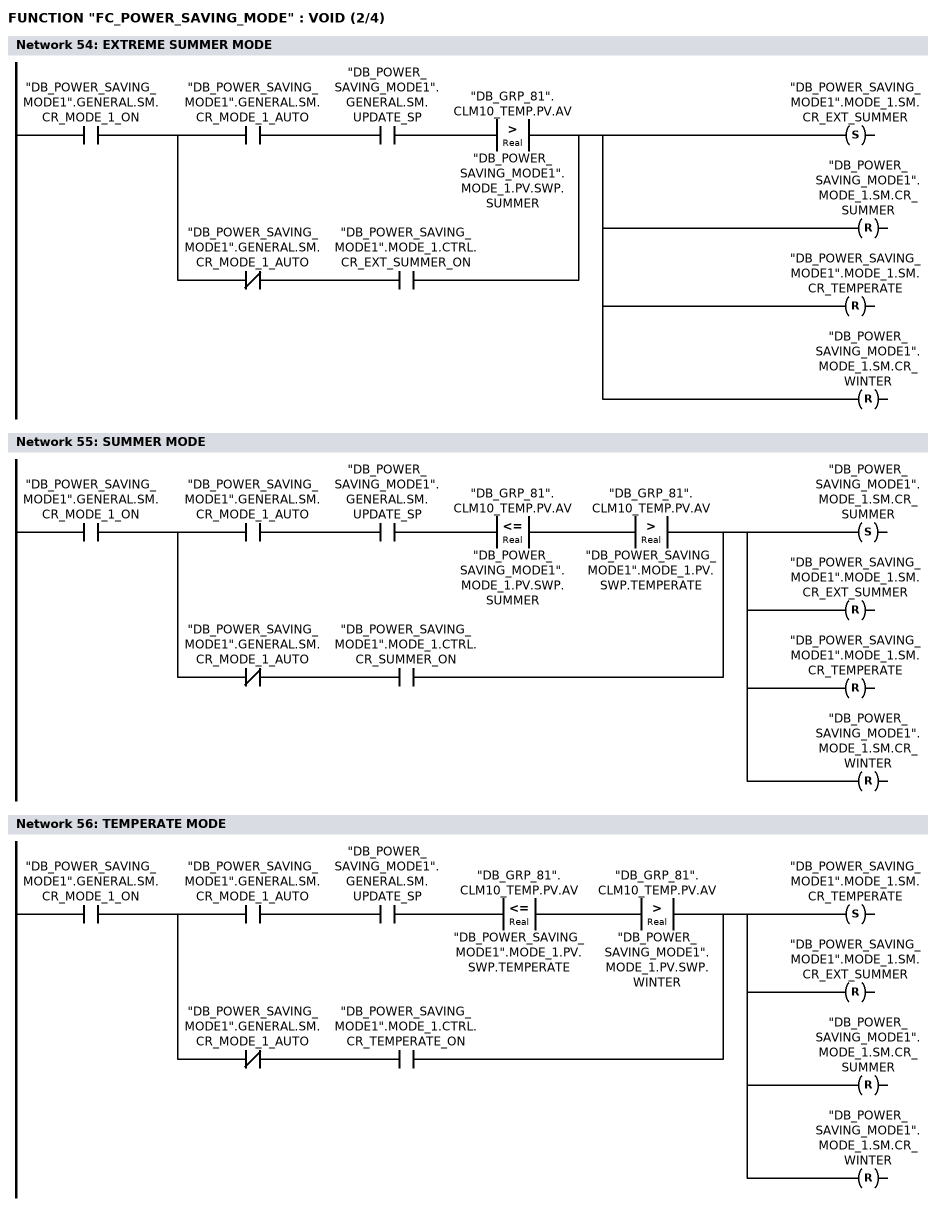
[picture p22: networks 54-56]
      U     "DB_POWER_SAVING_MODE1".GENERAL.SM.CR_MODE_1_ON;
      U(    ;
      U     "DB_POWER_SAVING_MODE1".GENERAL.SM.CR_MODE_1_AUTO;
      U     "DB_POWER_SAVING_MODE1".GENERAL.SM.UPDATE_SP;
      U(    ;
      L     "DB_GRP_81".CLM10_TEMP.PV.AV;
      L     "DB_POWER_SAVING_MODE1".MODE_1.PV.SWP.SUMMER;
      >R    ;
      )     ;
      O     ;
      UN    "DB_POWER_SAVING_MODE1".GENERAL.SM.CR_MODE_1_AUTO;
      U     "DB_POWER_SAVING_MODE1".MODE_1.CTRL.CR_EXT_SUMMER_ON;
      )     ;
      S     "DB_POWER_SAVING_MODE1".MODE_1.SM.CR_EXT_SUMMER;
      R     "DB_POWER_SAVING_MODE1".MODE_1.SM.CR_SUMMER;
      R     "DB_POWER_SAVING_MODE1".MODE_1.SM.CR_TEMPERATE;
      R     "DB_POWER_SAVING_MODE1".MODE_1.SM.CR_WINTER;
NETWORK
TITLE =SUMMER MODE

      U     "DB_POWER_SAVING_MODE1".GENERAL.SM.CR_MODE_1_ON;
      U(    ;
      U     "DB_POWER_SAVING_MODE1".GENERAL.SM.CR_MODE_1_AUTO;
      U     "DB_POWER_SAVING_MODE1".GENERAL.SM.UPDATE_SP;
      U(    ;
      L     "DB_GRP_81".CLM10_TEMP.PV.AV;
      L     "DB_POWER_SAVING_MODE1".MODE_1.PV.SWP.SUMMER;
      <=R   ;
      )     ;
      U(    ;
      L     "DB_GRP_81".CLM10_TEMP.PV.AV;
      L     "DB_POWER_SAVING_MODE1".MODE_1.PV.SWP.TEMPERATE;
      >R    ;
      )     ;
      O     ;
      UN    "DB_POWER_SAVING_MODE1".GENERAL.SM.CR_MODE_1_AUTO;
      U     "DB_POWER_SAVING_MODE1".MODE_1.CTRL.CR_SUMMER_ON;
      )     ;
      S     "DB_POWER_SAVING_MODE1".MODE_1.SM.CR_SUMMER;
      R     "DB_POWER_SAVING_MODE1".MODE_1.SM.CR_EXT_SUMMER;
      R     "DB_POWER_SAVING_MODE1".MODE_1.SM.CR_TEMPERATE;
      R     "DB_POWER_SAVING_MODE1".MODE_1.SM.CR_WINTER;
NETWORK
TITLE =TEMPERATE MODE

      U     "DB_POWER_SAVING_MODE1".GENERAL.SM.CR_MODE_1_ON;
      U(    ;
      U     "DB_POWER_SAVING_MODE1".GENERAL.SM.CR_MODE_1_AUTO;
      U     "DB_POWER_SAVING_MODE1".GENERAL.SM.UPDATE_SP;
      U(    ;
      L     "DB_GRP_81".CLM10_TEMP.PV.AV;
      L     "DB_POWER_SAVING_MODE1".MODE_1.PV.SWP.TEMPERATE;
      <=R   ;
      )     ;
      U(    ;
      L     "DB_GRP_81".CLM10_TEMP.PV.AV;
      L     "DB_POWER_SAVING_MODE1".MODE_1.PV.SWP.WINTER;
      >R    ;
      )     ;
      O     ;
      UN    "DB_POWER_SAVING_MODE1".GENERAL.SM.CR_MODE_1_AUTO;
      U     "DB_POWER_SAVING_MODE1".MODE_1.CTRL.CR_TEMPERATE_ON;
      )     ;
      S     "DB_POWER_SAVING_MODE1".MODE_1.SM.CR_TEMPERATE;
      R     "DB_POWER_SAVING_MODE1".MODE_1.SM.CR_EXT_SUMMER;
      R     "DB_POWER_SAVING_MODE1".MODE_1.SM.CR_SUMMER;
      R     "DB_POWER_SAVING_MODE1".MODE_1.SM.CR_WINTER;
NETWORK
TITLE =WINTER MODE

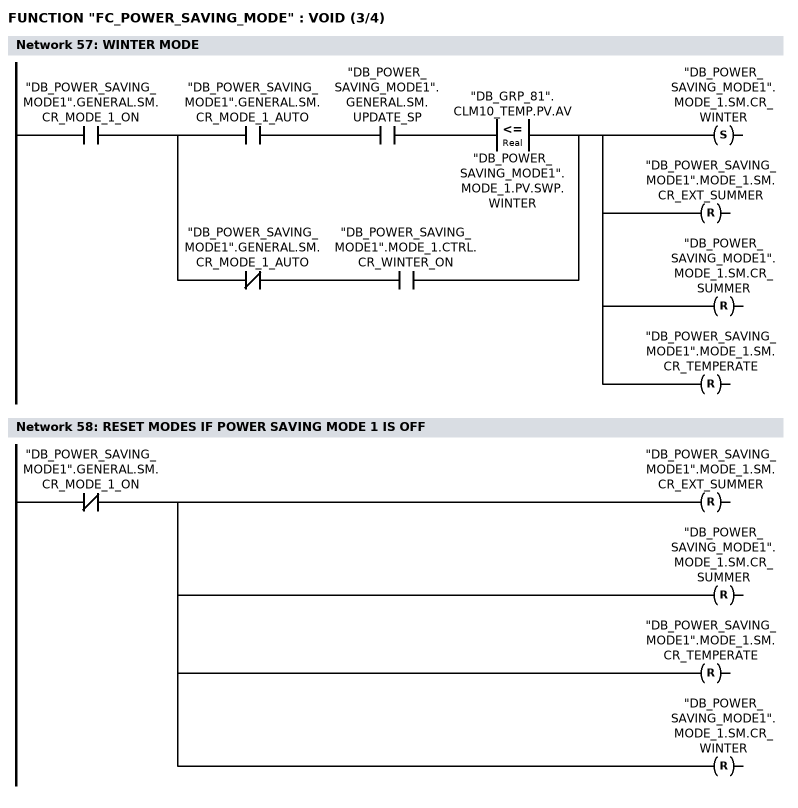
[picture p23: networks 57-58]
      U     "DB_POWER_SAVING_MODE1".GENERAL.SM.CR_MODE_1_ON;
      U(    ;
      U     "DB_POWER_SAVING_MODE1".GENERAL.SM.CR_MODE_1_AUTO;
      U     "DB_POWER_SAVING_MODE1".GENERAL.SM.UPDATE_SP;
      U(    ;
      L     "DB_GRP_81".CLM10_TEMP.PV.AV;
      L     "DB_POWER_SAVING_MODE1".MODE_1.PV.SWP.WINTER;
      <=R   ;
      )     ;
      O     ;
      UN    "DB_POWER_SAVING_MODE1".GENERAL.SM.CR_MODE_1_AUTO;
      U     "DB_POWER_SAVING_MODE1".MODE_1.CTRL.CR_WINTER_ON;
      )     ;
      S     "DB_POWER_SAVING_MODE1".MODE_1.SM.CR_WINTER;
      R     "DB_POWER_SAVING_MODE1".MODE_1.SM.CR_EXT_SUMMER;
      R     "DB_POWER_SAVING_MODE1".MODE_1.SM.CR_SUMMER;
      R     "DB_POWER_SAVING_MODE1".MODE_1.SM.CR_TEMPERATE;
NETWORK
TITLE =RESET MODES IF POWER SAVING MODE 1 IS OFF

      UN    "DB_POWER_SAVING_MODE1".GENERAL.SM.CR_MODE_1_ON;
      R     "DB_POWER_SAVING_MODE1".MODE_1.SM.CR_EXT_SUMMER;
      R     "DB_POWER_SAVING_MODE1".MODE_1.SM.CR_SUMMER;
      R     "DB_POWER_SAVING_MODE1".MODE_1.SM.CR_TEMPERATE;
      R     "DB_POWER_SAVING_MODE1".MODE_1.SM.CR_WINTER;
NETWORK
TITLE =SETPOINT SELECTION

      U     "LOG_1";
      =     L     84.0;
      U(    ;
      U     L     84.0;
      U     "DB_POWER_SAVING_MODE1".MODE_1.SM.CR_EXT_SUMMER;
      SPBNB _07d;
      L     "DB_POWER_SAVING_MODE1".MODE_1.PV.SP.CR_ASU_EXT_SUMMER_T;
      T     "DB_POWER_SAVING_MODE1".MODE_1.PV.SP.CR_ASU_T;
      SET   ;
      SAVE  ;
      CLR   ;
_07d: U     BIE;
      )     ;
      SPBNB _07e;
      L     "DB_POWER_SAVING_MODE1".MODE_1.PV.SP.CR_ASU_EXT_SUMMER_H;
      T     "DB_POWER_SAVING_MODE1".MODE_1.PV.SP.CR_ASU_H;
_07e: NOP   0;
      U(    ;
      U     L     84.0;
      U     "DB_POWER_SAVING_MODE1".MODE_1.SM.CR_SUMMER;
      SPBNB _07f;
      L     "DB_POWER_SAVING_MODE1".MODE_1.PV.SP.CR_ASU_SUMMER_T;
      T     "DB_POWER_SAVING_MODE1".MODE_1.PV.SP.CR_ASU_T;
      SET   ;
      SAVE  ;
      CLR   ;
_07f: U     BIE;
      )     ;
      SPBNB _080;
      L     "DB_POWER_SAVING_MODE1".MODE_1.PV.SP.CR_ASU_SUMMER_H;
      T     "DB_POWER_SAVING_MODE1".MODE_1.PV.SP.CR_ASU_H;
_080: NOP   0;
      U(    ;
      U     L     84.0;
      U     "DB_POWER_SAVING_MODE1".MODE_1.SM.CR_TEMPERATE;
      SPBNB _081;
      L     "DB_POWER_SAVING_MODE1".MODE_1.PV.SP.CR_ASU_TEMPERATE_T;
      T     "DB_POWER_SAVING_MODE1".MODE_1.PV.SP.CR_ASU_T;
      SET   ;
      SAVE  ;
      CLR   ;
_081: U     BIE;
      )     ;
      SPBNB _082;
      L     "DB_POWER_SAVING_MODE1".MODE_1.PV.SP.CR_ASU_TEMPERATE_H;
      T     "DB_POWER_SAVING_MODE1".MODE_1.PV.SP.CR_ASU_H;
_082: NOP   0;
      U(    ;
      U     L     84.0;
      U     "DB_POWER_SAVING_MODE1".MODE_1.SM.CR_WINTER;
      SPBNB _083;
      L     "DB_POWER_SAVING_MODE1".MODE_1.PV.SP.CR_ASU_WINTER_T;
      T     "DB_POWER_SAVING_MODE1".MODE_1.PV.SP.CR_ASU_T;
      SET   ;
      SAVE  ;
      CLR   ;
_083: U     BIE;
      )     ;
      SPBNB _084;
      L     "DB_POWER_SAVING_MODE1".MODE_1.PV.SP.CR_ASU_WINTER_H;
      T     "DB_POWER_SAVING_MODE1".MODE_1.PV.SP.CR_ASU_H;
_084: NOP   0;
NETWORK
TITLE =DEFAULT MODE

      U     "DB_POWER_SAVING_MODE1".GENERAL.SM.CR_MODE_1_ON;
      UN    "DB_POWER_SAVING_MODE1".MODE_1.SM.CR_EXT_SUMMER;
      UN    "DB_POWER_SAVING_MODE1".MODE_1.SM.CR_SUMMER;
      UN    "DB_POWER_SAVING_MODE1".MODE_1.SM.CR_TEMPERATE;
      UN    "DB_POWER_SAVING_MODE1".MODE_1.SM.CR_WINTER;
      S     "DB_POWER_SAVING_MODE1".MODE_1.SM.CR_TEMPERATE;
NETWORK
TITLE =SETPOINTS TRANSFER

      U(    ;
      U     "LOG_1";
      U     "DB_POWER_SAVING_MODE1".GENERAL.SM.CR_MODE_1_ON;
      SPBNB _085;
      L     "DB_POWER_SAVING_MODE1".MODE_1.PV.SP.CR_ASU_T;
      T     "DB_GRP_84".CLT81.PV.SP_AV;
      SET   ;
      SAVE  ;
      CLR   ;
_085: U     BIE;
      )     ;
      SPBNB _086;
      L     "DB_POWER_SAVING_MODE1".MODE_1.PV.SP.CR_ASU_H;
      T     "DB_GRP_84".CLM82_HUM.PV.SP_AV;
_086: NOP   0;
NETWORK
TITLE =CLEAN ROOM - POWER SAVING MODE 2 ON/OFF
//********************************************************************************
//
//                           CLEAN ROOM POWER SAVING MODE 2
//
//********************************************************************************
//
      U     "DB_POWER_SAVING_MODE2".GENERAL.CTRL.CR_MODE_2_ON;
      S     "DB_POWER_SAVING_MODE2".GENERAL.SM.CR_MODE_2_ON;
      U(    ;
      O     "DB_POWER_SAVING_MODE2".GENERAL.CTRL.CR_MODE_2_OFF;
      O     "DB_POWER_SAVING_MODE2".GENERAL.SM.SENSORS_FAULT;
      )     ;
      R     "DB_POWER_SAVING_MODE2".GENERAL.SM.CR_MODE_2_ON;
      NOP   0;
NETWORK
TITLE =OUTSIDE CONDITIONS

      U     "DB_POWER_SAVING_MODE2".GENERAL.SM.CR_MODE_2_ON;
      U(    ;
      U     "DB_PROG_CLEAN_ROOM".CLEAN_ROOM.SM.ON;
      UN    "DB_PROG_CLEAN_ROOM".CLEAN_ROOM.SM.START;
      O     ;
      UN    "DB_PROG_CLEAN_ROOM".CLEAN_ROOM.SM.ON;
      U     "DB_PROG_CLEAN_ROOM".CLEAN_ROOM.SM.STOP;
      UN    "T_CR_FOLLOW_UP_PURING";
      )     ;
      =     L     84.0;
      U     L     84.0;
      U(    ;
      L     "DB_POWER_SAVING_MODE2".GENERAL.PV.AVG_TEMP;
      L     "DB_POWER_SAVING_MODE2".GENERAL.SP.CR_ASU_WINDOW_T_MIN;
      >=R   ;
      )     ;
      U(    ;
      L     "DB_POWER_SAVING_MODE2".GENERAL.PV.AVG_TEMP;
      L     "DB_POWER_SAVING_MODE2".GENERAL.SP.CR_ASU_WINDOW_T_MAX;
      <=R   ;
      )     ;
      =     L     84.1;
      U     L     84.1;
      U(    ;
      L     "DB_POWER_SAVING_MODE2".GENERAL.PV.AVG_HUM;
      L     "DB_POWER_SAVING_MODE2".GENERAL.SP.CR_ASU_WINDOW_H_MIN;
      >=R   ;
      )     ;
      U(    ;
      L     "DB_POWER_SAVING_MODE2".GENERAL.PV.AVG_HUM;
      L     "DB_POWER_SAVING_MODE2".GENERAL.SP.CR_ASU_WINDOW_H_MAX;
      <=R   ;
      )     ;
      =     "DB_POWER_SAVING_MODE2".CONDITIONS.CR_C0;
      U     L     84.1;
      U(    ;
      L     "DB_POWER_SAVING_MODE2".GENERAL.PV.AVG_HUM;
      L     "DB_POWER_SAVING_MODE2".GENERAL.SP.CR_ASU_WINDOW_H_MIN;
      <R    ;
      )     ;
      =     "DB_POWER_SAVING_MODE2".CONDITIONS.CR_C2;
      U     L     84.1;
      U(    ;
      L     "DB_POWER_SAVING_MODE2".GENERAL.PV.AVG_HUM;
      L     "DB_POWER_SAVING_MODE2".GENERAL.SP.CR_ASU_WINDOW_H_MAX;
      >R    ;
      )     ;
      =     "DB_POWER_SAVING_MODE2".CONDITIONS.CR_C6;
      U     L     84.0;
      U(    ;
      L     "DB_POWER_SAVING_MODE2".GENERAL.PV.AVG_HUM;
      L     "DB_POWER_SAVING_MODE2".GENERAL.SP.CR_ASU_WINDOW_H_MIN;
      >=R   ;
      )     ;
      U(    ;
      L     "DB_POWER_SAVING_MODE2".GENERAL.PV.AVG_HUM;
      L     "DB_POWER_SAVING_MODE2".GENERAL.SP.CR_ASU_WINDOW_H_MAX;
      <=R   ;
      )     ;
      =     L     84.1;
      U     L     84.1;
      U(    ;
      L     "DB_POWER_SAVING_MODE2".GENERAL.PV.AVG_TEMP;
      L     "DB_POWER_SAVING_MODE2".GENERAL.SP.CR_ASU_WINDOW_T_MIN;
      <R    ;
      )     ;
      =     "DB_POWER_SAVING_MODE2".CONDITIONS.CR_C8;
      U     L     84.1;
      U(    ;
      L     "DB_POWER_SAVING_MODE2".GENERAL.PV.AVG_TEMP;
      L     "DB_POWER_SAVING_MODE2".GENERAL.SP.CR_ASU_WINDOW_T_MAX;
      >R    ;
      )     ;
      =     "DB_POWER_SAVING_MODE2".CONDITIONS.CR_C4;
      U     L     84.0;
      U(    ;
      L     "DB_POWER_SAVING_MODE2".GENERAL.PV.AVG_TEMP;
      L     "DB_POWER_SAVING_MODE2".GENERAL.SP.CR_ASU_WINDOW_T_MIN;
      <R    ;
      )     ;
      =     L     84.1;
      U     L     84.1;
      U(    ;
      L     "DB_POWER_SAVING_MODE2".GENERAL.PV.AVG_HUM;
      L     "DB_POWER_SAVING_MODE2".GENERAL.SP.CR_ASU_WINDOW_H_MIN;
      <R    ;
      )     ;
      =     "DB_POWER_SAVING_MODE2".CONDITIONS.CR_C1;
      U     L     84.1;
      U(    ;
      L     "DB_POWER_SAVING_MODE2".GENERAL.PV.AVG_HUM;
      L     "DB_POWER_SAVING_MODE2".GENERAL.SP.CR_ASU_WINDOW_H_MAX;
      >R    ;
      )     ;
      =     "DB_POWER_SAVING_MODE2".CONDITIONS.CR_C7;
      U     L     84.0;
      U(    ;
      L     "DB_POWER_SAVING_MODE2".GENERAL.PV.AVG_TEMP;
      L     "DB_POWER_SAVING_MODE2".GENERAL.SP.CR_ASU_WINDOW_T_MAX;
      >R    ;
      )     ;
      =     L     84.1;
      U     L     84.1;
      U(    ;
      L     "DB_POWER_SAVING_MODE2".GENERAL.PV.AVG_HUM;
      L     "DB_POWER_SAVING_MODE2".GENERAL.SP.CR_ASU_WINDOW_H_MIN;
      <R    ;
      )     ;
      =     "DB_POWER_SAVING_MODE2".CONDITIONS.CR_C3;
      U     L     84.1;
      U(    ;
      L     "DB_POWER_SAVING_MODE2".GENERAL.PV.AVG_HUM;
      L     "DB_POWER_SAVING_MODE2".GENERAL.SP.CR_ASU_WINDOW_H_MAX;
      >R    ;
      )     ;
      =     "DB_POWER_SAVING_MODE2".CONDITIONS.CR_C5;
      U     L     84.0;
      NOT   ;
      R     "DB_POWER_SAVING_MODE2".MODE.CR_ASU_HEATING;
      R     "DB_POWER_SAVING_MODE2".MODE.CR_ASU_COOLING;
      R     "DB_POWER_SAVING_MODE2".MODE.CR_ASU_HUMIDIFYING;
      R     "DB_POWER_SAVING_MODE2".MODE.CR_ASU_DEHUMIDIFYING;
NETWORK
TITLE =ASU SWITCHING POINTS

      U     "LOG_1";
      =     L     84.0;
      U     L     84.0;
      SPBNB _087;
      L     "DB_POWER_SAVING_MODE2".GENERAL.SP.CR_ASU_WINDOW_T_MIN;
      L     1.000000e+000;
      +R    ;
      T     #SW_CR_ASU_STOP_HEATING;
_087: NOP   0;
      U     L     84.0;
      SPBNB _088;
      L     "DB_POWER_SAVING_MODE2".GENERAL.SP.CR_ASU_WINDOW_T_MIN;
      L     5.000000e-001;
      +R    ;
      T     #SW_CR_ASU_START_HEATING;
_088: NOP   0;
      U     L     84.0;
      SPBNB _089;
      L     "DB_POWER_SAVING_MODE2".GENERAL.SP.CR_ASU_WINDOW_T_MAX;
      L     1.000000e+000;
      -R    ;
      T     #SW_CR_ASU_STOP_COOLING;
_089: NOP   0;
      U     L     84.0;
      SPBNB _08a;
      L     "DB_POWER_SAVING_MODE2".GENERAL.SP.CR_ASU_WINDOW_H_MIN;
      L     1.000000e+000;
      +R    ;
      T     #SW_CR_ASU_STOP_HUM;
_08a: NOP   0;
      U     L     84.0;
      SPBNB _08b;
      L     "DB_POWER_SAVING_MODE2".GENERAL.SP.CR_ASU_WINDOW_H_MAX;
      L     1.500000e+000;
      -R    ;
      T     #SW_CR_ASU_STOP_DEHUM;
_08b: NOP   0;
      U     L     84.0;
      SPBNB _08c;
      L     "DB_POWER_SAVING_MODE2".GENERAL.SP.CR_ASU_WINDOW_H_MIN;
      L     1.000000e+000;
      -R    ;
      T     #SW_CR_ASU_START_COOLING;
_08c: NOP   0;
NETWORK
TITLE =ASU CONDIDITON 0
//OUTSIDE TEMP. AND HUMIDITY IN WINDOW
//
//HEATING OFF
//COOLING OFF
//HUMIDIFYING OFF
//DEHUMIDIFYING OFF
      U     "DB_POWER_SAVING_MODE2".CONDITIONS.CR_C0;
      =     L     84.0;
      U     L     84.0;
      U     "DB_POWER_SAVING_MODE2".MODE.CR_ASU_HEATING;
      U     "DB_GRP_84".VA51.SM.Close;
      U(    ;
      L     "DB_GRP_84".PP51.PV.AV;
      L     8.000000e+000;
      <R    ;
      )     ;
      U(    ;
      L     "DB_GRP_84".CLT81.PV.AV;
      L     #SW_CR_ASU_STOP_HEATING;
      >R    ;
      )     ;
      L     S5T#40S;
      SE    "T_PS_M2_CR_HEAT_OFF_C0";
      NOP   0;
      NOP   0;
      NOP   0;
      NOP   0;
      U     L     84.0;
      U(    ;
      L     "DB_GRP_84".CLT81.PV.AV;
      L     "DB_POWER_SAVING_MODE2".GENERAL.SP.CR_ASU_WINDOW_T_MIN;
      <R    ;
      )     ;
      S     "DB_POWER_SAVING_MODE2".MODE.CR_ASU_HEATING;
      U     L     84.0;
      U(    ;
      O     "DB_POWER_SAVING_MODE2".MODE.CR_ASU_COOLING;
      O     "T_PS_M2_CR_HEAT_OFF_C0";
      )     ;
      R     "DB_POWER_SAVING_MODE2".MODE.CR_ASU_HEATING;
      U     L     84.0;
      U     "DB_POWER_SAVING_MODE2".MODE.CR_ASU_COOLING;
      U(    ;
      L     "DB_GRP_84".CLT81.PV.AV;
      L     #SW_CR_ASU_STOP_COOLING;
      <R    ;
      )     ;
      L     S5T#1M;
      SE    "T_PS_M2_CR_COOL_OFF_C0";
      NOP   0;
      NOP   0;
      NOP   0;
      NOP   0;
      U     L     84.0;
      U(    ;
      U     "DB_POWER_SAVING_MODE2".MODE.CR_ASU_DEHUMIDIFYING;
      U(    ;
      L     "DB_GRP_84".CLM82_HUM.PV.AV;
      L     "DB_POWER_SAVING_MODE2".GENERAL.SP.CR_ASU_WINDOW_H_MAX;
      <=R   ;
      )     ;
      U(    ;
      L     "DB_GRP_84".CLT81.PV.AV;
      L     "DB_POWER_SAVING_MODE2".GENERAL.SP.CR_ASU_WINDOW_T_MAX;
      >R    ;
      )     ;
      UN    "DB_GRP_84".VA41.SM.Open;
      O     ;
      UN    "DB_POWER_SAVING_MODE2".MODE.CR_ASU_DEHUMIDIFYING;
      U(    ;
      L     "DB_GRP_84".CLT81.PV.AV;
      L     "DB_POWER_SAVING_MODE2".GENERAL.SP.CR_ASU_WINDOW_T_MAX;
      >R    ;
      )     ;
      )     ;
      S     "DB_POWER_SAVING_MODE2".MODE.CR_ASU_COOLING;
      U     L     84.0;
      U(    ;
      O     "DB_POWER_SAVING_MODE2".MODE.CR_ASU_DEHUMIDIFYING;
      O     "DB_POWER_SAVING_MODE2".MODE.CR_ASU_HEATING;
      O     "T_PS_M2_CR_COOL_OFF_C0";
      )     ;
      R     "DB_POWER_SAVING_MODE2".MODE.CR_ASU_COOLING;
      U     L     84.0;
      U     "DB_POWER_SAVING_MODE2".MODE.CR_ASU_HUMIDIFYING;
      U(    ;
      L     "DB_GRP_84".CLM82_HUM.PV.AV;
      L     #SW_CR_ASU_STOP_HUM;
      >R    ;
      )     ;
      U(    ;
      L     "DB_GRP_84".PP61.PV.Frq_AV;
      L     7.500000e+000;
      <R    ;
      )     ;
      L     S5T#40S;
      SE    "T_PS_M2_CR_HUM_OFF_C0";
      NOP   0;
      NOP   0;
      NOP   0;
      NOP   0;
      U     L     84.0;
      U(    ;
      O     "DB_POWER_SAVING_MODE2".MODE.CR_ASU_DEHUMIDIFYING;
      O     "T_PS_M2_CR_HUM_OFF_C0";
      )     ;
      R     "DB_POWER_SAVING_MODE2".MODE.CR_ASU_HUMIDIFYING;
      U     L     84.0;
      U(    ;
      L     "DB_GRP_84".CLM82_HUM.PV.AV;
      L     "DB_POWER_SAVING_MODE2".GENERAL.SP.CR_ASU_WINDOW_H_MIN;
      <R    ;
      )     ;
      S     "DB_POWER_SAVING_MODE2".MODE.CR_ASU_HUMIDIFYING;
      U     L     84.0;
      U     "DB_POWER_SAVING_MODE2".MODE.CR_ASU_DEHUMIDIFYING;
      U(    ;
      L     "DB_GRP_84".CLM82_HUM.PV.AV;
      L     #SW_CR_ASU_STOP_DEHUM;
      <R    ;
      )     ;
      L     S5T#1M;
      SE    "T_PS_M2_CR_DEHUM_OFF_C0";
      NOP   0;
      NOP   0;
      NOP   0;
      NOP   0;
      U     L     84.0;
      U(    ;
      O     "DB_POWER_SAVING_MODE2".MODE.CR_ASU_COOLING;
      O     "DB_POWER_SAVING_MODE2".MODE.CR_ASU_HUMIDIFYING;
      O     "T_PS_M2_CR_DEHUM_OFF_C0";
      )     ;
      R     "DB_POWER_SAVING_MODE2".MODE.CR_ASU_DEHUMIDIFYING;
      U     L     84.0;
      U(    ;
      U     "DB_POWER_SAVING_MODE2".MODE.CR_ASU_COOLING;
      U(    ;
      L     "DB_GRP_84".CLT81.PV.AV;
      L     "DB_POWER_SAVING_MODE2".GENERAL.SP.CR_ASU_WINDOW_T_MAX;
      <=R   ;
      )     ;
      U(    ;
      L     "DB_GRP_84".CLM82_HUM.PV.AV;
      L     "DB_POWER_SAVING_MODE2".GENERAL.SP.CR_ASU_WINDOW_H_MAX;
      >R    ;
      )     ;
      UN    "DB_GRP_84".VA41.SM.Open;
      O     ;
      UN    "DB_POWER_SAVING_MODE2".MODE.CR_ASU_COOLING;
      U(    ;
      L     "DB_GRP_84".CLM82_HUM.PV.AV;
      L     "DB_POWER_SAVING_MODE2".GENERAL.SP.CR_ASU_WINDOW_H_MAX;
      >R    ;
      )     ;
      )     ;
      S     "DB_POWER_SAVING_MODE2".MODE.CR_ASU_DEHUMIDIFYING;
      U     L     84.0;
      U     "DB_POWER_SAVING_MODE2".MODE.CR_ASU_COOLING;
      SPBNB _08d;
      L     "DB_POWER_SAVING_MODE2".GENERAL.SP.CR_ASU_WINDOW_T_MAX;
      T     "DB_POWER_SAVING_MODE2".GENERAL.SP.CR_ASU_T;
_08d: NOP   0;
      U     L     84.0;
      U     "DB_POWER_SAVING_MODE2".MODE.CR_ASU_HEATING;
      SPBNB _08e;
      L     "DB_POWER_SAVING_MODE2".GENERAL.SP.CR_ASU_WINDOW_T_MIN;
      T     "DB_POWER_SAVING_MODE2".GENERAL.SP.CR_ASU_T;
_08e: NOP   0;
      U     L     84.0;
      UN    "DB_POWER_SAVING_MODE2".MODE.CR_ASU_COOLING;
      UN    "DB_POWER_SAVING_MODE2".MODE.CR_ASU_HEATING;
      SPBNB _08f;
      L     "DB_GRP_84".CLT81.PV.AV;
      T     "DB_POWER_SAVING_MODE2".GENERAL.SP.CR_ASU_T;
_08f: NOP   0;
      U     L     84.0;
      U     "DB_POWER_SAVING_MODE2".MODE.CR_ASU_DEHUMIDIFYING;
      SPBNB _090;
      L     "DB_POWER_SAVING_MODE2".GENERAL.SP.CR_ASU_WINDOW_H_MAX;
      T     "DB_POWER_SAVING_MODE2".GENERAL.SP.CR_ASU_H;
_090: NOP   0;
      U     L     84.0;
      U     "DB_POWER_SAVING_MODE2".MODE.CR_ASU_HUMIDIFYING;
      SPBNB _091;
      L     "DB_POWER_SAVING_MODE2".GENERAL.SP.CR_ASU_WINDOW_H_MIN;
      T     "DB_POWER_SAVING_MODE2".GENERAL.SP.CR_ASU_H;
_091: NOP   0;
      U     L     84.0;
      UN    "DB_POWER_SAVING_MODE2".MODE.CR_ASU_DEHUMIDIFYING;
      UN    "DB_POWER_SAVING_MODE2".MODE.CR_ASU_HUMIDIFYING;
      SPBNB _092;
      L     "DB_GRP_84".CLM82_HUM.PV.AV;
      T     "DB_POWER_SAVING_MODE2".GENERAL.SP.CR_ASU_H;
_092: NOP   0;
NETWORK
TITLE =ASU CONDIDITON 1
//OUTSIDE TEMPERATURE < T MIN, OUTSIDE HUMIDITY < H MIN
//
//HEATING ON
//COOLING OFF
//HUMIDIFYING ON
//DEHUMIDIFYING OFF
//UNTIL WINDOW IS REACHED
//
//HEATING SP T MIN
//HUMIDIFYING SP H MIN
      U     "DB_POWER_SAVING_MODE2".CONDITIONS.CR_C1;
      =     L     84.0;
      U     L     84.0;
      U(    ;
      L     "DB_GRP_84".CLT81.PV.AV;
      L     "DB_POWER_SAVING_MODE2".GENERAL.SP.CR_ASU_WINDOW_T_MIN;
      <R    ;
      )     ;
      S     "DB_POWER_SAVING_MODE2".MODE.CR_ASU_HEATING;
      U     L     84.0;
      U     "DB_POWER_SAVING_MODE2".MODE.CR_ASU_HEATING;
      U     "DB_GRP_84".VA51.SM.Close;
      U(    ;
      L     "DB_GRP_84".PP51.PV.AV;
      L     7.500000e+000;
      <=R   ;
      )     ;
      U(    ;
      L     "DB_GRP_84".CLT81.PV.AV;
      L     #SW_CR_ASU_STOP_HEATING;
      >R    ;
      )     ;
      L     S5T#2M;
      SE    "T_PS_M2_CR_HEAT_OFF_C1";
      NOP   0;
      NOP   0;
      NOP   0;
      U     "T_PS_M2_CR_HEAT_OFF_C1";
      R     "DB_POWER_SAVING_MODE2".MODE.CR_ASU_HEATING;
      U     L     84.0;
      BLD   102;
      R     "DB_POWER_SAVING_MODE2".MODE.CR_ASU_COOLING;
      U     L     84.0;
      BLD   102;
      S     "DB_POWER_SAVING_MODE2".MODE.CR_ASU_HUMIDIFYING;
      U     L     84.0;
      BLD   102;
      R     "DB_POWER_SAVING_MODE2".MODE.CR_ASU_DEHUMIDIFYING;
      U     L     84.0;
      U     "DB_POWER_SAVING_MODE2".MODE.CR_ASU_HEATING;
      SPBNB _093;
      L     "DB_POWER_SAVING_MODE2".GENERAL.SP.CR_ASU_WINDOW_T_MIN;
      T     "DB_POWER_SAVING_MODE2".GENERAL.SP.CR_ASU_T;
_093: NOP   0;
      U     L     84.0;
      UN    "DB_POWER_SAVING_MODE2".MODE.CR_ASU_HEATING;
      SPBNB _094;
      L     "DB_GRP_84".CLT81.PV.AV;
      T     "DB_POWER_SAVING_MODE2".GENERAL.SP.CR_ASU_T;
_094: NOP   0;
      U     L     84.0;
      SPBNB _095;
      L     "DB_POWER_SAVING_MODE2".GENERAL.SP.CR_ASU_WINDOW_H_MIN;
      T     "DB_POWER_SAVING_MODE2".GENERAL.SP.CR_ASU_H;
_095: NOP   0;
NETWORK
TITLE =ASU CONDITION 2
//OUTSIDE TEMPERATURE IN WINDOW, OUTSIDE HUMIDITY < H MIN
//
//HEATING ON (ONLY IF TEMPERATURE GOES DOWN BECAUSE OF HUMIDIFYING)
//COOLING OFF
//HUMIDIFYING ON
//DEHUMIDIFIYNG OFF
//UNTIL WINDOW IS REACHED
//
//HEATING SP T MIN
//HUMIDIFYING SP H MIN
      U     "DB_POWER_SAVING_MODE2".CONDITIONS.CR_C2;
      =     L     84.0;
      U     L     84.0;
      U(    ;
      L     "DB_GRP_84".CLT81.PV.AV;
      L     "DB_POWER_SAVING_MODE2".GENERAL.SP.CR_ASU_WINDOW_T_MIN;
      <R    ;
      )     ;
      S     "DB_POWER_SAVING_MODE2".MODE.CR_ASU_HEATING;
      U     L     84.0;
      U     "DB_POWER_SAVING_MODE2".MODE.CR_ASU_HEATING;
      U     "DB_GRP_84".VA51.SM.Close;
      U(    ;
      L     "DB_GRP_84".PP51.PV.AV;
      L     8.000000e+000;
      <=R   ;
      )     ;
      U(    ;
      L     "DB_GRP_84".CLT81.PV.AV;
      L     #SW_CR_ASU_STOP_HEATING;
      >R    ;
      )     ;
      L     S5T#40S;
      SE    "T_PS_M2_CR_HEAT_OFF_C2";
      NOP   0;
      NOP   0;
      NOP   0;
      U     "T_PS_M2_CR_HEAT_OFF_C2";
      R     "DB_POWER_SAVING_MODE2".MODE.CR_ASU_HEATING;
      U     L     84.0;
      U(    ;
      L     "DB_GRP_84".CLM82_HUM.PV.AV;
      L     "DB_POWER_SAVING_MODE2".GENERAL.SP.CR_ASU_WINDOW_H_MIN;
      <R    ;
      )     ;
      S     "DB_POWER_SAVING_MODE2".MODE.CR_ASU_HUMIDIFYING;
      U     L     84.0;
      U     "DB_POWER_SAVING_MODE2".MODE.CR_ASU_HUMIDIFYING;
      U(    ;
      L     "DB_GRP_84".CLM82_HUM.PV.AV;
      L     #SW_CR_ASU_STOP_HUM;
      >R    ;
      )     ;
      U(    ;
      L     "DB_GRP_84".PP61.PV.Frq_AV;
      L     7.500000e+000;
      <R    ;
      )     ;
      L     S5T#1M;
      SE    "T_PS_M2_CR_HUM_OFF_C2";
      NOP   0;
      NOP   0;
      NOP   0;
      U     "T_PS_M2_CR_HUM_OFF_C2";
      R     "DB_POWER_SAVING_MODE2".MODE.CR_ASU_HUMIDIFYING;
      U     L     84.0;
      BLD   102;
      R     "DB_POWER_SAVING_MODE2".MODE.CR_ASU_DEHUMIDIFYING;
      U     L     84.0;
      BLD   102;
      R     "DB_POWER_SAVING_MODE2".MODE.CR_ASU_COOLING;
      U     L     84.0;
      U     "DB_POWER_SAVING_MODE2".MODE.CR_ASU_HEATING;
      SPBNB _096;
      L     "DB_POWER_SAVING_MODE2".GENERAL.SP.CR_ASU_WINDOW_T_MIN;
      T     "DB_POWER_SAVING_MODE2".GENERAL.SP.CR_ASU_T;
_096: NOP   0;
      U     L     84.0;
      UN    "DB_POWER_SAVING_MODE2".MODE.CR_ASU_HEATING;
      SPBNB _097;
      L     "DB_GRP_84".CLT81.PV.AV;
      T     "DB_POWER_SAVING_MODE2".GENERAL.SP.CR_ASU_T;
_097: NOP   0;
      U     L     84.0;
      U     "DB_POWER_SAVING_MODE2".MODE.CR_ASU_HUMIDIFYING;
      SPBNB _098;
      L     "DB_POWER_SAVING_MODE2".GENERAL.SP.CR_ASU_WINDOW_H_MIN;
      T     "DB_POWER_SAVING_MODE2".GENERAL.SP.CR_ASU_H;
_098: NOP   0;
      U     L     84.0;
      UN    "DB_POWER_SAVING_MODE2".MODE.CR_ASU_HUMIDIFYING;
      SPBNB _099;
      L     "DB_GRP_84".CLM82_HUM.PV.AV;
      T     "DB_POWER_SAVING_MODE2".GENERAL.SP.CR_ASU_H;
_099: NOP   0;
NETWORK
TITLE =ASU CONDITION 3
//OUTSIDE TEMPERATURE > T MAX, OUTSIDE HUMIDITY < H MIN
//
//HEATING ON (ONLY IF TEMPERATURE GOES DOWN BECAUSE OF HUMIDIFYING)
//COOLING ON (IF CONDITIONS ARE NOT REACHED USING ONLY HUMIDIFYING)
//HUMIDIFYING ON
//DEHUMIDIFYING OFF
//UNTIL WINDOW IS REACHED
//
//HEATING SP T MIN (HEATING), T MAX (COOLING)
//HUMIDIFYING SP H MIN
      U     "DB_POWER_SAVING_MODE2".CONDITIONS.CR_C3;
      =     L     84.0;
      U     L     84.0;
      U     "DB_POWER_SAVING_MODE2".MODE.CR_ASU_HEATING;
      U     "DB_GRP_84".VA51.SM.Close;
      U(    ;
      L     "DB_GRP_84".PP51.PV.AV;
      L     8.000000e+000;
      <R    ;
      )     ;
      U(    ;
      L     "DB_GRP_84".CLT81.PV.AV;
      L     #SW_CR_ASU_STOP_HEATING;
      >R    ;
      )     ;
      L     S5T#40S;
      SE    "T_PS_M2_CR_HEAT_OFF_C3";
      NOP   0;
      NOP   0;
      NOP   0;
      NOP   0;
      U     L     84.0;
      U(    ;
      O     "DB_POWER_SAVING_MODE2".MODE.CR_ASU_COOLING;
      O     "T_PS_M2_CR_HEAT_OFF_C3";
      )     ;
      R     "DB_POWER_SAVING_MODE2".MODE.CR_ASU_HEATING;
      U     L     84.0;
      U(    ;
      L     "DB_GRP_84".CLT81.PV.AV;
      L     "DB_POWER_SAVING_MODE2".GENERAL.SP.CR_ASU_WINDOW_T_MIN;
      <R    ;
      )     ;
      S     "DB_POWER_SAVING_MODE2".MODE.CR_ASU_HEATING;
      U     L     84.0;
      U(    ;
      L     "DB_GRP_84".CLM82_HUM.PV.AV;
      L     "DB_POWER_SAVING_MODE2".GENERAL.SP.CR_ASU_WINDOW_H_MIN;
      <R    ;
      )     ;
      S     "DB_POWER_SAVING_MODE2".MODE.CR_ASU_HUMIDIFYING;
      U     L     84.0;
      U     "DB_POWER_SAVING_MODE2".MODE.CR_ASU_HUMIDIFYING;
      U(    ;
      L     "DB_GRP_84".CLM82_HUM.PV.AV;
      L     #SW_CR_ASU_STOP_HUM;
      >R    ;
      )     ;
      U(    ;
      L     "DB_GRP_84".PP61.PV.Frq_AV;
      L     7.500000e+000;
      <R    ;
      )     ;
      L     S5T#1M;
      SE    "T_PS_M2_CR_HUM_OFF_C3";
      NOP   0;
      NOP   0;
      NOP   0;
      U     "T_PS_M2_CR_HUM_OFF_C3";
      R     "DB_POWER_SAVING_MODE2".MODE.CR_ASU_HUMIDIFYING;
      U     L     84.0;
      BLD   102;
      R     "DB_POWER_SAVING_MODE2".MODE.CR_ASU_DEHUMIDIFYING;
      U     L     84.0;
      U     "DB_POWER_SAVING_MODE2".MODE.CR_ASU_COOLING;
      U(    ;
      L     "DB_GRP_84".CLT81.PV.AV;
      L     #SW_CR_ASU_STOP_COOLING;
      <R    ;
      )     ;
      L     S5T#2M;
      SE    "T_PS_M2_CR_COOL_OFF_C3";
      NOP   0;
      NOP   0;
      NOP   0;
      NOP   0;
      U     L     84.0;
      U(    ;
      O     "DB_POWER_SAVING_MODE2".MODE.CR_ASU_HEATING;
      O     "T_PS_M2_CR_COOL_OFF_C3";
      )     ;
      R     "DB_POWER_SAVING_MODE2".MODE.CR_ASU_COOLING;
      U     L     84.0;
      U(    ;
      U(    ;
      L     "DB_GRP_84".CLM82_HUM.PV.AV;
      L     "DB_POWER_SAVING_MODE2".GENERAL.SP.CR_ASU_WINDOW_H_MIN;
      >=R   ;
      )     ;
      U(    ;
      L     "DB_GRP_84".CLT81.PV.AV;
      L     "DB_POWER_SAVING_MODE2".GENERAL.SP.CR_ASU_WINDOW_T_MAX;
      >R    ;
      )     ;
      O     "DB_GRP_84".PP61.SM.GeneralError;
      O     "DB_GRP_84".PP61.SM.ManualMode;
      O     "DB_DIGIT".FM.G84_FIL63_B22_1;
      )     ;
      S     "DB_POWER_SAVING_MODE2".MODE.CR_ASU_COOLING;
      U     L     84.0;
      U     "DB_POWER_SAVING_MODE2".MODE.CR_ASU_HEATING;
      SPBNB _09a;
      L     "DB_POWER_SAVING_MODE2".GENERAL.SP.CR_ASU_WINDOW_T_MIN;
      T     "DB_POWER_SAVING_MODE2".GENERAL.SP.CR_ASU_T;
_09a: NOP   0;
      U     L     84.0;
      U     "DB_POWER_SAVING_MODE2".MODE.CR_ASU_COOLING;
      SPBNB _09b;
      L     "DB_POWER_SAVING_MODE2".GENERAL.SP.CR_ASU_WINDOW_T_MAX;
      T     "DB_POWER_SAVING_MODE2".GENERAL.SP.CR_ASU_T;
_09b: NOP   0;
      U     L     84.0;
      U     "DB_POWER_SAVING_MODE2".MODE.CR_ASU_HUMIDIFYING;
      SPBNB _09c;
      L     "DB_POWER_SAVING_MODE2".GENERAL.SP.CR_ASU_WINDOW_H_MIN;
      T     "DB_POWER_SAVING_MODE2".GENERAL.SP.CR_ASU_H;
_09c: NOP   0;
      U     L     84.0;
      UN    "DB_POWER_SAVING_MODE2".MODE.CR_ASU_HUMIDIFYING;
      SPBNB _09d;
      L     "DB_GRP_84".CLM82_HUM.PV.AV;
      T     "DB_POWER_SAVING_MODE2".GENERAL.SP.CR_ASU_H;
_09d: NOP   0;
      U     L     84.0;
      UN    "DB_POWER_SAVING_MODE2".MODE.CR_ASU_HEATING;
      UN    "DB_POWER_SAVING_MODE2".MODE.CR_ASU_COOLING;
      SPBNB _09e;
      L     "DB_GRP_84".CLT81.PV.AV;
      T     "DB_POWER_SAVING_MODE2".GENERAL.SP.CR_ASU_T;
_09e: NOP   0;
NETWORK
TITLE =ASU CONDITION 4
//OUTSIDE TEMPERATURE > T MAX, OUTSIDE HUMIDITY IN WINDOW
//
//HEATING OFF
//COOLING ON
//HUMIDIFYING ON (ONLY IF HUMIDITY GOES DOWN BECAUSE OF COOLING)
//DEHUMIDIFYING OFF
//UNTIL WINDOW IS REACHED
//
//COOLING SP T MAX
//HUMIDIFYING SP H MIN
      U     "DB_POWER_SAVING_MODE2".CONDITIONS.CR_C4;
      =     L     84.0;
      U     L     84.0;
      BLD   102;
      R     "DB_POWER_SAVING_MODE2".MODE.CR_ASU_HEATING;
      U     L     84.0;
      U(    ;
      L     "DB_GRP_84".CLT81.PV.AV;
      L     "DB_POWER_SAVING_MODE2".GENERAL.SP.CR_ASU_WINDOW_T_MAX;
      >R    ;
      )     ;
      S     "DB_POWER_SAVING_MODE2".MODE.CR_ASU_COOLING;
      U     L     84.0;
      U     "DB_POWER_SAVING_MODE2".MODE.CR_ASU_COOLING;
      U     "DB_GRP_84".VA41.SM.Close;
      U(    ;
      L     "DB_GRP_84".CLT81.PV.AV;
      L     #SW_CR_ASU_STOP_COOLING;
      <R    ;
      )     ;
      R     "DB_POWER_SAVING_MODE2".MODE.CR_ASU_COOLING;
      U     L     84.0;
      U(    ;
      L     "DB_GRP_84".CLM82_HUM.PV.AV;
      L     "DB_POWER_SAVING_MODE2".GENERAL.SP.CR_ASU_WINDOW_H_MIN;
      <R    ;
      )     ;
      S     "DB_POWER_SAVING_MODE2".MODE.CR_ASU_HUMIDIFYING;
      U     L     84.0;
      U     "DB_POWER_SAVING_MODE2".MODE.CR_ASU_HUMIDIFYING;
      U(    ;
      L     "DB_GRP_84".CLM82_HUM.PV.AV;
      L     #SW_CR_ASU_STOP_HUM;
      >R    ;
      )     ;
      U(    ;
      L     "DB_GRP_84".PP61.PV.Frq_AV;
      L     7.500000e+000;
      <R    ;
      )     ;
      L     S5T#40S;
      SE    "T_PS_M2_CR_HUM_OFF_C4";
      NOP   0;
      NOP   0;
      NOP   0;
      U     "T_PS_M2_CR_HUM_OFF_C4";
      R     "DB_POWER_SAVING_MODE2".MODE.CR_ASU_HUMIDIFYING;
      U     L     84.0;
      BLD   102;
      R     "DB_POWER_SAVING_MODE2".MODE.CR_ASU_DEHUMIDIFYING;
      U     L     84.0;
      U     "DB_POWER_SAVING_MODE2".MODE.CR_ASU_COOLING;
      SPBNB _09f;
      L     "DB_POWER_SAVING_MODE2".GENERAL.SP.CR_ASU_WINDOW_T_MAX;
      T     "DB_POWER_SAVING_MODE2".GENERAL.SP.CR_ASU_T;
_09f: NOP   0;
      U     L     84.0;
      UN    "DB_POWER_SAVING_MODE2".MODE.CR_ASU_COOLING;
      SPBNB _0a0;
      L     "DB_GRP_84".CLT81.PV.AV;
      T     "DB_POWER_SAVING_MODE2".GENERAL.SP.CR_ASU_T;
_0a0: NOP   0;
      U     L     84.0;
      U     "DB_POWER_SAVING_MODE2".MODE.CR_ASU_HUMIDIFYING;
      SPBNB _0a1;
      L     "DB_POWER_SAVING_MODE2".GENERAL.SP.CR_ASU_WINDOW_H_MIN;
      T     "DB_POWER_SAVING_MODE2".GENERAL.SP.CR_ASU_H;
_0a1: NOP   0;
      U     L     84.0;
      UN    "DB_POWER_SAVING_MODE2".MODE.CR_ASU_HUMIDIFYING;
      SPBNB _0a2;
      L     "DB_GRP_84".CLM82_HUM.PV.AV;
      T     "DB_POWER_SAVING_MODE2".GENERAL.SP.CR_ASU_H;
_0a2: NOP   0;
NETWORK
TITLE =ASU CONDITION 5
//OUTSIDE TEMPERATURE > T MAX, OUTSIDE HUMIDITY > H MAX
//
//HEATING ON (ONLY IF TEMPERATURE GOES DOWN BECAUSE OF DEHUMIDIFYING)
//COOLING ON (WHEN NO DEHUMIDIFYING)
//HUMIDIFYING ON (ONLY IF HUMIDITY GOES DOWN BECAUSE OF COOLING)
//DEHUMIDIFYING (WHEN NO COOLING)
//UNTIL WINDOW IS REACHED
//
//COOLING SP T MAX
//HEATING SP T MIN
//HUMIDIFYING SP H MIN
//DEHUMIDIFYING SP H MAX
      U     "DB_POWER_SAVING_MODE2".CONDITIONS.CR_C5;
      =     L     84.0;
      U     L     84.0;
      U     "DB_POWER_SAVING_MODE2".MODE.CR_ASU_HEATING;
      U     "DB_GRP_84".VA51.SM.Close;
      U(    ;
      L     "DB_GRP_84".PP51.PV.AV;
      L     8.000000e+000;
      <R    ;
      )     ;
      U(    ;
      L     "DB_GRP_84".CLT81.PV.AV;
      L     #SW_CR_ASU_STOP_HEATING;
      >R    ;
      )     ;
      L     S5T#40S;
      SE    "T_PS_M2_CR_HEAT_OFF_C5";
      NOP   0;
      NOP   0;
      NOP   0;
      NOP   0;
      U     L     84.0;
      U(    ;
      O     "DB_POWER_SAVING_MODE2".MODE.CR_ASU_COOLING;
      O     "T_PS_M2_CR_HEAT_OFF_C5";
      )     ;
      R     "DB_POWER_SAVING_MODE2".MODE.CR_ASU_HEATING;
      U     L     84.0;
      UN    "DB_POWER_SAVING_MODE2".MODE.CR_ASU_COOLING;
      U(    ;
      L     "DB_GRP_84".CLT81.PV.AV;
      L     "DB_POWER_SAVING_MODE2".GENERAL.SP.CR_ASU_WINDOW_T_MIN;
      <R    ;
      )     ;
      S     "DB_POWER_SAVING_MODE2".MODE.CR_ASU_HEATING;
      U     L     84.0;
      U     "DB_POWER_SAVING_MODE2".MODE.CR_ASU_DEHUMIDIFYING;
      R     "DB_POWER_SAVING_MODE2".MODE.CR_ASU_COOLING;
      U     L     84.0;
      U(    ;
      U     "DB_POWER_SAVING_MODE2".MODE.CR_ASU_DEHUMIDIFYING;
      U(    ;
      L     "DB_GRP_84".CLM82_HUM.PV.AV;
      L     "DB_POWER_SAVING_MODE2".GENERAL.SP.CR_ASU_WINDOW_H_MAX;
      <=R   ;
      )     ;
      U(    ;
      L     "DB_GRP_84".CLT81.PV.AV;
      L     "DB_POWER_SAVING_MODE2".GENERAL.SP.CR_ASU_WINDOW_T_MAX;
      >R    ;
      )     ;
      UN    "DB_GRP_84".VA41.SM.Open;
      O     ;
      UN    "DB_POWER_SAVING_MODE2".MODE.CR_ASU_COOLING;
      UN    "DB_POWER_SAVING_MODE2".MODE.CR_ASU_DEHUMIDIFYING;
      )     ;
      S     "DB_POWER_SAVING_MODE2".MODE.CR_ASU_COOLING;
      U     L     84.0;
      U     "DB_POWER_SAVING_MODE2".MODE.CR_ASU_COOLING;
      U(    ;
      L     "DB_GRP_84".CLM82_HUM.PV.AV;
      L     "DB_POWER_SAVING_MODE2".GENERAL.SP.CR_ASU_WINDOW_H_MIN;
      <R    ;
      )     ;
      S     "DB_POWER_SAVING_MODE2".MODE.CR_ASU_HUMIDIFYING;
      U     L     84.0;
      U     "DB_POWER_SAVING_MODE2".MODE.CR_ASU_HUMIDIFYING;
      U(    ;
      L     "DB_GRP_84".CLM82_HUM.PV.AV;
      L     #SW_CR_ASU_STOP_HUM;
      >R    ;
      )     ;
      U(    ;
      L     "DB_GRP_84".PP61.PV.Frq_AV;
      L     7.500000e+000;
      <R    ;
      )     ;
      L     S5T#40S;
      SE    "T_PS_M2_CR_HUM_OFF_C5";
      NOP   0;
      NOP   0;
      NOP   0;
      NOP   0;
      U     L     84.0;
      U(    ;
      O     "DB_POWER_SAVING_MODE2".MODE.CR_ASU_DEHUMIDIFYING;
      O     "T_PS_M2_CR_HUM_OFF_C5";
      )     ;
      R     "DB_POWER_SAVING_MODE2".MODE.CR_ASU_HUMIDIFYING;
      U     L     84.0;
      U     "DB_POWER_SAVING_MODE2".MODE.CR_ASU_COOLING;
      R     "DB_POWER_SAVING_MODE2".MODE.CR_ASU_DEHUMIDIFYING;
      U     L     84.0;
      U     "DB_POWER_SAVING_MODE2".MODE.CR_ASU_COOLING;
      U(    ;
      L     "DB_GRP_84".CLT81.PV.AV;
      L     "DB_POWER_SAVING_MODE2".GENERAL.SP.CR_ASU_WINDOW_T_MAX;
      <=R   ;
      )     ;
      U(    ;
      L     "DB_GRP_84".CLM82_HUM.PV.AV;
      L     "DB_POWER_SAVING_MODE2".GENERAL.SP.CR_ASU_WINDOW_H_MAX;
      >R    ;
      )     ;
      UN    "DB_GRP_84".VA41.SM.Open;
      S     "DB_POWER_SAVING_MODE2".MODE.CR_ASU_DEHUMIDIFYING;
      U     L     84.0;
      U     "DB_POWER_SAVING_MODE2".MODE.CR_ASU_COOLING;
      SPBNB _0a3;
      L     "DB_POWER_SAVING_MODE2".GENERAL.SP.CR_ASU_WINDOW_T_MAX;
      T     "DB_POWER_SAVING_MODE2".GENERAL.SP.CR_ASU_T;
_0a3: NOP   0;
      U     L     84.0;
      U     "DB_POWER_SAVING_MODE2".MODE.CR_ASU_HEATING;
      SPBNB _0a4;
      L     "DB_POWER_SAVING_MODE2".GENERAL.SP.CR_ASU_WINDOW_T_MIN;
      T     "DB_POWER_SAVING_MODE2".GENERAL.SP.CR_ASU_T;
_0a4: NOP   0;
      U     L     84.0;
      UN    "DB_POWER_SAVING_MODE2".MODE.CR_ASU_COOLING;
      UN    "DB_POWER_SAVING_MODE2".MODE.CR_ASU_HEATING;
      SPBNB _0a5;
      L     "DB_GRP_84".CLT81.PV.AV;
      T     "DB_POWER_SAVING_MODE2".GENERAL.SP.CR_ASU_T;
_0a5: NOP   0;
      U     L     84.0;
      U     "DB_POWER_SAVING_MODE2".MODE.CR_ASU_DEHUMIDIFYING;
      SPBNB _0a6;
      L     "DB_POWER_SAVING_MODE2".GENERAL.SP.CR_ASU_WINDOW_H_MAX;
      T     "DB_POWER_SAVING_MODE2".GENERAL.SP.CR_ASU_H;
_0a6: NOP   0;
      U     L     84.0;
      U     "DB_POWER_SAVING_MODE2".MODE.CR_ASU_HUMIDIFYING;
      SPBNB _0a7;
      L     "DB_POWER_SAVING_MODE2".GENERAL.SP.CR_ASU_WINDOW_H_MIN;
      T     "DB_POWER_SAVING_MODE2".GENERAL.SP.CR_ASU_H;
_0a7: NOP   0;
      U     L     84.0;
      UN    "DB_POWER_SAVING_MODE2".MODE.CR_ASU_DEHUMIDIFYING;
      UN    "DB_POWER_SAVING_MODE2".MODE.CR_ASU_HUMIDIFYING;
      SPBNB _0a8;
      L     "DB_GRP_84".CLM82_HUM.PV.AV;
      T     "DB_POWER_SAVING_MODE2".GENERAL.SP.CR_ASU_H;
_0a8: NOP   0;
NETWORK
TITLE =ASU CONDITION 6
//OUTSIDE TEMPERATURE IN WINDOW, OUTSIDE HUMIDITY > H MAX
//
//HEATING ON (ONLY IF TEMPERATURE GOES DOWN WHILE DEHUMIDIFYING)
//COOLING ON (ONLY IF TEMPERATURE GOES OUT OF WINDOW)
//HUMIDIFYING OFF
//DEHUMIDIFYING ON
//UNTIL WINDOW IS REACHED
//
//HEATING SP T MIN
//DEHUMIDIFYING SP H MAX
      U     "DB_POWER_SAVING_MODE2".CONDITIONS.CR_C6;
      =     L     84.0;
      U     L     84.0;
      U(    ;
      L     "DB_GRP_84".CLT81.PV.AV;
      L     "DB_POWER_SAVING_MODE2".GENERAL.SP.CR_ASU_WINDOW_T_MIN;
      <R    ;
      )     ;
      S     "DB_POWER_SAVING_MODE2".MODE.CR_ASU_HEATING;
      U     L     84.0;
      U     "DB_POWER_SAVING_MODE2".MODE.CR_ASU_HEATING;
      U     "DB_GRP_84".VA51.SM.Close;
      U(    ;
      L     "DB_GRP_84".PP51.PV.AV;
      L     8.000000e+000;
      <R    ;
      )     ;
      U(    ;
      L     "DB_GRP_84".CLT81.PV.AV;
      L     #SW_CR_ASU_STOP_HEATING;
      >R    ;
      )     ;
      L     S5T#40S;
      SE    "T_PS_M2_CR_HEAT_OFF_C6";
      NOP   0;
      NOP   0;
      NOP   0;
      U     "T_PS_M2_CR_HEAT_OFF_C6";
      R     "DB_POWER_SAVING_MODE2".MODE.CR_ASU_HEATING;
      U     L     84.0;
      U(    ;
      L     "DB_GRP_84".CLT81.PV.AV;
      L     "DB_POWER_SAVING_MODE2".GENERAL.SP.CR_ASU_WINDOW_T_MAX;
      >R    ;
      )     ;
      S     "DB_POWER_SAVING_MODE2".MODE.CR_ASU_COOLING;
      U     L     84.0;
      U     "DB_POWER_SAVING_MODE2".MODE.CR_ASU_COOLING;
      U     "DB_GRP_84".VA41.SM.Close;
      U(    ;
      L     "DB_GRP_84".CLT81.PV.AV;
      L     #SW_CR_ASU_STOP_COOLING;
      <R    ;
      )     ;
      R     "DB_POWER_SAVING_MODE2".MODE.CR_ASU_COOLING;
      U     L     84.0;
      BLD   102;
      R     "DB_POWER_SAVING_MODE2".MODE.CR_ASU_HUMIDIFYING;
      U     L     84.0;
      U(    ;
      L     "DB_GRP_84".CLM82_HUM.PV.AV;
      L     "DB_POWER_SAVING_MODE2".GENERAL.SP.CR_ASU_WINDOW_H_MAX;
      >R    ;
      )     ;
      S     "DB_POWER_SAVING_MODE2".MODE.CR_ASU_DEHUMIDIFYING;
      U     L     84.0;
      U     "DB_POWER_SAVING_MODE2".MODE.CR_ASU_DEHUMIDIFYING;
      U(    ;
      L     "DB_GRP_84".CLM82_HUM.PV.AV;
      L     #SW_CR_ASU_STOP_DEHUM;
      <R    ;
      )     ;
      L     S5T#40S;
      SE    "T_PS_M2_CR_DEHUM_OFF_C6";
      NOP   0;
      NOP   0;
      NOP   0;
      U     "T_PS_M2_CR_DEHUM_OFF_C6";
      R     "DB_POWER_SAVING_MODE2".MODE.CR_ASU_DEHUMIDIFYING;
      U     L     84.0;
      U     "DB_POWER_SAVING_MODE2".MODE.CR_ASU_HEATING;
      SPBNB _0a9;
      L     "DB_POWER_SAVING_MODE2".GENERAL.SP.CR_ASU_WINDOW_T_MIN;
      T     "DB_POWER_SAVING_MODE2".GENERAL.SP.CR_ASU_T;
_0a9: NOP   0;
      U     L     84.0;
      U     "DB_POWER_SAVING_MODE2".MODE.CR_ASU_COOLING;
      SPBNB _0aa;
      L     "DB_POWER_SAVING_MODE2".GENERAL.SP.CR_ASU_WINDOW_T_MAX;
      T     "DB_POWER_SAVING_MODE2".GENERAL.SP.CR_ASU_T;
_0aa: NOP   0;
      U     L     84.0;
      UN    "DB_POWER_SAVING_MODE2".MODE.CR_ASU_HEATING;
      UN    "DB_POWER_SAVING_MODE2".MODE.CR_ASU_COOLING;
      SPBNB _0ab;
      L     "DB_GRP_84".CLT81.PV.AV;
      T     "DB_POWER_SAVING_MODE2".GENERAL.SP.CR_ASU_T;
_0ab: NOP   0;
      U     L     84.0;
      U     "DB_POWER_SAVING_MODE2".MODE.CR_ASU_DEHUMIDIFYING;
      SPBNB _0ac;
      L     "DB_POWER_SAVING_MODE2".GENERAL.SP.CR_ASU_WINDOW_H_MAX;
      T     "DB_POWER_SAVING_MODE2".GENERAL.SP.CR_ASU_H;
_0ac: NOP   0;
      U     L     84.0;
      UN    "DB_POWER_SAVING_MODE2".MODE.CR_ASU_DEHUMIDIFYING;
      SPBNB _0ad;
      L     "DB_GRP_84".CLM82_HUM.PV.AV;
      T     "DB_POWER_SAVING_MODE2".GENERAL.SP.CR_ASU_H;
_0ad: NOP   0;
NETWORK
TITLE =ASU CONDITION 7
//OUTSIDE TEMPERATURE < T MIN, OUTSIDE HUMIDITY > H MAX
//
//HEATING ON
//COOLING OFF
//HUMIDIFYING ON (ONLY IF HUMIDITY GOES DOWN BECAUSE OF DEHUMIDIFYING)
//DEHUMIDIFYING ON
//UNTIL WINDOW IS REACHED
//
//HEATING SP T MIN
//DEHUMIDIFYING SP H MAX
      U     "DB_POWER_SAVING_MODE2".CONDITIONS.CR_C7;
      =     L     84.0;
      U     L     84.0;
      U(    ;
      L     "DB_GRP_84".CLT81.PV.AV;
      L     "DB_POWER_SAVING_MODE2".GENERAL.SP.CR_ASU_WINDOW_T_MIN;
      <R    ;
      )     ;
      S     "DB_POWER_SAVING_MODE2".MODE.CR_ASU_HEATING;
      U     L     84.0;
      U     "DB_POWER_SAVING_MODE2".MODE.CR_ASU_HEATING;
      U     "DB_GRP_84".VA51.SM.Close;
      U(    ;
      L     "DB_GRP_84".PP51.PV.AV;
      L     7.500000e+000;
      <=R   ;
      )     ;
      U(    ;
      L     "DB_GRP_84".CLT81.PV.AV;
      L     #SW_CR_ASU_STOP_HEATING;
      >R    ;
      )     ;
      L     S5T#2M;
      SE    "T_PS_M2_CR_HEAT_OFF_C7";
      NOP   0;
      NOP   0;
      NOP   0;
      U     "T_PS_M2_CR_HEAT_OFF_C7";
      R     "DB_POWER_SAVING_MODE2".MODE.CR_ASU_HEATING;
      U     L     84.0;
      BLD   102;
      R     "DB_POWER_SAVING_MODE2".MODE.CR_ASU_COOLING;
      U     L     84.0;
      U     "DB_POWER_SAVING_MODE2".MODE.CR_ASU_HUMIDIFYING;
      U(    ;
      L     "DB_GRP_84".CLM82_HUM.PV.AV;
      L     #SW_CR_ASU_STOP_HUM;
      >R    ;
      )     ;
      U(    ;
      L     "DB_GRP_84".PP61.PV.Frq_AV;
      L     7.500000e+000;
      <R    ;
      )     ;
      L     S5T#40S;
      SE    "T_PS_M2_CR_HUM_OFF_C7";
      NOP   0;
      NOP   0;
      NOP   0;
      NOP   0;
      U     L     84.0;
      U(    ;
      O     "DB_POWER_SAVING_MODE2".MODE.CR_ASU_DEHUMIDIFYING;
      O     "T_PS_M2_CR_HUM_OFF_C7";
      )     ;
      R     "DB_POWER_SAVING_MODE2".MODE.CR_ASU_HUMIDIFYING;
      U     L     84.0;
      U(    ;
      L     "DB_GRP_84".CLM82_HUM.PV.AV;
      L     "DB_POWER_SAVING_MODE2".GENERAL.SP.CR_ASU_WINDOW_H_MIN;
      <R    ;
      )     ;
      S     "DB_POWER_SAVING_MODE2".MODE.CR_ASU_HUMIDIFYING;
      U     L     84.0;
      U     "DB_POWER_SAVING_MODE2".MODE.CR_ASU_DEHUMIDIFYING;
      U(    ;
      L     "DB_GRP_84".CLM82_HUM.PV.AV;
      L     #SW_CR_ASU_STOP_DEHUM;
      <R    ;
      )     ;
      L     S5T#1M;
      SE    "T_PS_M2_CR_DEHUM_OFF_C7";
      NOP   0;
      NOP   0;
      NOP   0;
      NOP   0;
      U     L     84.0;
      U(    ;
      O     "DB_POWER_SAVING_MODE2".MODE.CR_ASU_HUMIDIFYING;
      O     "T_PS_M2_CR_DEHUM_OFF_C7";
      )     ;
      R     "DB_POWER_SAVING_MODE2".MODE.CR_ASU_DEHUMIDIFYING;
      U     L     84.0;
      U(    ;
      L     "DB_GRP_84".CLM82_HUM.PV.AV;
      L     "DB_POWER_SAVING_MODE2".GENERAL.SP.CR_ASU_WINDOW_H_MAX;
      >R    ;
      )     ;
      S     "DB_POWER_SAVING_MODE2".MODE.CR_ASU_DEHUMIDIFYING;
      U     L     84.0;
      U     "DB_POWER_SAVING_MODE2".MODE.CR_ASU_HEATING;
      SPBNB _0ae;
      L     "DB_POWER_SAVING_MODE2".GENERAL.SP.CR_ASU_WINDOW_T_MIN;
      T     "DB_POWER_SAVING_MODE2".GENERAL.SP.CR_ASU_T;
_0ae: NOP   0;
      U     L     84.0;
      UN    "DB_POWER_SAVING_MODE2".MODE.CR_ASU_HEATING;
      SPBNB _0af;
      L     "DB_GRP_84".CLT81.PV.AV;
      T     "DB_POWER_SAVING_MODE2".GENERAL.SP.CR_ASU_T;
_0af: NOP   0;
      U     L     84.0;
      U     "DB_POWER_SAVING_MODE2".MODE.CR_ASU_DEHUMIDIFYING;
      SPBNB _0b0;
      L     "DB_POWER_SAVING_MODE2".GENERAL.SP.CR_ASU_WINDOW_H_MAX;
      T     "DB_POWER_SAVING_MODE2".GENERAL.SP.CR_ASU_H;
_0b0: NOP   0;
      U     L     84.0;
      U     "DB_POWER_SAVING_MODE2".MODE.CR_ASU_HUMIDIFYING;
      SPBNB _0b1;
      L     "DB_POWER_SAVING_MODE2".GENERAL.SP.CR_ASU_WINDOW_H_MIN;
      T     "DB_POWER_SAVING_MODE2".GENERAL.SP.CR_ASU_H;
_0b1: NOP   0;
      U     L     84.0;
      UN    "DB_POWER_SAVING_MODE2".MODE.CR_ASU_DEHUMIDIFYING;
      UN    "DB_POWER_SAVING_MODE2".MODE.CR_ASU_HUMIDIFYING;
      SPBNB _0b2;
      L     "DB_GRP_84".CLM82_HUM.PV.AV;
      T     "DB_POWER_SAVING_MODE2".GENERAL.SP.CR_ASU_H;
_0b2: NOP   0;
NETWORK
TITLE =ASU CONDITION 8
//OUTSIDE TEMPERATURE < T MIN, OUTSIDE HUMIDITY IN WINDOW
//
//HEATING ON
//COOLING OFF
//HUMIDIFYING (ONLY IF HUMIDITY GOES DOWN BECAUSE OF HEATING)
//DEHUMIDIFYING ON
//UNTIL WINDOW IS REACHED
//
//HEATING SP T MIN
//HUMIDIFYING SP H MIN
//DEHUMIDIFYING SP H MAX
      U     "DB_POWER_SAVING_MODE2".CONDITIONS.CR_C8;
      =     L     84.0;
      U     L     84.0;
      U(    ;
      L     "DB_GRP_84".CLT81.PV.AV;
      L     "DB_POWER_SAVING_MODE2".GENERAL.SP.CR_ASU_WINDOW_T_MIN;
      <R    ;
      )     ;
      S     "DB_POWER_SAVING_MODE2".MODE.CR_ASU_HEATING;
      U     L     84.0;
      U     "DB_POWER_SAVING_MODE2".MODE.CR_ASU_HEATING;
      U     "DB_GRP_84".VA51.SM.Close;
      U(    ;
      L     "DB_GRP_84".PP51.PV.AV;
      L     7.500000e+000;
      <=R   ;
      )     ;
      U(    ;
      L     "DB_GRP_84".CLT81.PV.AV;
      L     #SW_CR_ASU_STOP_HEATING;
      >R    ;
      )     ;
      L     S5T#2M;
      SE    "T_PS_M2_CR_HEAT_OFF_C8";
      NOP   0;
      NOP   0;
      NOP   0;
      U     "T_PS_M2_CR_HEAT_OFF_C8";
      R     "DB_POWER_SAVING_MODE2".MODE.CR_ASU_HEATING;
      U     L     84.0;
      BLD   102;
      R     "DB_POWER_SAVING_MODE2".MODE.CR_ASU_COOLING;
      U     L     84.0;
      U(    ;
      L     "DB_GRP_84".CLM82_HUM.PV.AV;
      L     "DB_POWER_SAVING_MODE2".GENERAL.SP.CR_ASU_WINDOW_H_MIN;
      <R    ;
      )     ;
      S     "DB_POWER_SAVING_MODE2".MODE.CR_ASU_HUMIDIFYING;
      U     L     84.0;
      U     "DB_POWER_SAVING_MODE2".MODE.CR_ASU_HUMIDIFYING;
      U(    ;
      L     "DB_GRP_84".CLM82_HUM.PV.AV;
      L     #SW_CR_ASU_STOP_HUM;
      >R    ;
      )     ;
      U(    ;
      L     "DB_GRP_84".PP61.PV.Frq_AV;
      L     7.500000e+000;
      <R    ;
      )     ;
      L     S5T#40S;
      SE    "T_PS_M2_CR_HUM_OFF_C8";
      NOP   0;
      NOP   0;
      NOP   0;
      U     "T_PS_M2_CR_HUM_OFF_C8";
      R     "DB_POWER_SAVING_MODE2".MODE.CR_ASU_HUMIDIFYING;
      U     L     84.0;
      BLD   102;
      R     "DB_POWER_SAVING_MODE2".MODE.CR_ASU_DEHUMIDIFYING;
      U     L     84.0;
      U     "DB_POWER_SAVING_MODE2".MODE.CR_ASU_HEATING;
      SPBNB _0b3;
      L     "DB_POWER_SAVING_MODE2".GENERAL.SP.CR_ASU_WINDOW_T_MIN;
      T     "DB_POWER_SAVING_MODE2".GENERAL.SP.CR_ASU_T;
_0b3: NOP   0;
      U     L     84.0;
      UN    "DB_POWER_SAVING_MODE2".MODE.CR_ASU_HEATING;
      SPBNB _0b4;
      L     "DB_GRP_84".CLT81.PV.AV;
      T     "DB_POWER_SAVING_MODE2".GENERAL.SP.CR_ASU_T;
_0b4: NOP   0;
      U     L     84.0;
      U     "DB_POWER_SAVING_MODE2".MODE.CR_ASU_HUMIDIFYING;
      SPBNB _0b5;
      L     "DB_POWER_SAVING_MODE2".GENERAL.SP.CR_ASU_WINDOW_H_MIN;
      T     "DB_POWER_SAVING_MODE2".GENERAL.SP.CR_ASU_H;
_0b5: NOP   0;
      U     L     84.0;
      UN    "DB_POWER_SAVING_MODE2".MODE.CR_ASU_HUMIDIFYING;
      SPBNB _0b6;
      L     "DB_GRP_84".CLM82_HUM.PV.AV;
      T     "DB_POWER_SAVING_MODE2".GENERAL.SP.CR_ASU_H;
_0b6: NOP   0;
NETWORK
TITLE =TRANSFER SETPOINTS

      U     "DB_POWER_SAVING_MODE2".GENERAL.SM.CR_MODE_2_ON;
      U(    ;
      O     "DB_PROG_CLEAN_ROOM".CLEAN_ROOM.SM.ON;
      O     ;
      U     "DB_PROG_CLEAN_ROOM".CLEAN_ROOM.SM.STOP;
      UN    "T_CR_FOLLOW_UP_PURING";
      )     ;
      =     L     84.0;
      U     L     84.0;
      SPBNB _0b7;
      L     "DB_POWER_SAVING_MODE2".GENERAL.SP.CR_ASU_T;
      T     "DB_GRP_84".CLT81.PV.SP_AV;
_0b7: NOP   0;
      U     L     84.0;
      SPBNB _0b8;
      L     "DB_POWER_SAVING_MODE2".GENERAL.SP.CR_ASU_H;
      T     "DB_GRP_84".CLM82_HUM.PV.SP_AV;
_0b8: NOP   0;
NETWORK
TITLE =RESTORE SETPOINTS IF PS1 AND PS2 ARE DISABLED
//********************************************************************************
//
//                               RESTORE SETPOINTS
//
//********************************************************************************
//
      U     "LOG_1";
      =     L     84.0;
      U     L     84.0;
      UN    "DB_POWER_SAVING_MODE1".GENERAL.SM.PR_MODE_1_ON;
      UN    "DB_POWER_SAVING_MODE2".GENERAL.SM.PR_MODE_2_ON;
      =     L     84.1;
      U     L     84.1;
      SPBNB _0b9;
      L     "DB_SETPOINTS".TEMP_81CLT81_SP;
      T     "DB_GRP_81".CLT81.PV.SP_AV;
_0b9: NOP   0;
      U     L     84.1;
      SPBNB _0ba;
      L     "DB_SETPOINTS".HUM_81CLM82_SP;
      T     "DB_GRP_81".CLM82_HUM.PV.SP_AV;
_0ba: NOP   0;
      U     L     84.1;
      SPBNB _0bb;
      L     "DB_SETPOINTS".TEMP_82CLT81_SP;
      T     "DB_GRP_82".CLT81.PV.SP_AV;
_0bb: NOP   0;
      U     L     84.1;
      SPBNB _0bc;
      L     "DB_SETPOINTS".HUM_82CLM82_SP;
      T     "DB_GRP_82".CLM82_HUM.PV.SP_AV;
_0bc: NOP   0;
      U     L     84.1;
      SPBNB _0bd;
      L     "DB_SETPOINTS".TEMP_83CLT81_SP;
      T     "DB_GRP_83".CLT81.PV.SP_AV;
_0bd: NOP   0;
      U     L     84.0;
      UN    "DB_POWER_SAVING_MODE1".GENERAL.SM.CR_MODE_1_ON;
      UN    "DB_POWER_SAVING_MODE2".GENERAL.SM.CR_MODE_2_ON;
      =     L     84.1;
      U     L     84.1;
      SPBNB _0be;
      L     "DB_SETPOINTS".TEMP_84CLT81_SP;
      T     "DB_GRP_84".CLT81.PV.SP_AV;
_0be: NOP   0;
      U     L     84.1;
      SPBNB _0bf;
      L     "DB_SETPOINTS".HUM_84CLT81_SP;
      T     "DB_GRP_84".CLM82_HUM.PV.SP_AV;
_0bf: NOP   0;
END_FUNCTION

